VERSION 5.7 ;
  NOWIREEXTENSIONATPIN ON ;
  DIVIDERCHAR "/" ;
  BUSBITCHARS "[]" ;
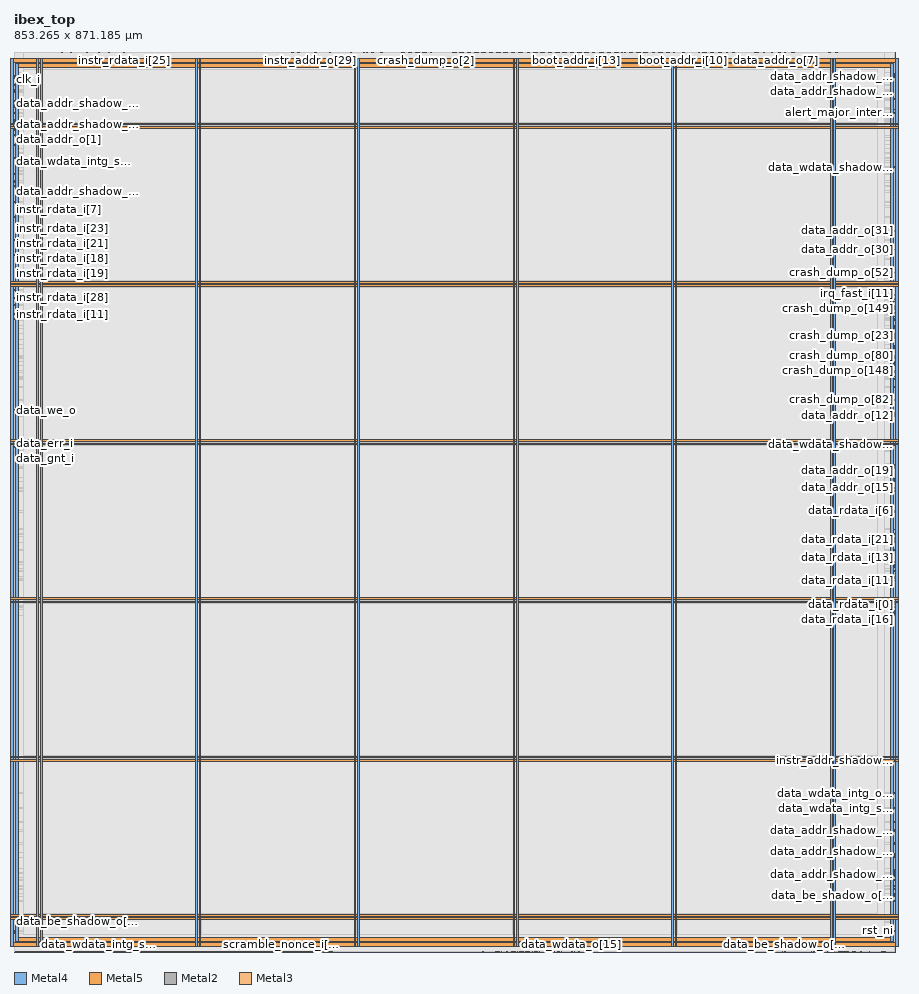
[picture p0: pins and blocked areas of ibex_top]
MACRO ibex_top
  CLASS BLOCK ;
  FOREIGN ibex_top ;
  ORIGIN 0.000 0.000 ;
  SIZE 853.265 BY 871.185 ;
  PIN VDD
    DIRECTION INOUT ;
    USE POWER ;
    PORT
      LAYER Metal4 ;
        RECT 1.620 10.580 4.720 859.660 ;
    END
    PORT
      LAYER Metal4 ;
        RECT 848.160 10.580 851.260 859.660 ;
    END
    PORT
      LAYER Metal5 ;
        RECT 1.620 10.580 851.260 13.680 ;
    END
    PORT
      LAYER Metal5 ;
        RECT 1.620 856.560 851.260 859.660 ;
    END
    PORT
      LAYER Metal4 ;
        RECT 22.240 5.780 23.840 864.460 ;
    END
    PORT
      LAYER Metal4 ;
        RECT 175.840 5.780 177.440 864.460 ;
    END
    PORT
      LAYER Metal4 ;
        RECT 329.440 5.780 331.040 864.460 ;
    END
    PORT
      LAYER Metal4 ;
        RECT 483.040 5.780 484.640 864.460 ;
    END
    PORT
      LAYER Metal4 ;
        RECT 636.640 5.780 638.240 864.460 ;
    END
    PORT
      LAYER Metal4 ;
        RECT 790.240 5.780 791.840 864.460 ;
    END
    PORT
      LAYER Metal5 ;
        RECT -3.180 31.530 856.060 33.130 ;
    END
    PORT
      LAYER Metal5 ;
        RECT -3.180 184.710 856.060 186.310 ;
    END
    PORT
      LAYER Metal5 ;
        RECT -3.180 337.890 856.060 339.490 ;
    END
    PORT
      LAYER Metal5 ;
        RECT -3.180 491.070 856.060 492.670 ;
    END
    PORT
      LAYER Metal5 ;
        RECT -3.180 644.250 856.060 645.850 ;
    END
    PORT
      LAYER Metal5 ;
        RECT -3.180 797.430 856.060 799.030 ;
    END
  END VDD
  PIN VSS
    DIRECTION INOUT ;
    USE GROUND ;
    PORT
      LAYER Metal4 ;
        RECT -3.180 5.780 -0.080 864.460 ;
    END
    PORT
      LAYER Metal4 ;
        RECT 852.960 5.780 856.060 864.460 ;
    END
    PORT
      LAYER Metal5 ;
        RECT -3.180 5.780 856.060 8.880 ;
    END
    PORT
      LAYER Metal5 ;
        RECT -3.180 861.360 856.060 864.460 ;
    END
    PORT
      LAYER Metal4 ;
        RECT 25.540 5.780 27.140 864.460 ;
    END
    PORT
      LAYER Metal4 ;
        RECT 179.140 5.780 180.740 864.460 ;
    END
    PORT
      LAYER Metal4 ;
        RECT 332.740 5.780 334.340 864.460 ;
    END
    PORT
      LAYER Metal4 ;
        RECT 486.340 5.780 487.940 864.460 ;
    END
    PORT
      LAYER Metal4 ;
        RECT 639.940 5.780 641.540 864.460 ;
    END
    PORT
      LAYER Metal4 ;
        RECT 793.540 5.780 795.140 864.460 ;
    END
    PORT
      LAYER Metal5 ;
        RECT -3.180 34.830 856.060 36.430 ;
    END
    PORT
      LAYER Metal5 ;
        RECT -3.180 188.010 856.060 189.610 ;
    END
    PORT
      LAYER Metal5 ;
        RECT -3.180 341.190 856.060 342.790 ;
    END
    PORT
      LAYER Metal5 ;
        RECT -3.180 494.370 856.060 495.970 ;
    END
    PORT
      LAYER Metal5 ;
        RECT -3.180 647.550 856.060 649.150 ;
    END
    PORT
      LAYER Metal5 ;
        RECT -3.180 800.730 856.060 802.330 ;
    END
  END VSS
  PIN alert_major_bus_o
    DIRECTION OUTPUT ;
    USE SIGNAL ;
    ANTENNADIFFAREA 0.360800 ;
    PORT
      LAYER Metal2 ;
        RECT 31.360 0.000 31.920 0.560 ;
    END
  END alert_major_bus_o
  PIN alert_major_internal_o
    DIRECTION OUTPUT ;
    USE SIGNAL ;
    ANTENNADIFFAREA 0.360800 ;
    PORT
      LAYER Metal3 ;
        RECT 852.705 812.000 853.265 812.560 ;
    END
  END alert_major_internal_o
  PIN alert_minor_o
    DIRECTION OUTPUT ;
    USE SIGNAL ;
    ANTENNADIFFAREA 0.360800 ;
    PORT
      LAYER Metal3 ;
        RECT 852.705 53.760 853.265 54.320 ;
    END
  END alert_minor_o
  PIN boot_addr_i[0]
    DIRECTION INPUT ;
    USE SIGNAL ;
    PORT
      LAYER Metal2 ;
        RECT 7.840 0.000 8.400 0.560 ;
    END
  END boot_addr_i[0]
  PIN boot_addr_i[10]
    DIRECTION INPUT ;
    USE SIGNAL ;
    ANTENNAGATEAREA 0.396000 ;
    PORT
      LAYER Metal2 ;
        RECT 647.360 870.625 647.920 871.185 ;
    END
  END boot_addr_i[10]
  PIN boot_addr_i[11]
    DIRECTION INPUT ;
    USE SIGNAL ;
    ANTENNAGATEAREA 0.396000 ;
    PORT
      LAYER Metal2 ;
        RECT 483.840 870.625 484.400 871.185 ;
    END
  END boot_addr_i[11]
  PIN boot_addr_i[12]
    DIRECTION INPUT ;
    USE SIGNAL ;
    ANTENNAGATEAREA 0.396000 ;
    PORT
      LAYER Metal2 ;
        RECT 493.920 870.625 494.480 871.185 ;
    END
  END boot_addr_i[12]
  PIN boot_addr_i[13]
    DIRECTION INPUT ;
    USE SIGNAL ;
    ANTENNAGATEAREA 0.396000 ;
    PORT
      LAYER Metal2 ;
        RECT 544.320 870.625 544.880 871.185 ;
    END
  END boot_addr_i[13]
  PIN boot_addr_i[14]
    DIRECTION INPUT ;
    USE SIGNAL ;
    ANTENNAGATEAREA 0.396000 ;
    PORT
      LAYER Metal2 ;
        RECT 619.360 870.625 619.920 871.185 ;
    END
  END boot_addr_i[14]
  PIN boot_addr_i[15]
    DIRECTION INPUT ;
    USE SIGNAL ;
    ANTENNAGATEAREA 0.396000 ;
    PORT
      LAYER Metal2 ;
        RECT 556.640 870.625 557.200 871.185 ;
    END
  END boot_addr_i[15]
  PIN boot_addr_i[16]
    DIRECTION INPUT ;
    USE SIGNAL ;
    ANTENNAGATEAREA 0.396000 ;
    PORT
      LAYER Metal2 ;
        RECT 568.960 870.625 569.520 871.185 ;
    END
  END boot_addr_i[16]
  PIN boot_addr_i[17]
    DIRECTION INPUT ;
    USE SIGNAL ;
    ANTENNAGATEAREA 0.396000 ;
    PORT
      LAYER Metal2 ;
        RECT 600.320 870.625 600.880 871.185 ;
    END
  END boot_addr_i[17]
  PIN boot_addr_i[18]
    DIRECTION INPUT ;
    USE SIGNAL ;
    ANTENNAGATEAREA 0.396000 ;
    PORT
      LAYER Metal2 ;
        RECT 651.840 870.625 652.400 871.185 ;
    END
  END boot_addr_i[18]
  PIN boot_addr_i[19]
    DIRECTION INPUT ;
    USE SIGNAL ;
    ANTENNAGATEAREA 0.396000 ;
    PORT
      LAYER Metal2 ;
        RECT 649.600 870.625 650.160 871.185 ;
    END
  END boot_addr_i[19]
  PIN boot_addr_i[1]
    DIRECTION INPUT ;
    USE SIGNAL ;
    PORT
      LAYER Metal2 ;
        RECT 5.600 0.000 6.160 0.560 ;
    END
  END boot_addr_i[1]
  PIN boot_addr_i[20]
    DIRECTION INPUT ;
    USE SIGNAL ;
    ANTENNAGATEAREA 0.396000 ;
    PORT
      LAYER Metal2 ;
        RECT 623.840 870.625 624.400 871.185 ;
    END
  END boot_addr_i[20]
  PIN boot_addr_i[21]
    DIRECTION INPUT ;
    USE SIGNAL ;
    ANTENNAGATEAREA 0.396000 ;
    PORT
      LAYER Metal2 ;
        RECT 588.000 870.625 588.560 871.185 ;
    END
  END boot_addr_i[21]
  PIN boot_addr_i[22]
    DIRECTION INPUT ;
    USE SIGNAL ;
    ANTENNAGATEAREA 0.396000 ;
    PORT
      LAYER Metal2 ;
        RECT 648.480 870.625 649.040 871.185 ;
    END
  END boot_addr_i[22]
  PIN boot_addr_i[23]
    DIRECTION INPUT ;
    USE SIGNAL ;
    ANTENNAGATEAREA 0.396000 ;
    PORT
      LAYER Metal2 ;
        RECT 650.720 870.625 651.280 871.185 ;
    END
  END boot_addr_i[23]
  PIN boot_addr_i[24]
    DIRECTION INPUT ;
    USE SIGNAL ;
    ANTENNAGATEAREA 0.396000 ;
    PORT
      LAYER Metal2 ;
        RECT 612.640 870.625 613.200 871.185 ;
    END
  END boot_addr_i[24]
  PIN boot_addr_i[25]
    DIRECTION INPUT ;
    USE SIGNAL ;
    ANTENNAGATEAREA 0.396000 ;
    PORT
      LAYER Metal2 ;
        RECT 543.200 870.625 543.760 871.185 ;
    END
  END boot_addr_i[25]
  PIN boot_addr_i[26]
    DIRECTION INPUT ;
    USE SIGNAL ;
    ANTENNAGATEAREA 0.396000 ;
    PORT
      LAYER Metal2 ;
        RECT 481.600 870.625 482.160 871.185 ;
    END
  END boot_addr_i[26]
  PIN boot_addr_i[27]
    DIRECTION INPUT ;
    USE SIGNAL ;
    ANTENNAGATEAREA 0.396000 ;
    PORT
      LAYER Metal2 ;
        RECT 638.400 870.625 638.960 871.185 ;
    END
  END boot_addr_i[27]
  PIN boot_addr_i[28]
    DIRECTION INPUT ;
    USE SIGNAL ;
    ANTENNAGATEAREA 0.396000 ;
    PORT
      LAYER Metal2 ;
        RECT 618.240 870.625 618.800 871.185 ;
    END
  END boot_addr_i[28]
  PIN boot_addr_i[29]
    DIRECTION INPUT ;
    USE SIGNAL ;
    ANTENNAGATEAREA 0.396000 ;
    PORT
      LAYER Metal2 ;
        RECT 452.480 870.625 453.040 871.185 ;
    END
  END boot_addr_i[29]
  PIN boot_addr_i[2]
    DIRECTION INPUT ;
    USE SIGNAL ;
    PORT
      LAYER Metal2 ;
        RECT 11.200 0.000 11.760 0.560 ;
    END
  END boot_addr_i[2]
  PIN boot_addr_i[30]
    DIRECTION INPUT ;
    USE SIGNAL ;
    ANTENNAGATEAREA 0.396000 ;
    PORT
      LAYER Metal2 ;
        RECT 470.400 870.625 470.960 871.185 ;
    END
  END boot_addr_i[30]
  PIN boot_addr_i[31]
    DIRECTION INPUT ;
    USE SIGNAL ;
    ANTENNAGATEAREA 0.396000 ;
    PORT
      LAYER Metal2 ;
        RECT 469.280 870.625 469.840 871.185 ;
    END
  END boot_addr_i[31]
  PIN boot_addr_i[3]
    DIRECTION INPUT ;
    USE SIGNAL ;
    PORT
      LAYER Metal2 ;
        RECT 44.800 0.000 45.360 0.560 ;
    END
  END boot_addr_i[3]
  PIN boot_addr_i[4]
    DIRECTION INPUT ;
    USE SIGNAL ;
    PORT
      LAYER Metal2 ;
        RECT 6.720 0.000 7.280 0.560 ;
    END
  END boot_addr_i[4]
  PIN boot_addr_i[5]
    DIRECTION INPUT ;
    USE SIGNAL ;
    PORT
      LAYER Metal2 ;
        RECT 10.080 0.000 10.640 0.560 ;
    END
  END boot_addr_i[5]
  PIN boot_addr_i[6]
    DIRECTION INPUT ;
    USE SIGNAL ;
    PORT
      LAYER Metal2 ;
        RECT 8.960 0.000 9.520 0.560 ;
    END
  END boot_addr_i[6]
  PIN boot_addr_i[7]
    DIRECTION INPUT ;
    USE SIGNAL ;
    PORT
      LAYER Metal2 ;
        RECT 12.320 0.000 12.880 0.560 ;
    END
  END boot_addr_i[7]
  PIN boot_addr_i[8]
    DIRECTION INPUT ;
    USE SIGNAL ;
    ANTENNAGATEAREA 0.396000 ;
    PORT
      LAYER Metal2 ;
        RECT 436.800 870.625 437.360 871.185 ;
    END
  END boot_addr_i[8]
  PIN boot_addr_i[9]
    DIRECTION INPUT ;
    USE SIGNAL ;
    ANTENNAGATEAREA 0.396000 ;
    PORT
      LAYER Metal2 ;
        RECT 463.680 870.625 464.240 871.185 ;
    END
  END boot_addr_i[9]
  PIN clk_i
    DIRECTION INPUT ;
    USE SIGNAL ;
    ANTENNAGATEAREA 4.738000 ;
    PORT
      LAYER Metal3 ;
        RECT 0.000 844.480 0.560 845.040 ;
    END
  END clk_i
  PIN core_sleep_o
    DIRECTION OUTPUT ;
    USE SIGNAL ;
    ANTENNADIFFAREA 0.897600 ;
    PORT
      LAYER Metal2 ;
        RECT 291.200 870.625 291.760 871.185 ;
    END
  END core_sleep_o
  PIN crash_dump_o[0]
    DIRECTION OUTPUT ;
    USE SIGNAL ;
    ANTENNADIFFAREA 0.897600 ;
    PORT
      LAYER Metal2 ;
        RECT 383.040 870.625 383.600 871.185 ;
    END
  END crash_dump_o[0]
  PIN crash_dump_o[100]
    DIRECTION OUTPUT ;
    USE SIGNAL ;
    ANTENNADIFFAREA 0.897600 ;
    PORT
      LAYER Metal2 ;
        RECT 355.040 870.625 355.600 871.185 ;
    END
  END crash_dump_o[100]
  PIN crash_dump_o[101]
    DIRECTION OUTPUT ;
    USE SIGNAL ;
    ANTENNADIFFAREA 0.897600 ;
    PORT
      LAYER Metal2 ;
        RECT 397.600 870.625 398.160 871.185 ;
    END
  END crash_dump_o[101]
  PIN crash_dump_o[102]
    DIRECTION OUTPUT ;
    USE SIGNAL ;
    ANTENNADIFFAREA 0.897600 ;
    PORT
      LAYER Metal2 ;
        RECT 381.920 870.625 382.480 871.185 ;
    END
  END crash_dump_o[102]
  PIN crash_dump_o[103]
    DIRECTION OUTPUT ;
    USE SIGNAL ;
    ANTENNADIFFAREA 0.897600 ;
    PORT
      LAYER Metal2 ;
        RECT 434.560 870.625 435.120 871.185 ;
    END
  END crash_dump_o[103]
  PIN crash_dump_o[104]
    DIRECTION OUTPUT ;
    USE SIGNAL ;
    ANTENNADIFFAREA 0.897600 ;
    PORT
      LAYER Metal2 ;
        RECT 460.320 870.625 460.880 871.185 ;
    END
  END crash_dump_o[104]
  PIN crash_dump_o[105]
    DIRECTION OUTPUT ;
    USE SIGNAL ;
    ANTENNADIFFAREA 0.897600 ;
    PORT
      LAYER Metal2 ;
        RECT 477.120 870.625 477.680 871.185 ;
    END
  END crash_dump_o[105]
  PIN crash_dump_o[106]
    DIRECTION OUTPUT ;
    USE SIGNAL ;
    ANTENNADIFFAREA 0.897600 ;
    PORT
      LAYER Metal2 ;
        RECT 539.840 870.625 540.400 871.185 ;
    END
  END crash_dump_o[106]
  PIN crash_dump_o[107]
    DIRECTION OUTPUT ;
    USE SIGNAL ;
    ANTENNADIFFAREA 0.897600 ;
    PORT
      LAYER Metal2 ;
        RECT 515.200 870.625 515.760 871.185 ;
    END
  END crash_dump_o[107]
  PIN crash_dump_o[108]
    DIRECTION OUTPUT ;
    USE SIGNAL ;
    ANTENNADIFFAREA 0.897600 ;
    PORT
      LAYER Metal2 ;
        RECT 512.960 870.625 513.520 871.185 ;
    END
  END crash_dump_o[108]
  PIN crash_dump_o[109]
    DIRECTION OUTPUT ;
    USE SIGNAL ;
    ANTENNADIFFAREA 0.897600 ;
    PORT
      LAYER Metal2 ;
        RECT 540.960 870.625 541.520 871.185 ;
    END
  END crash_dump_o[109]
  PIN crash_dump_o[10]
    DIRECTION OUTPUT ;
    USE SIGNAL ;
    ANTENNADIFFAREA 0.897600 ;
    PORT
      LAYER Metal2 ;
        RECT 668.640 870.625 669.200 871.185 ;
    END
  END crash_dump_o[10]
  PIN crash_dump_o[110]
    DIRECTION OUTPUT ;
    USE SIGNAL ;
    ANTENNADIFFAREA 0.897600 ;
    PORT
      LAYER Metal2 ;
        RECT 571.200 870.625 571.760 871.185 ;
    END
  END crash_dump_o[110]
  PIN crash_dump_o[111]
    DIRECTION OUTPUT ;
    USE SIGNAL ;
    ANTENNADIFFAREA 0.897600 ;
    PORT
      LAYER Metal2 ;
        RECT 553.280 870.625 553.840 871.185 ;
    END
  END crash_dump_o[111]
  PIN crash_dump_o[112]
    DIRECTION OUTPUT ;
    USE SIGNAL ;
    ANTENNADIFFAREA 0.897600 ;
    PORT
      LAYER Metal2 ;
        RECT 581.280 870.625 581.840 871.185 ;
    END
  END crash_dump_o[112]
  PIN crash_dump_o[113]
    DIRECTION OUTPUT ;
    USE SIGNAL ;
    ANTENNADIFFAREA 0.897600 ;
    PORT
      LAYER Metal2 ;
        RECT 604.800 870.625 605.360 871.185 ;
    END
  END crash_dump_o[113]
  PIN crash_dump_o[114]
    DIRECTION OUTPUT ;
    USE SIGNAL ;
    ANTENNADIFFAREA 0.897600 ;
    PORT
      LAYER Metal2 ;
        RECT 620.480 870.625 621.040 871.185 ;
    END
  END crash_dump_o[114]
  PIN crash_dump_o[115]
    DIRECTION OUTPUT ;
    USE SIGNAL ;
    ANTENNADIFFAREA 0.897600 ;
    PORT
      LAYER Metal2 ;
        RECT 608.160 870.625 608.720 871.185 ;
    END
  END crash_dump_o[115]
  PIN crash_dump_o[116]
    DIRECTION OUTPUT ;
    USE SIGNAL ;
    ANTENNADIFFAREA 0.897600 ;
    PORT
      LAYER Metal2 ;
        RECT 605.920 870.625 606.480 871.185 ;
    END
  END crash_dump_o[116]
  PIN crash_dump_o[117]
    DIRECTION OUTPUT ;
    USE SIGNAL ;
    ANTENNADIFFAREA 0.897600 ;
    PORT
      LAYER Metal2 ;
        RECT 593.600 870.625 594.160 871.185 ;
    END
  END crash_dump_o[117]
  PIN crash_dump_o[118]
    DIRECTION OUTPUT ;
    USE SIGNAL ;
    ANTENNADIFFAREA 0.897600 ;
    PORT
      LAYER Metal2 ;
        RECT 613.760 870.625 614.320 871.185 ;
    END
  END crash_dump_o[118]
  PIN crash_dump_o[119]
    DIRECTION OUTPUT ;
    USE SIGNAL ;
    ANTENNADIFFAREA 0.897600 ;
    PORT
      LAYER Metal2 ;
        RECT 607.040 870.625 607.600 871.185 ;
    END
  END crash_dump_o[119]
  PIN crash_dump_o[11]
    DIRECTION OUTPUT ;
    USE SIGNAL ;
    ANTENNADIFFAREA 0.897600 ;
    PORT
      LAYER Metal2 ;
        RECT 518.560 870.625 519.120 871.185 ;
    END
  END crash_dump_o[11]
  PIN crash_dump_o[120]
    DIRECTION OUTPUT ;
    USE SIGNAL ;
    ANTENNADIFFAREA 0.897600 ;
    PORT
      LAYER Metal2 ;
        RECT 592.480 870.625 593.040 871.185 ;
    END
  END crash_dump_o[120]
  PIN crash_dump_o[121]
    DIRECTION OUTPUT ;
    USE SIGNAL ;
    ANTENNADIFFAREA 0.897600 ;
    PORT
      LAYER Metal2 ;
        RECT 538.720 870.625 539.280 871.185 ;
    END
  END crash_dump_o[121]
  PIN crash_dump_o[122]
    DIRECTION OUTPUT ;
    USE SIGNAL ;
    ANTENNADIFFAREA 0.897600 ;
    PORT
      LAYER Metal2 ;
        RECT 526.400 870.625 526.960 871.185 ;
    END
  END crash_dump_o[122]
  PIN crash_dump_o[123]
    DIRECTION OUTPUT ;
    USE SIGNAL ;
    ANTENNADIFFAREA 0.897600 ;
    PORT
      LAYER Metal2 ;
        RECT 595.840 870.625 596.400 871.185 ;
    END
  END crash_dump_o[123]
  PIN crash_dump_o[124]
    DIRECTION OUTPUT ;
    USE SIGNAL ;
    ANTENNADIFFAREA 0.897600 ;
    PORT
      LAYER Metal2 ;
        RECT 594.720 870.625 595.280 871.185 ;
    END
  END crash_dump_o[124]
  PIN crash_dump_o[125]
    DIRECTION OUTPUT ;
    USE SIGNAL ;
    ANTENNADIFFAREA 0.897600 ;
    PORT
      LAYER Metal2 ;
        RECT 471.520 870.625 472.080 871.185 ;
    END
  END crash_dump_o[125]
  PIN crash_dump_o[126]
    DIRECTION OUTPUT ;
    USE SIGNAL ;
    ANTENNADIFFAREA 0.897600 ;
    PORT
      LAYER Metal2 ;
        RECT 491.680 870.625 492.240 871.185 ;
    END
  END crash_dump_o[126]
  PIN crash_dump_o[127]
    DIRECTION OUTPUT ;
    USE SIGNAL ;
    ANTENNADIFFAREA 0.897600 ;
    PORT
      LAYER Metal2 ;
        RECT 459.200 870.625 459.760 871.185 ;
    END
  END crash_dump_o[127]
  PIN crash_dump_o[128]
    DIRECTION OUTPUT ;
    USE SIGNAL ;
    ANTENNADIFFAREA 0.360800 ;
    PORT
      LAYER Metal3 ;
        RECT 0.000 846.720 0.560 847.280 ;
    END
  END crash_dump_o[128]
  PIN crash_dump_o[129]
    DIRECTION OUTPUT ;
    USE SIGNAL ;
    ANTENNADIFFAREA 0.897600 ;
    PORT
      LAYER Metal2 ;
        RECT 403.200 870.625 403.760 871.185 ;
    END
  END crash_dump_o[129]
  PIN crash_dump_o[12]
    DIRECTION OUTPUT ;
    USE SIGNAL ;
    ANTENNADIFFAREA 0.897600 ;
    PORT
      LAYER Metal2 ;
        RECT 533.120 870.625 533.680 871.185 ;
    END
  END crash_dump_o[12]
  PIN crash_dump_o[130]
    DIRECTION OUTPUT ;
    USE SIGNAL ;
    ANTENNADIFFAREA 0.897600 ;
    PORT
      LAYER Metal2 ;
        RECT 402.080 870.625 402.640 871.185 ;
    END
  END crash_dump_o[130]
  PIN crash_dump_o[131]
    DIRECTION OUTPUT ;
    USE SIGNAL ;
    ANTENNADIFFAREA 0.897600 ;
    PORT
      LAYER Metal2 ;
        RECT 400.960 870.625 401.520 871.185 ;
    END
  END crash_dump_o[131]
  PIN crash_dump_o[132]
    DIRECTION OUTPUT ;
    USE SIGNAL ;
    ANTENNADIFFAREA 0.897600 ;
    PORT
      LAYER Metal2 ;
        RECT 399.840 870.625 400.400 871.185 ;
    END
  END crash_dump_o[132]
  PIN crash_dump_o[133]
    DIRECTION OUTPUT ;
    USE SIGNAL ;
    ANTENNADIFFAREA 0.897600 ;
    PORT
      LAYER Metal2 ;
        RECT 423.360 870.625 423.920 871.185 ;
    END
  END crash_dump_o[133]
  PIN crash_dump_o[134]
    DIRECTION OUTPUT ;
    USE SIGNAL ;
    ANTENNADIFFAREA 0.897600 ;
    PORT
      LAYER Metal2 ;
        RECT 523.040 870.625 523.600 871.185 ;
    END
  END crash_dump_o[134]
  PIN crash_dump_o[135]
    DIRECTION OUTPUT ;
    USE SIGNAL ;
    ANTENNADIFFAREA 0.897600 ;
    PORT
      LAYER Metal2 ;
        RECT 449.120 870.625 449.680 871.185 ;
    END
  END crash_dump_o[135]
  PIN crash_dump_o[136]
    DIRECTION OUTPUT ;
    USE SIGNAL ;
    ANTENNADIFFAREA 0.897600 ;
    PORT
      LAYER Metal2 ;
        RECT 465.920 870.625 466.480 871.185 ;
    END
  END crash_dump_o[136]
  PIN crash_dump_o[137]
    DIRECTION OUTPUT ;
    USE SIGNAL ;
    ANTENNADIFFAREA 0.897600 ;
    PORT
      LAYER Metal2 ;
        RECT 502.880 870.625 503.440 871.185 ;
    END
  END crash_dump_o[137]
  PIN crash_dump_o[138]
    DIRECTION OUTPUT ;
    USE SIGNAL ;
    ANTENNADIFFAREA 0.897600 ;
    PORT
      LAYER Metal2 ;
        RECT 537.600 870.625 538.160 871.185 ;
    END
  END crash_dump_o[138]
  PIN crash_dump_o[139]
    DIRECTION OUTPUT ;
    USE SIGNAL ;
    ANTENNADIFFAREA 0.897600 ;
    PORT
      LAYER Metal2 ;
        RECT 517.440 870.625 518.000 871.185 ;
    END
  END crash_dump_o[139]
  PIN crash_dump_o[13]
    DIRECTION OUTPUT ;
    USE SIGNAL ;
    ANTENNADIFFAREA 0.897600 ;
    PORT
      LAYER Metal2 ;
        RECT 552.160 870.625 552.720 871.185 ;
    END
  END crash_dump_o[13]
  PIN crash_dump_o[140]
    DIRECTION OUTPUT ;
    USE SIGNAL ;
    ANTENNADIFFAREA 0.897600 ;
    PORT
      LAYER Metal2 ;
        RECT 536.480 870.625 537.040 871.185 ;
    END
  END crash_dump_o[140]
  PIN crash_dump_o[141]
    DIRECTION OUTPUT ;
    USE SIGNAL ;
    ANTENNADIFFAREA 0.897600 ;
    PORT
      LAYER Metal2 ;
        RECT 542.080 870.625 542.640 871.185 ;
    END
  END crash_dump_o[141]
  PIN crash_dump_o[142]
    DIRECTION OUTPUT ;
    USE SIGNAL ;
    ANTENNADIFFAREA 0.897600 ;
    PORT
      LAYER Metal2 ;
        RECT 564.480 870.625 565.040 871.185 ;
    END
  END crash_dump_o[142]
  PIN crash_dump_o[143]
    DIRECTION OUTPUT ;
    USE SIGNAL ;
    ANTENNADIFFAREA 0.897600 ;
    PORT
      LAYER Metal2 ;
        RECT 549.920 870.625 550.480 871.185 ;
    END
  END crash_dump_o[143]
  PIN crash_dump_o[144]
    DIRECTION OUTPUT ;
    USE SIGNAL ;
    ANTENNADIFFAREA 0.897600 ;
    PORT
      LAYER Metal2 ;
        RECT 572.320 870.625 572.880 871.185 ;
    END
  END crash_dump_o[144]
  PIN crash_dump_o[145]
    DIRECTION OUTPUT ;
    USE SIGNAL ;
    ANTENNADIFFAREA 0.897600 ;
    PORT
      LAYER Metal2 ;
        RECT 582.400 870.625 582.960 871.185 ;
    END
  END crash_dump_o[145]
  PIN crash_dump_o[146]
    DIRECTION OUTPUT ;
    USE SIGNAL ;
    ANTENNADIFFAREA 0.897600 ;
    PORT
      LAYER Metal2 ;
        RECT 603.680 870.625 604.240 871.185 ;
    END
  END crash_dump_o[146]
  PIN crash_dump_o[147]
    DIRECTION OUTPUT ;
    USE SIGNAL ;
    ANTENNADIFFAREA 0.897600 ;
    PORT
      LAYER Metal2 ;
        RECT 602.560 870.625 603.120 871.185 ;
    END
  END crash_dump_o[147]
  PIN crash_dump_o[148]
    DIRECTION OUTPUT ;
    USE SIGNAL ;
    ANTENNADIFFAREA 0.897600 ;
    PORT
      LAYER Metal3 ;
        RECT 852.705 562.240 853.265 562.800 ;
    END
  END crash_dump_o[148]
  PIN crash_dump_o[149]
    DIRECTION OUTPUT ;
    USE SIGNAL ;
    ANTENNADIFFAREA 0.897600 ;
    PORT
      LAYER Metal3 ;
        RECT 852.705 622.720 853.265 623.280 ;
    END
  END crash_dump_o[149]
  PIN crash_dump_o[14]
    DIRECTION OUTPUT ;
    USE SIGNAL ;
    ANTENNADIFFAREA 0.897600 ;
    PORT
      LAYER Metal2 ;
        RECT 630.560 870.625 631.120 871.185 ;
    END
  END crash_dump_o[14]
  PIN crash_dump_o[150]
    DIRECTION OUTPUT ;
    USE SIGNAL ;
    ANTENNADIFFAREA 0.897600 ;
    PORT
      LAYER Metal3 ;
        RECT 852.705 567.840 853.265 568.400 ;
    END
  END crash_dump_o[150]
  PIN crash_dump_o[151]
    DIRECTION OUTPUT ;
    USE SIGNAL ;
    ANTENNADIFFAREA 0.897600 ;
    PORT
      LAYER Metal3 ;
        RECT 852.705 618.240 853.265 618.800 ;
    END
  END crash_dump_o[151]
  PIN crash_dump_o[152]
    DIRECTION OUTPUT ;
    USE SIGNAL ;
    ANTENNADIFFAREA 0.897600 ;
    PORT
      LAYER Metal2 ;
        RECT 591.360 870.625 591.920 871.185 ;
    END
  END crash_dump_o[152]
  PIN crash_dump_o[153]
    DIRECTION OUTPUT ;
    USE SIGNAL ;
    ANTENNADIFFAREA 0.897600 ;
    PORT
      LAYER Metal2 ;
        RECT 561.120 870.625 561.680 871.185 ;
    END
  END crash_dump_o[153]
  PIN crash_dump_o[154]
    DIRECTION OUTPUT ;
    USE SIGNAL ;
    ANTENNADIFFAREA 0.897600 ;
    PORT
      LAYER Metal2 ;
        RECT 535.360 870.625 535.920 871.185 ;
    END
  END crash_dump_o[154]
  PIN crash_dump_o[155]
    DIRECTION OUTPUT ;
    USE SIGNAL ;
    ANTENNADIFFAREA 0.897600 ;
    PORT
      LAYER Metal3 ;
        RECT 852.705 603.680 853.265 604.240 ;
    END
  END crash_dump_o[155]
  PIN crash_dump_o[156]
    DIRECTION OUTPUT ;
    USE SIGNAL ;
    ANTENNADIFFAREA 0.897600 ;
    PORT
      LAYER Metal2 ;
        RECT 609.280 870.625 609.840 871.185 ;
    END
  END crash_dump_o[156]
  PIN crash_dump_o[157]
    DIRECTION OUTPUT ;
    USE SIGNAL ;
    ANTENNADIFFAREA 0.897600 ;
    PORT
      LAYER Metal2 ;
        RECT 488.320 870.625 488.880 871.185 ;
    END
  END crash_dump_o[157]
  PIN crash_dump_o[158]
    DIRECTION OUTPUT ;
    USE SIGNAL ;
    ANTENNADIFFAREA 0.897600 ;
    PORT
      LAYER Metal2 ;
        RECT 497.280 870.625 497.840 871.185 ;
    END
  END crash_dump_o[158]
  PIN crash_dump_o[159]
    DIRECTION OUTPUT ;
    USE SIGNAL ;
    ANTENNADIFFAREA 0.897600 ;
    PORT
      LAYER Metal2 ;
        RECT 479.360 870.625 479.920 871.185 ;
    END
  END crash_dump_o[159]
  PIN crash_dump_o[15]
    DIRECTION OUTPUT ;
    USE SIGNAL ;
    ANTENNADIFFAREA 0.897600 ;
    PORT
      LAYER Metal2 ;
        RECT 557.760 870.625 558.320 871.185 ;
    END
  END crash_dump_o[15]
  PIN crash_dump_o[16]
    DIRECTION OUTPUT ;
    USE SIGNAL ;
    ANTENNADIFFAREA 0.897600 ;
    PORT
      LAYER Metal2 ;
        RECT 583.520 870.625 584.080 871.185 ;
    END
  END crash_dump_o[16]
  PIN crash_dump_o[17]
    DIRECTION OUTPUT ;
    USE SIGNAL ;
    ANTENNADIFFAREA 0.897600 ;
    PORT
      LAYER Metal2 ;
        RECT 577.920 870.625 578.480 871.185 ;
    END
  END crash_dump_o[17]
  PIN crash_dump_o[18]
    DIRECTION OUTPUT ;
    USE SIGNAL ;
    ANTENNADIFFAREA 0.897600 ;
    PORT
      LAYER Metal2 ;
        RECT 669.760 870.625 670.320 871.185 ;
    END
  END crash_dump_o[18]
  PIN crash_dump_o[19]
    DIRECTION OUTPUT ;
    USE SIGNAL ;
    ANTENNADIFFAREA 0.897600 ;
    PORT
      LAYER Metal2 ;
        RECT 670.880 870.625 671.440 871.185 ;
    END
  END crash_dump_o[19]
  PIN crash_dump_o[1]
    DIRECTION OUTPUT ;
    USE SIGNAL ;
    ANTENNADIFFAREA 0.897600 ;
    PORT
      LAYER Metal2 ;
        RECT 378.560 870.625 379.120 871.185 ;
    END
  END crash_dump_o[1]
  PIN crash_dump_o[20]
    DIRECTION OUTPUT ;
    USE SIGNAL ;
    ANTENNADIFFAREA 0.897600 ;
    PORT
      LAYER Metal3 ;
        RECT 852.705 612.640 853.265 613.200 ;
    END
  END crash_dump_o[20]
  PIN crash_dump_o[21]
    DIRECTION OUTPUT ;
    USE SIGNAL ;
    ANTENNADIFFAREA 0.897600 ;
    PORT
      LAYER Metal2 ;
        RECT 574.560 870.625 575.120 871.185 ;
    END
  END crash_dump_o[21]
  PIN crash_dump_o[22]
    DIRECTION OUTPUT ;
    USE SIGNAL ;
    ANTENNADIFFAREA 0.897600 ;
    PORT
      LAYER Metal2 ;
        RECT 677.600 870.625 678.160 871.185 ;
    END
  END crash_dump_o[22]
  PIN crash_dump_o[23]
    DIRECTION OUTPUT ;
    USE SIGNAL ;
    ANTENNADIFFAREA 0.897600 ;
    PORT
      LAYER Metal3 ;
        RECT 852.705 596.960 853.265 597.520 ;
    END
  END crash_dump_o[23]
  PIN crash_dump_o[24]
    DIRECTION OUTPUT ;
    USE SIGNAL ;
    ANTENNADIFFAREA 0.897600 ;
    PORT
      LAYER Metal3 ;
        RECT 852.705 594.720 853.265 595.280 ;
    END
  END crash_dump_o[24]
  PIN crash_dump_o[25]
    DIRECTION OUTPUT ;
    USE SIGNAL ;
    ANTENNADIFFAREA 0.897600 ;
    PORT
      LAYER Metal2 ;
        RECT 551.040 870.625 551.600 871.185 ;
    END
  END crash_dump_o[25]
  PIN crash_dump_o[26]
    DIRECTION OUTPUT ;
    USE SIGNAL ;
    ANTENNADIFFAREA 0.897600 ;
    PORT
      LAYER Metal2 ;
        RECT 511.840 870.625 512.400 871.185 ;
    END
  END crash_dump_o[26]
  PIN crash_dump_o[27]
    DIRECTION OUTPUT ;
    USE SIGNAL ;
    ANTENNADIFFAREA 0.897600 ;
    PORT
      LAYER Metal3 ;
        RECT 852.705 598.080 853.265 598.640 ;
    END
  END crash_dump_o[27]
  PIN crash_dump_o[28]
    DIRECTION OUTPUT ;
    USE SIGNAL ;
    ANTENNADIFFAREA 0.897600 ;
    PORT
      LAYER Metal3 ;
        RECT 852.705 604.800 853.265 605.360 ;
    END
  END crash_dump_o[28]
  PIN crash_dump_o[29]
    DIRECTION OUTPUT ;
    USE SIGNAL ;
    ANTENNADIFFAREA 0.897600 ;
    PORT
      LAYER Metal2 ;
        RECT 472.640 870.625 473.200 871.185 ;
    END
  END crash_dump_o[29]
  PIN crash_dump_o[2]
    DIRECTION OUTPUT ;
    USE SIGNAL ;
    ANTENNADIFFAREA 0.897600 ;
    PORT
      LAYER Metal2 ;
        RECT 398.720 870.625 399.280 871.185 ;
    END
  END crash_dump_o[2]
  PIN crash_dump_o[30]
    DIRECTION OUTPUT ;
    USE SIGNAL ;
    ANTENNADIFFAREA 0.897600 ;
    PORT
      LAYER Metal2 ;
        RECT 504.000 870.625 504.560 871.185 ;
    END
  END crash_dump_o[30]
  PIN crash_dump_o[31]
    DIRECTION OUTPUT ;
    USE SIGNAL ;
    ANTENNADIFFAREA 0.897600 ;
    PORT
      LAYER Metal2 ;
        RECT 486.080 870.625 486.640 871.185 ;
    END
  END crash_dump_o[31]
  PIN crash_dump_o[32]
    DIRECTION OUTPUT ;
    USE SIGNAL ;
    ANTENNADIFFAREA 0.897600 ;
    PORT
      LAYER Metal2 ;
        RECT 396.480 870.625 397.040 871.185 ;
    END
  END crash_dump_o[32]
  PIN crash_dump_o[33]
    DIRECTION OUTPUT ;
    USE SIGNAL ;
    ANTENNADIFFAREA 0.897600 ;
    PORT
      LAYER Metal2 ;
        RECT 388.640 870.625 389.200 871.185 ;
    END
  END crash_dump_o[33]
  PIN crash_dump_o[34]
    DIRECTION OUTPUT ;
    USE SIGNAL ;
    ANTENNADIFFAREA 0.897600 ;
    PORT
      LAYER Metal2 ;
        RECT 384.160 870.625 384.720 871.185 ;
    END
  END crash_dump_o[34]
  PIN crash_dump_o[35]
    DIRECTION OUTPUT ;
    USE SIGNAL ;
    ANTENNADIFFAREA 0.897600 ;
    PORT
      LAYER Metal2 ;
        RECT 387.520 870.625 388.080 871.185 ;
    END
  END crash_dump_o[35]
  PIN crash_dump_o[36]
    DIRECTION OUTPUT ;
    USE SIGNAL ;
    ANTENNADIFFAREA 0.897600 ;
    PORT
      LAYER Metal2 ;
        RECT 390.880 870.625 391.440 871.185 ;
    END
  END crash_dump_o[36]
  PIN crash_dump_o[37]
    DIRECTION OUTPUT ;
    USE SIGNAL ;
    ANTENNADIFFAREA 0.897600 ;
    PORT
      LAYER Metal2 ;
        RECT 394.240 870.625 394.800 871.185 ;
    END
  END crash_dump_o[37]
  PIN crash_dump_o[38]
    DIRECTION OUTPUT ;
    USE SIGNAL ;
    ANTENNADIFFAREA 0.897600 ;
    PORT
      LAYER Metal2 ;
        RECT 627.200 870.625 627.760 871.185 ;
    END
  END crash_dump_o[38]
  PIN crash_dump_o[39]
    DIRECTION OUTPUT ;
    USE SIGNAL ;
    ANTENNADIFFAREA 0.897600 ;
    PORT
      LAYER Metal2 ;
        RECT 431.200 870.625 431.760 871.185 ;
    END
  END crash_dump_o[39]
  PIN crash_dump_o[3]
    DIRECTION OUTPUT ;
    USE SIGNAL ;
    ANTENNADIFFAREA 0.897600 ;
    PORT
      LAYER Metal2 ;
        RECT 440.160 870.625 440.720 871.185 ;
    END
  END crash_dump_o[3]
  PIN crash_dump_o[40]
    DIRECTION OUTPUT ;
    USE SIGNAL ;
    ANTENNADIFFAREA 0.897600 ;
    PORT
      LAYER Metal2 ;
        RECT 626.080 870.625 626.640 871.185 ;
    END
  END crash_dump_o[40]
  PIN crash_dump_o[41]
    DIRECTION OUTPUT ;
    USE SIGNAL ;
    ANTENNADIFFAREA 0.897600 ;
    PORT
      LAYER Metal2 ;
        RECT 499.520 870.625 500.080 871.185 ;
    END
  END crash_dump_o[41]
  PIN crash_dump_o[42]
    DIRECTION OUTPUT ;
    USE SIGNAL ;
    ANTENNADIFFAREA 0.897600 ;
    PORT
      LAYER Metal2 ;
        RECT 689.920 870.625 690.480 871.185 ;
    END
  END crash_dump_o[42]
  PIN crash_dump_o[43]
    DIRECTION OUTPUT ;
    USE SIGNAL ;
    ANTENNADIFFAREA 0.897600 ;
    PORT
      LAYER Metal2 ;
        RECT 507.360 870.625 507.920 871.185 ;
    END
  END crash_dump_o[43]
  PIN crash_dump_o[44]
    DIRECTION OUTPUT ;
    USE SIGNAL ;
    ANTENNADIFFAREA 0.897600 ;
    PORT
      LAYER Metal2 ;
        RECT 427.840 870.625 428.400 871.185 ;
    END
  END crash_dump_o[44]
  PIN crash_dump_o[45]
    DIRECTION OUTPUT ;
    USE SIGNAL ;
    ANTENNADIFFAREA 0.897600 ;
    PORT
      LAYER Metal2 ;
        RECT 546.560 870.625 547.120 871.185 ;
    END
  END crash_dump_o[45]
  PIN crash_dump_o[46]
    DIRECTION OUTPUT ;
    USE SIGNAL ;
    ANTENNADIFFAREA 0.897600 ;
    PORT
      LAYER Metal2 ;
        RECT 666.400 870.625 666.960 871.185 ;
    END
  END crash_dump_o[46]
  PIN crash_dump_o[47]
    DIRECTION OUTPUT ;
    USE SIGNAL ;
    ANTENNADIFFAREA 0.897600 ;
    PORT
      LAYER Metal2 ;
        RECT 534.240 870.625 534.800 871.185 ;
    END
  END crash_dump_o[47]
  PIN crash_dump_o[48]
    DIRECTION OUTPUT ;
    USE SIGNAL ;
    ANTENNADIFFAREA 0.897600 ;
    PORT
      LAYER Metal2 ;
        RECT 598.080 870.625 598.640 871.185 ;
    END
  END crash_dump_o[48]
  PIN crash_dump_o[49]
    DIRECTION OUTPUT ;
    USE SIGNAL ;
    ANTENNADIFFAREA 0.897600 ;
    PORT
      LAYER Metal2 ;
        RECT 596.960 870.625 597.520 871.185 ;
    END
  END crash_dump_o[49]
  PIN crash_dump_o[4]
    DIRECTION OUTPUT ;
    USE SIGNAL ;
    ANTENNADIFFAREA 0.897600 ;
    PORT
      LAYER Metal2 ;
        RECT 393.120 870.625 393.680 871.185 ;
    END
  END crash_dump_o[4]
  PIN crash_dump_o[50]
    DIRECTION OUTPUT ;
    USE SIGNAL ;
    ANTENNADIFFAREA 0.897600 ;
    PORT
      LAYER Metal2 ;
        RECT 665.280 870.625 665.840 871.185 ;
    END
  END crash_dump_o[50]
  PIN crash_dump_o[51]
    DIRECTION OUTPUT ;
    USE SIGNAL ;
    ANTENNADIFFAREA 0.897600 ;
    PORT
      LAYER Metal2 ;
        RECT 663.040 870.625 663.600 871.185 ;
    END
  END crash_dump_o[51]
  PIN crash_dump_o[52]
    DIRECTION OUTPUT ;
    USE SIGNAL ;
    ANTENNADIFFAREA 0.897600 ;
    PORT
      LAYER Metal3 ;
        RECT 852.705 657.440 853.265 658.000 ;
    END
  END crash_dump_o[52]
  PIN crash_dump_o[53]
    DIRECTION OUTPUT ;
    USE SIGNAL ;
    ANTENNADIFFAREA 0.897600 ;
    PORT
      LAYER Metal2 ;
        RECT 599.200 870.625 599.760 871.185 ;
    END
  END crash_dump_o[53]
  PIN crash_dump_o[54]
    DIRECTION OUTPUT ;
    USE SIGNAL ;
    ANTENNADIFFAREA 0.897600 ;
    PORT
      LAYER Metal2 ;
        RECT 664.160 870.625 664.720 871.185 ;
    END
  END crash_dump_o[54]
  PIN crash_dump_o[55]
    DIRECTION OUTPUT ;
    USE SIGNAL ;
    ANTENNADIFFAREA 0.897600 ;
    PORT
      LAYER Metal3 ;
        RECT 852.705 623.840 853.265 624.400 ;
    END
  END crash_dump_o[55]
  PIN crash_dump_o[56]
    DIRECTION OUTPUT ;
    USE SIGNAL ;
    ANTENNADIFFAREA 0.897600 ;
    PORT
      LAYER Metal2 ;
        RECT 631.680 870.625 632.240 871.185 ;
    END
  END crash_dump_o[56]
  PIN crash_dump_o[57]
    DIRECTION OUTPUT ;
    USE SIGNAL ;
    ANTENNADIFFAREA 0.897600 ;
    PORT
      LAYER Metal2 ;
        RECT 521.920 870.625 522.480 871.185 ;
    END
  END crash_dump_o[57]
  PIN crash_dump_o[58]
    DIRECTION OUTPUT ;
    USE SIGNAL ;
    ANTENNADIFFAREA 0.897600 ;
    PORT
      LAYER Metal2 ;
        RECT 480.480 870.625 481.040 871.185 ;
    END
  END crash_dump_o[58]
  PIN crash_dump_o[59]
    DIRECTION OUTPUT ;
    USE SIGNAL ;
    ANTENNADIFFAREA 0.897600 ;
    PORT
      LAYER Metal3 ;
        RECT 852.705 624.960 853.265 625.520 ;
    END
  END crash_dump_o[59]
  PIN crash_dump_o[5]
    DIRECTION OUTPUT ;
    USE SIGNAL ;
    ANTENNADIFFAREA 0.897600 ;
    PORT
      LAYER Metal2 ;
        RECT 428.960 870.625 429.520 871.185 ;
    END
  END crash_dump_o[5]
  PIN crash_dump_o[60]
    DIRECTION OUTPUT ;
    USE SIGNAL ;
    ANTENNADIFFAREA 0.897600 ;
    PORT
      LAYER Metal2 ;
        RECT 642.880 870.625 643.440 871.185 ;
    END
  END crash_dump_o[60]
  PIN crash_dump_o[61]
    DIRECTION OUTPUT ;
    USE SIGNAL ;
    ANTENNADIFFAREA 0.897600 ;
    PORT
      LAYER Metal2 ;
        RECT 445.760 870.625 446.320 871.185 ;
    END
  END crash_dump_o[61]
  PIN crash_dump_o[62]
    DIRECTION OUTPUT ;
    USE SIGNAL ;
    ANTENNADIFFAREA 0.897600 ;
    PORT
      LAYER Metal2 ;
        RECT 505.120 870.625 505.680 871.185 ;
    END
  END crash_dump_o[62]
  PIN crash_dump_o[63]
    DIRECTION OUTPUT ;
    USE SIGNAL ;
    ANTENNADIFFAREA 0.897600 ;
    PORT
      LAYER Metal2 ;
        RECT 462.560 870.625 463.120 871.185 ;
    END
  END crash_dump_o[63]
  PIN crash_dump_o[64]
    DIRECTION OUTPUT ;
    USE SIGNAL ;
    ANTENNADIFFAREA 0.897600 ;
    PORT
      LAYER Metal2 ;
        RECT 514.080 870.625 514.640 871.185 ;
    END
  END crash_dump_o[64]
  PIN crash_dump_o[65]
    DIRECTION OUTPUT ;
    USE SIGNAL ;
    ANTENNADIFFAREA 0.897600 ;
    PORT
      LAYER Metal2 ;
        RECT 392.000 870.625 392.560 871.185 ;
    END
  END crash_dump_o[65]
  PIN crash_dump_o[66]
    DIRECTION OUTPUT ;
    USE SIGNAL ;
    ANTENNADIFFAREA 0.897600 ;
    PORT
      LAYER Metal2 ;
        RECT 430.080 870.625 430.640 871.185 ;
    END
  END crash_dump_o[66]
  PIN crash_dump_o[67]
    DIRECTION OUTPUT ;
    USE SIGNAL ;
    ANTENNADIFFAREA 0.897600 ;
    PORT
      LAYER Metal2 ;
        RECT 516.320 870.625 516.880 871.185 ;
    END
  END crash_dump_o[67]
  PIN crash_dump_o[68]
    DIRECTION OUTPUT ;
    USE SIGNAL ;
    ANTENNADIFFAREA 0.897600 ;
    PORT
      LAYER Metal2 ;
        RECT 435.680 870.625 436.240 871.185 ;
    END
  END crash_dump_o[68]
  PIN crash_dump_o[69]
    DIRECTION OUTPUT ;
    USE SIGNAL ;
    ANTENNADIFFAREA 0.897600 ;
    PORT
      LAYER Metal2 ;
        RECT 528.640 870.625 529.200 871.185 ;
    END
  END crash_dump_o[69]
  PIN crash_dump_o[6]
    DIRECTION OUTPUT ;
    USE SIGNAL ;
    ANTENNADIFFAREA 0.897600 ;
    PORT
      LAYER Metal2 ;
        RECT 439.040 870.625 439.600 871.185 ;
    END
  END crash_dump_o[6]
  PIN crash_dump_o[70]
    DIRECTION OUTPUT ;
    USE SIGNAL ;
    ANTENNADIFFAREA 0.897600 ;
    PORT
      LAYER Metal2 ;
        RECT 548.800 870.625 549.360 871.185 ;
    END
  END crash_dump_o[70]
  PIN crash_dump_o[71]
    DIRECTION OUTPUT ;
    USE SIGNAL ;
    ANTENNADIFFAREA 0.897600 ;
    PORT
      LAYER Metal2 ;
        RECT 448.000 870.625 448.560 871.185 ;
    END
  END crash_dump_o[71]
  PIN crash_dump_o[72]
    DIRECTION OUTPUT ;
    USE SIGNAL ;
    ANTENNADIFFAREA 0.897600 ;
    PORT
      LAYER Metal2 ;
        RECT 467.040 870.625 467.600 871.185 ;
    END
  END crash_dump_o[72]
  PIN crash_dump_o[73]
    DIRECTION OUTPUT ;
    USE SIGNAL ;
    ANTENNADIFFAREA 0.897600 ;
    PORT
      LAYER Metal2 ;
        RECT 498.400 870.625 498.960 871.185 ;
    END
  END crash_dump_o[73]
  PIN crash_dump_o[74]
    DIRECTION OUTPUT ;
    USE SIGNAL ;
    ANTENNADIFFAREA 0.897600 ;
    PORT
      LAYER Metal2 ;
        RECT 527.520 870.625 528.080 871.185 ;
    END
  END crash_dump_o[74]
  PIN crash_dump_o[75]
    DIRECTION OUTPUT ;
    USE SIGNAL ;
    ANTENNADIFFAREA 0.897600 ;
    PORT
      LAYER Metal2 ;
        RECT 519.680 870.625 520.240 871.185 ;
    END
  END crash_dump_o[75]
  PIN crash_dump_o[76]
    DIRECTION OUTPUT ;
    USE SIGNAL ;
    ANTENNADIFFAREA 0.897600 ;
    PORT
      LAYER Metal2 ;
        RECT 520.800 870.625 521.360 871.185 ;
    END
  END crash_dump_o[76]
  PIN crash_dump_o[77]
    DIRECTION OUTPUT ;
    USE SIGNAL ;
    ANTENNADIFFAREA 0.897600 ;
    PORT
      LAYER Metal2 ;
        RECT 547.680 870.625 548.240 871.185 ;
    END
  END crash_dump_o[77]
  PIN crash_dump_o[78]
    DIRECTION OUTPUT ;
    USE SIGNAL ;
    ANTENNADIFFAREA 0.897600 ;
    PORT
      LAYER Metal2 ;
        RECT 570.080 870.625 570.640 871.185 ;
    END
  END crash_dump_o[78]
  PIN crash_dump_o[79]
    DIRECTION OUTPUT ;
    USE SIGNAL ;
    ANTENNADIFFAREA 0.897600 ;
    PORT
      LAYER Metal2 ;
        RECT 560.000 870.625 560.560 871.185 ;
    END
  END crash_dump_o[79]
  PIN crash_dump_o[7]
    DIRECTION OUTPUT ;
    USE SIGNAL ;
    ANTENNADIFFAREA 0.897600 ;
    PORT
      LAYER Metal2 ;
        RECT 433.440 870.625 434.000 871.185 ;
    END
  END crash_dump_o[7]
  PIN crash_dump_o[80]
    DIRECTION OUTPUT ;
    USE SIGNAL ;
    ANTENNADIFFAREA 0.897600 ;
    PORT
      LAYER Metal3 ;
        RECT 852.705 570.080 853.265 570.640 ;
    END
  END crash_dump_o[80]
  PIN crash_dump_o[81]
    DIRECTION OUTPUT ;
    USE SIGNAL ;
    ANTENNADIFFAREA 0.897600 ;
    PORT
      LAYER Metal3 ;
        RECT 852.705 546.560 853.265 547.120 ;
    END
  END crash_dump_o[81]
  PIN crash_dump_o[82]
    DIRECTION OUTPUT ;
    USE SIGNAL ;
    ANTENNADIFFAREA 0.897600 ;
    PORT
      LAYER Metal3 ;
        RECT 852.705 534.240 853.265 534.800 ;
    END
  END crash_dump_o[82]
  PIN crash_dump_o[83]
    DIRECTION OUTPUT ;
    USE SIGNAL ;
    ANTENNADIFFAREA 0.897600 ;
    PORT
      LAYER Metal3 ;
        RECT 852.705 586.880 853.265 587.440 ;
    END
  END crash_dump_o[83]
  PIN crash_dump_o[84]
    DIRECTION OUTPUT ;
    USE SIGNAL ;
    ANTENNADIFFAREA 0.897600 ;
    PORT
      LAYER Metal3 ;
        RECT 852.705 561.120 853.265 561.680 ;
    END
  END crash_dump_o[84]
  PIN crash_dump_o[85]
    DIRECTION OUTPUT ;
    USE SIGNAL ;
    ANTENNADIFFAREA 0.897600 ;
    PORT
      LAYER Metal3 ;
        RECT 852.705 585.760 853.265 586.320 ;
    END
  END crash_dump_o[85]
  PIN crash_dump_o[86]
    DIRECTION OUTPUT ;
    USE SIGNAL ;
    ANTENNADIFFAREA 0.897600 ;
    PORT
      LAYER Metal3 ;
        RECT 852.705 571.200 853.265 571.760 ;
    END
  END crash_dump_o[86]
  PIN crash_dump_o[87]
    DIRECTION OUTPUT ;
    USE SIGNAL ;
    ANTENNADIFFAREA 0.897600 ;
    PORT
      LAYER Metal3 ;
        RECT 852.705 576.800 853.265 577.360 ;
    END
  END crash_dump_o[87]
  PIN crash_dump_o[88]
    DIRECTION OUTPUT ;
    USE SIGNAL ;
    ANTENNADIFFAREA 0.897600 ;
    PORT
      LAYER Metal3 ;
        RECT 852.705 556.640 853.265 557.200 ;
    END
  END crash_dump_o[88]
  PIN crash_dump_o[89]
    DIRECTION OUTPUT ;
    USE SIGNAL ;
    ANTENNADIFFAREA 0.897600 ;
    PORT
      LAYER Metal3 ;
        RECT 852.705 554.400 853.265 554.960 ;
    END
  END crash_dump_o[89]
  PIN crash_dump_o[8]
    DIRECTION OUTPUT ;
    USE SIGNAL ;
    ANTENNADIFFAREA 0.897600 ;
    PORT
      LAYER Metal2 ;
        RECT 461.440 870.625 462.000 871.185 ;
    END
  END crash_dump_o[8]
  PIN crash_dump_o[90]
    DIRECTION OUTPUT ;
    USE SIGNAL ;
    ANTENNADIFFAREA 0.897600 ;
    PORT
      LAYER Metal2 ;
        RECT 525.280 870.625 525.840 871.185 ;
    END
  END crash_dump_o[90]
  PIN crash_dump_o[91]
    DIRECTION OUTPUT ;
    USE SIGNAL ;
    ANTENNADIFFAREA 0.897600 ;
    PORT
      LAYER Metal3 ;
        RECT 852.705 584.640 853.265 585.200 ;
    END
  END crash_dump_o[91]
  PIN crash_dump_o[92]
    DIRECTION OUTPUT ;
    USE SIGNAL ;
    ANTENNADIFFAREA 0.897600 ;
    PORT
      LAYER Metal3 ;
        RECT 852.705 574.560 853.265 575.120 ;
    END
  END crash_dump_o[92]
  PIN crash_dump_o[93]
    DIRECTION OUTPUT ;
    USE SIGNAL ;
    ANTENNADIFFAREA 0.897600 ;
    PORT
      LAYER Metal2 ;
        RECT 482.720 870.625 483.280 871.185 ;
    END
  END crash_dump_o[93]
  PIN crash_dump_o[94]
    DIRECTION OUTPUT ;
    USE SIGNAL ;
    ANTENNADIFFAREA 0.897600 ;
    PORT
      LAYER Metal2 ;
        RECT 500.640 870.625 501.200 871.185 ;
    END
  END crash_dump_o[94]
  PIN crash_dump_o[95]
    DIRECTION OUTPUT ;
    USE SIGNAL ;
    ANTENNADIFFAREA 0.897600 ;
    PORT
      LAYER Metal2 ;
        RECT 484.960 870.625 485.520 871.185 ;
    END
  END crash_dump_o[95]
  PIN crash_dump_o[96]
    DIRECTION OUTPUT ;
    USE SIGNAL ;
    ANTENNADIFFAREA 0.360800 ;
    PORT
      LAYER Metal3 ;
        RECT 852.705 63.840 853.265 64.400 ;
    END
  END crash_dump_o[96]
  PIN crash_dump_o[97]
    DIRECTION OUTPUT ;
    USE SIGNAL ;
    ANTENNADIFFAREA 0.897600 ;
    PORT
      LAYER Metal2 ;
        RECT 325.920 870.625 326.480 871.185 ;
    END
  END crash_dump_o[97]
  PIN crash_dump_o[98]
    DIRECTION OUTPUT ;
    USE SIGNAL ;
    ANTENNADIFFAREA 0.897600 ;
    PORT
      LAYER Metal2 ;
        RECT 338.240 870.625 338.800 871.185 ;
    END
  END crash_dump_o[98]
  PIN crash_dump_o[99]
    DIRECTION OUTPUT ;
    USE SIGNAL ;
    ANTENNADIFFAREA 0.897600 ;
    PORT
      LAYER Metal2 ;
        RECT 341.600 870.625 342.160 871.185 ;
    END
  END crash_dump_o[99]
  PIN crash_dump_o[9]
    DIRECTION OUTPUT ;
    USE SIGNAL ;
    ANTENNADIFFAREA 0.897600 ;
    PORT
      LAYER Metal2 ;
        RECT 473.760 870.625 474.320 871.185 ;
    END
  END crash_dump_o[9]
  PIN data_addr_o[0]
    DIRECTION OUTPUT ;
    USE SIGNAL ;
    ANTENNADIFFAREA 0.360800 ;
    PORT
      LAYER Metal3 ;
        RECT 0.000 772.800 0.560 773.360 ;
    END
  END data_addr_o[0]
  PIN data_addr_o[10]
    DIRECTION OUTPUT ;
    USE SIGNAL ;
    ANTENNADIFFAREA 0.897600 ;
    PORT
      LAYER Metal2 ;
        RECT 696.640 870.625 697.200 871.185 ;
    END
  END data_addr_o[10]
  PIN data_addr_o[11]
    DIRECTION OUTPUT ;
    USE SIGNAL ;
    ANTENNADIFFAREA 0.897600 ;
    PORT
      LAYER Metal2 ;
        RECT 733.600 870.625 734.160 871.185 ;
    END
  END data_addr_o[11]
  PIN data_addr_o[12]
    DIRECTION OUTPUT ;
    USE SIGNAL ;
    ANTENNADIFFAREA 0.897600 ;
    PORT
      LAYER Metal3 ;
        RECT 852.705 518.560 853.265 519.120 ;
    END
  END data_addr_o[12]
  PIN data_addr_o[13]
    DIRECTION OUTPUT ;
    USE SIGNAL ;
    ANTENNADIFFAREA 0.897600 ;
    PORT
      LAYER Metal2 ;
        RECT 714.560 870.625 715.120 871.185 ;
    END
  END data_addr_o[13]
  PIN data_addr_o[14]
    DIRECTION OUTPUT ;
    USE SIGNAL ;
    ANTENNADIFFAREA 0.897600 ;
    PORT
      LAYER Metal2 ;
        RECT 745.920 870.625 746.480 871.185 ;
    END
  END data_addr_o[14]
  PIN data_addr_o[15]
    DIRECTION OUTPUT ;
    USE SIGNAL ;
    ANTENNADIFFAREA 0.897600 ;
    PORT
      LAYER Metal3 ;
        RECT 852.705 449.120 853.265 449.680 ;
    END
  END data_addr_o[15]
  PIN data_addr_o[16]
    DIRECTION OUTPUT ;
    USE SIGNAL ;
    ANTENNADIFFAREA 0.897600 ;
    PORT
      LAYER Metal2 ;
        RECT 721.280 870.625 721.840 871.185 ;
    END
  END data_addr_o[16]
  PIN data_addr_o[17]
    DIRECTION OUTPUT ;
    USE SIGNAL ;
    ANTENNADIFFAREA 0.897600 ;
    PORT
      LAYER Metal2 ;
        RECT 695.520 870.625 696.080 871.185 ;
    END
  END data_addr_o[17]
  PIN data_addr_o[18]
    DIRECTION OUTPUT ;
    USE SIGNAL ;
    ANTENNADIFFAREA 0.897600 ;
    PORT
      LAYER Metal2 ;
        RECT 716.800 870.625 717.360 871.185 ;
    END
  END data_addr_o[18]
  PIN data_addr_o[19]
    DIRECTION OUTPUT ;
    USE SIGNAL ;
    ANTENNADIFFAREA 0.897600 ;
    PORT
      LAYER Metal3 ;
        RECT 852.705 458.080 853.265 458.640 ;
    END
  END data_addr_o[19]
  PIN data_addr_o[1]
    DIRECTION OUTPUT ;
    USE SIGNAL ;
    ANTENNADIFFAREA 0.360800 ;
    PORT
      LAYER Metal3 ;
        RECT 0.000 786.240 0.560 786.800 ;
    END
  END data_addr_o[1]
  PIN data_addr_o[20]
    DIRECTION OUTPUT ;
    USE SIGNAL ;
    ANTENNADIFFAREA 0.897600 ;
    PORT
      LAYER Metal3 ;
        RECT 852.705 636.160 853.265 636.720 ;
    END
  END data_addr_o[20]
  PIN data_addr_o[21]
    DIRECTION OUTPUT ;
    USE SIGNAL ;
    ANTENNADIFFAREA 0.897600 ;
    PORT
      LAYER Metal3 ;
        RECT 852.705 621.600 853.265 622.160 ;
    END
  END data_addr_o[21]
  PIN data_addr_o[22]
    DIRECTION OUTPUT ;
    USE SIGNAL ;
    ANTENNADIFFAREA 0.897600 ;
    PORT
      LAYER Metal2 ;
        RECT 719.040 870.625 719.600 871.185 ;
    END
  END data_addr_o[22]
  PIN data_addr_o[23]
    DIRECTION OUTPUT ;
    USE SIGNAL ;
    ANTENNADIFFAREA 0.897600 ;
    PORT
      LAYER Metal3 ;
        RECT 852.705 614.880 853.265 615.440 ;
    END
  END data_addr_o[23]
  PIN data_addr_o[24]
    DIRECTION OUTPUT ;
    USE SIGNAL ;
    ANTENNADIFFAREA 0.897600 ;
    PORT
      LAYER Metal2 ;
        RECT 715.680 870.625 716.240 871.185 ;
    END
  END data_addr_o[24]
  PIN data_addr_o[25]
    DIRECTION OUTPUT ;
    USE SIGNAL ;
    ANTENNADIFFAREA 0.897600 ;
    PORT
      LAYER Metal3 ;
        RECT 852.705 568.960 853.265 569.520 ;
    END
  END data_addr_o[25]
  PIN data_addr_o[26]
    DIRECTION OUTPUT ;
    USE SIGNAL ;
    ANTENNADIFFAREA 0.897600 ;
    PORT
      LAYER Metal3 ;
        RECT 852.705 471.520 853.265 472.080 ;
    END
  END data_addr_o[26]
  PIN data_addr_o[27]
    DIRECTION OUTPUT ;
    USE SIGNAL ;
    ANTENNADIFFAREA 0.897600 ;
    PORT
      LAYER Metal3 ;
        RECT 852.705 635.040 853.265 635.600 ;
    END
  END data_addr_o[27]
  PIN data_addr_o[28]
    DIRECTION OUTPUT ;
    USE SIGNAL ;
    ANTENNADIFFAREA 0.897600 ;
    PORT
      LAYER Metal3 ;
        RECT 852.705 470.400 853.265 470.960 ;
    END
  END data_addr_o[28]
  PIN data_addr_o[29]
    DIRECTION OUTPUT ;
    USE SIGNAL ;
    ANTENNADIFFAREA 0.897600 ;
    PORT
      LAYER Metal3 ;
        RECT 852.705 468.160 853.265 468.720 ;
    END
  END data_addr_o[29]
  PIN data_addr_o[2]
    DIRECTION OUTPUT ;
    USE SIGNAL ;
    ANTENNADIFFAREA 0.897600 ;
    PORT
      LAYER Metal2 ;
        RECT 729.120 870.625 729.680 871.185 ;
    END
  END data_addr_o[2]
  PIN data_addr_o[30]
    DIRECTION OUTPUT ;
    USE SIGNAL ;
    ANTENNADIFFAREA 0.897600 ;
    PORT
      LAYER Metal3 ;
        RECT 852.705 679.840 853.265 680.400 ;
    END
  END data_addr_o[30]
  PIN data_addr_o[31]
    DIRECTION OUTPUT ;
    USE SIGNAL ;
    ANTENNADIFFAREA 0.897600 ;
    PORT
      LAYER Metal3 ;
        RECT 852.705 697.760 853.265 698.320 ;
    END
  END data_addr_o[31]
  PIN data_addr_o[3]
    DIRECTION OUTPUT ;
    USE SIGNAL ;
    ANTENNADIFFAREA 0.897600 ;
    PORT
      LAYER Metal3 ;
        RECT 852.705 519.680 853.265 520.240 ;
    END
  END data_addr_o[3]
  PIN data_addr_o[4]
    DIRECTION OUTPUT ;
    USE SIGNAL ;
    ANTENNADIFFAREA 0.897600 ;
    PORT
      LAYER Metal3 ;
        RECT 852.705 520.800 853.265 521.360 ;
    END
  END data_addr_o[4]
  PIN data_addr_o[5]
    DIRECTION OUTPUT ;
    USE SIGNAL ;
    ANTENNADIFFAREA 0.897600 ;
    PORT
      LAYER Metal3 ;
        RECT 852.705 521.920 853.265 522.480 ;
    END
  END data_addr_o[5]
  PIN data_addr_o[6]
    DIRECTION OUTPUT ;
    USE SIGNAL ;
    ANTENNADIFFAREA 0.897600 ;
    PORT
      LAYER Metal3 ;
        RECT 852.705 456.960 853.265 457.520 ;
    END
  END data_addr_o[6]
  PIN data_addr_o[7]
    DIRECTION OUTPUT ;
    USE SIGNAL ;
    ANTENNADIFFAREA 0.897600 ;
    PORT
      LAYER Metal2 ;
        RECT 736.960 870.625 737.520 871.185 ;
    END
  END data_addr_o[7]
  PIN data_addr_o[8]
    DIRECTION OUTPUT ;
    USE SIGNAL ;
    ANTENNADIFFAREA 0.897600 ;
    PORT
      LAYER Metal3 ;
        RECT 852.705 445.760 853.265 446.320 ;
    END
  END data_addr_o[8]
  PIN data_addr_o[9]
    DIRECTION OUTPUT ;
    USE SIGNAL ;
    ANTENNADIFFAREA 0.897600 ;
    PORT
      LAYER Metal3 ;
        RECT 852.705 455.840 853.265 456.400 ;
    END
  END data_addr_o[9]
  PIN data_addr_shadow_o[0]
    DIRECTION OUTPUT ;
    USE SIGNAL ;
    ANTENNADIFFAREA 0.360800 ;
    PORT
      LAYER Metal2 ;
        RECT 776.160 0.000 776.720 0.560 ;
    END
  END data_addr_shadow_o[0]
  PIN data_addr_shadow_o[10]
    DIRECTION OUTPUT ;
    USE SIGNAL ;
    ANTENNADIFFAREA 0.360800 ;
    PORT
      LAYER Metal3 ;
        RECT 852.705 117.600 853.265 118.160 ;
    END
  END data_addr_shadow_o[10]
  PIN data_addr_shadow_o[11]
    DIRECTION OUTPUT ;
    USE SIGNAL ;
    ANTENNADIFFAREA 0.360800 ;
    PORT
      LAYER Metal2 ;
        RECT 805.280 0.000 805.840 0.560 ;
    END
  END data_addr_shadow_o[11]
  PIN data_addr_shadow_o[12]
    DIRECTION OUTPUT ;
    USE SIGNAL ;
    ANTENNADIFFAREA 0.360800 ;
    PORT
      LAYER Metal3 ;
        RECT 0.000 820.960 0.560 821.520 ;
    END
  END data_addr_shadow_o[12]
  PIN data_addr_shadow_o[13]
    DIRECTION OUTPUT ;
    USE SIGNAL ;
    ANTENNADIFFAREA 0.360800 ;
    PORT
      LAYER Metal2 ;
        RECT 741.440 870.625 742.000 871.185 ;
    END
  END data_addr_shadow_o[13]
  PIN data_addr_shadow_o[14]
    DIRECTION OUTPUT ;
    USE SIGNAL ;
    ANTENNADIFFAREA 0.360800 ;
    PORT
      LAYER Metal3 ;
        RECT 852.705 75.040 853.265 75.600 ;
    END
  END data_addr_shadow_o[14]
  PIN data_addr_shadow_o[15]
    DIRECTION OUTPUT ;
    USE SIGNAL ;
    ANTENNADIFFAREA 0.360800 ;
    PORT
      LAYER Metal2 ;
        RECT 763.840 870.625 764.400 871.185 ;
    END
  END data_addr_shadow_o[15]
  PIN data_addr_shadow_o[16]
    DIRECTION OUTPUT ;
    USE SIGNAL ;
    ANTENNADIFFAREA 0.360800 ;
    PORT
      LAYER Metal2 ;
        RECT 781.760 0.000 782.320 0.560 ;
    END
  END data_addr_shadow_o[16]
  PIN data_addr_shadow_o[17]
    DIRECTION OUTPUT ;
    USE SIGNAL ;
    ANTENNADIFFAREA 0.360800 ;
    PORT
      LAYER Metal2 ;
        RECT 798.560 0.000 799.120 0.560 ;
    END
  END data_addr_shadow_o[17]
  PIN data_addr_shadow_o[18]
    DIRECTION OUTPUT ;
    USE SIGNAL ;
    ANTENNADIFFAREA 0.360800 ;
    PORT
      LAYER Metal3 ;
        RECT 852.705 77.280 853.265 77.840 ;
    END
  END data_addr_shadow_o[18]
  PIN data_addr_shadow_o[19]
    DIRECTION OUTPUT ;
    USE SIGNAL ;
    ANTENNADIFFAREA 0.360800 ;
    PORT
      LAYER Metal2 ;
        RECT 806.400 0.000 806.960 0.560 ;
    END
  END data_addr_shadow_o[19]
  PIN data_addr_shadow_o[1]
    DIRECTION OUTPUT ;
    USE SIGNAL ;
    ANTENNADIFFAREA 0.360800 ;
    PORT
      LAYER Metal3 ;
        RECT 852.705 78.400 853.265 78.960 ;
    END
  END data_addr_shadow_o[1]
  PIN data_addr_shadow_o[20]
    DIRECTION OUTPUT ;
    USE SIGNAL ;
    ANTENNADIFFAREA 0.360800 ;
    PORT
      LAYER Metal3 ;
        RECT 0.000 792.960 0.560 793.520 ;
    END
  END data_addr_shadow_o[20]
  PIN data_addr_shadow_o[21]
    DIRECTION OUTPUT ;
    USE SIGNAL ;
    ANTENNADIFFAREA 0.360800 ;
    PORT
      LAYER Metal3 ;
        RECT 0.000 735.840 0.560 736.400 ;
    END
  END data_addr_shadow_o[21]
  PIN data_addr_shadow_o[22]
    DIRECTION OUTPUT ;
    USE SIGNAL ;
    ANTENNADIFFAREA 0.360800 ;
    PORT
      LAYER Metal3 ;
        RECT 852.705 846.720 853.265 847.280 ;
    END
  END data_addr_shadow_o[22]
  PIN data_addr_shadow_o[23]
    DIRECTION OUTPUT ;
    USE SIGNAL ;
    ANTENNADIFFAREA 0.360800 ;
    PORT
      LAYER Metal3 ;
        RECT 852.705 104.160 853.265 104.720 ;
    END
  END data_addr_shadow_o[23]
  PIN data_addr_shadow_o[24]
    DIRECTION OUTPUT ;
    USE SIGNAL ;
    ANTENNADIFFAREA 0.360800 ;
    PORT
      LAYER Metal2 ;
        RECT 813.120 0.000 813.680 0.560 ;
    END
  END data_addr_shadow_o[24]
  PIN data_addr_shadow_o[25]
    DIRECTION OUTPUT ;
    USE SIGNAL ;
    ANTENNADIFFAREA 0.360800 ;
    PORT
      LAYER Metal3 ;
        RECT 0.000 795.200 0.560 795.760 ;
    END
  END data_addr_shadow_o[25]
  PIN data_addr_shadow_o[26]
    DIRECTION OUTPUT ;
    USE SIGNAL ;
    ANTENNADIFFAREA 0.360800 ;
    PORT
      LAYER Metal2 ;
        RECT 54.880 870.625 55.440 871.185 ;
    END
  END data_addr_shadow_o[26]
  PIN data_addr_shadow_o[27]
    DIRECTION OUTPUT ;
    USE SIGNAL ;
    ANTENNADIFFAREA 0.360800 ;
    PORT
      LAYER Metal3 ;
        RECT 852.705 825.440 853.265 826.000 ;
    END
  END data_addr_shadow_o[27]
  PIN data_addr_shadow_o[28]
    DIRECTION OUTPUT ;
    USE SIGNAL ;
    ANTENNADIFFAREA 0.360800 ;
    PORT
      LAYER Metal3 ;
        RECT 0.000 822.080 0.560 822.640 ;
    END
  END data_addr_shadow_o[28]
  PIN data_addr_shadow_o[29]
    DIRECTION OUTPUT ;
    USE SIGNAL ;
    ANTENNADIFFAREA 0.360800 ;
    PORT
      LAYER Metal2 ;
        RECT 45.920 870.625 46.480 871.185 ;
    END
  END data_addr_shadow_o[29]
  PIN data_addr_shadow_o[2]
    DIRECTION OUTPUT ;
    USE SIGNAL ;
    ANTENNADIFFAREA 0.360800 ;
    PORT
      LAYER Metal2 ;
        RECT 775.040 0.000 775.600 0.560 ;
    END
  END data_addr_shadow_o[2]
  PIN data_addr_shadow_o[30]
    DIRECTION OUTPUT ;
    USE SIGNAL ;
    ANTENNADIFFAREA 0.360800 ;
    PORT
      LAYER Metal2 ;
        RECT 26.880 0.000 27.440 0.560 ;
    END
  END data_addr_shadow_o[30]
  PIN data_addr_shadow_o[31]
    DIRECTION OUTPUT ;
    USE SIGNAL ;
    ANTENNADIFFAREA 0.360800 ;
    PORT
      LAYER Metal3 ;
        RECT 0.000 838.880 0.560 839.440 ;
    END
  END data_addr_shadow_o[31]
  PIN data_addr_shadow_o[3]
    DIRECTION OUTPUT ;
    USE SIGNAL ;
    ANTENNADIFFAREA 0.360800 ;
    PORT
      LAYER Metal2 ;
        RECT 807.520 0.000 808.080 0.560 ;
    END
  END data_addr_shadow_o[3]
  PIN data_addr_shadow_o[4]
    DIRECTION OUTPUT ;
    USE SIGNAL ;
    ANTENNADIFFAREA 0.360800 ;
    PORT
      LAYER Metal2 ;
        RECT 796.320 870.625 796.880 871.185 ;
    END
  END data_addr_shadow_o[4]
  PIN data_addr_shadow_o[5]
    DIRECTION OUTPUT ;
    USE SIGNAL ;
    ANTENNADIFFAREA 0.360800 ;
    PORT
      LAYER Metal2 ;
        RECT 29.120 870.625 29.680 871.185 ;
    END
  END data_addr_shadow_o[5]
  PIN data_addr_shadow_o[6]
    DIRECTION OUTPUT ;
    USE SIGNAL ;
    ANTENNADIFFAREA 0.360800 ;
    PORT
      LAYER Metal3 ;
        RECT 852.705 92.960 853.265 93.520 ;
    END
  END data_addr_shadow_o[6]
  PIN data_addr_shadow_o[7]
    DIRECTION OUTPUT ;
    USE SIGNAL ;
    ANTENNADIFFAREA 0.360800 ;
    PORT
      LAYER Metal3 ;
        RECT 0.000 798.560 0.560 799.120 ;
    END
  END data_addr_shadow_o[7]
  PIN data_addr_shadow_o[8]
    DIRECTION OUTPUT ;
    USE SIGNAL ;
    ANTENNADIFFAREA 0.360800 ;
    PORT
      LAYER Metal3 ;
        RECT 0.000 817.600 0.560 818.160 ;
    END
  END data_addr_shadow_o[8]
  PIN data_addr_shadow_o[9]
    DIRECTION OUTPUT ;
    USE SIGNAL ;
    ANTENNADIFFAREA 0.360800 ;
    PORT
      LAYER Metal2 ;
        RECT 771.680 870.625 772.240 871.185 ;
    END
  END data_addr_shadow_o[9]
  PIN data_be_o[0]
    DIRECTION OUTPUT ;
    USE SIGNAL ;
    ANTENNADIFFAREA 0.897600 ;
    PORT
      LAYER Metal2 ;
        RECT 468.160 0.000 468.720 0.560 ;
    END
  END data_be_o[0]
  PIN data_be_o[1]
    DIRECTION OUTPUT ;
    USE SIGNAL ;
    ANTENNADIFFAREA 0.897600 ;
    PORT
      LAYER Metal2 ;
        RECT 467.040 0.000 467.600 0.560 ;
    END
  END data_be_o[1]
  PIN data_be_o[2]
    DIRECTION OUTPUT ;
    USE SIGNAL ;
    ANTENNADIFFAREA 0.897600 ;
    PORT
      LAYER Metal2 ;
        RECT 465.920 0.000 466.480 0.560 ;
    END
  END data_be_o[2]
  PIN data_be_o[3]
    DIRECTION OUTPUT ;
    USE SIGNAL ;
    ANTENNADIFFAREA 0.897600 ;
    PORT
      LAYER Metal2 ;
        RECT 453.600 0.000 454.160 0.560 ;
    END
  END data_be_o[3]
  PIN data_be_shadow_o[0]
    DIRECTION OUTPUT ;
    USE SIGNAL ;
    ANTENNADIFFAREA 0.360800 ;
    PORT
      LAYER Metal2 ;
        RECT 745.920 0.000 746.480 0.560 ;
    END
  END data_be_shadow_o[0]
  PIN data_be_shadow_o[1]
    DIRECTION OUTPUT ;
    USE SIGNAL ;
    ANTENNADIFFAREA 0.360800 ;
    PORT
      LAYER Metal3 ;
        RECT 0.000 29.120 0.560 29.680 ;
    END
  END data_be_shadow_o[1]
  PIN data_be_shadow_o[2]
    DIRECTION OUTPUT ;
    USE SIGNAL ;
    ANTENNADIFFAREA 0.360800 ;
    PORT
      LAYER Metal2 ;
        RECT 827.680 0.000 828.240 0.560 ;
    END
  END data_be_shadow_o[2]
  PIN data_be_shadow_o[3]
    DIRECTION OUTPUT ;
    USE SIGNAL ;
    ANTENNADIFFAREA 0.360800 ;
    PORT
      LAYER Metal3 ;
        RECT 852.705 54.880 853.265 55.440 ;
    END
  END data_be_shadow_o[3]
  PIN data_err_i
    DIRECTION INPUT ;
    USE SIGNAL ;
    ANTENNAGATEAREA 0.396000 ;
    PORT
      LAYER Metal3 ;
        RECT 0.000 491.680 0.560 492.240 ;
    END
  END data_err_i
  PIN data_gnt_i
    DIRECTION INPUT ;
    USE SIGNAL ;
    ANTENNAGATEAREA 0.396000 ;
    PORT
      LAYER Metal3 ;
        RECT 0.000 484.960 0.560 485.520 ;
    END
  END data_gnt_i
  PIN data_rdata_i[0]
    DIRECTION INPUT ;
    USE SIGNAL ;
    ANTENNAGATEAREA 0.396000 ;
    PORT
      LAYER Metal3 ;
        RECT 852.705 336.000 853.265 336.560 ;
    END
  END data_rdata_i[0]
  PIN data_rdata_i[10]
    DIRECTION INPUT ;
    USE SIGNAL ;
    ANTENNAGATEAREA 0.396000 ;
    PORT
      LAYER Metal3 ;
        RECT 852.705 396.480 853.265 397.040 ;
    END
  END data_rdata_i[10]
  PIN data_rdata_i[11]
    DIRECTION INPUT ;
    USE SIGNAL ;
    ANTENNAGATEAREA 0.396000 ;
    PORT
      LAYER Metal3 ;
        RECT 852.705 359.520 853.265 360.080 ;
    END
  END data_rdata_i[11]
  PIN data_rdata_i[12]
    DIRECTION INPUT ;
    USE SIGNAL ;
    ANTENNAGATEAREA 0.396000 ;
    PORT
      LAYER Metal3 ;
        RECT 852.705 362.880 853.265 363.440 ;
    END
  END data_rdata_i[12]
  PIN data_rdata_i[13]
    DIRECTION INPUT ;
    USE SIGNAL ;
    ANTENNAGATEAREA 0.396000 ;
    PORT
      LAYER Metal3 ;
        RECT 852.705 388.640 853.265 389.200 ;
    END
  END data_rdata_i[13]
  PIN data_rdata_i[14]
    DIRECTION INPUT ;
    USE SIGNAL ;
    ANTENNAGATEAREA 0.396000 ;
    PORT
      LAYER Metal2 ;
        RECT 489.440 870.625 490.000 871.185 ;
    END
  END data_rdata_i[14]
  PIN data_rdata_i[15]
    DIRECTION INPUT ;
    USE SIGNAL ;
    ANTENNAGATEAREA 0.396000 ;
    PORT
      LAYER Metal2 ;
        RECT 443.520 870.625 444.080 871.185 ;
    END
  END data_rdata_i[15]
  PIN data_rdata_i[16]
    DIRECTION INPUT ;
    USE SIGNAL ;
    ANTENNAGATEAREA 0.396000 ;
    PORT
      LAYER Metal3 ;
        RECT 852.705 329.280 853.265 329.840 ;
    END
  END data_rdata_i[16]
  PIN data_rdata_i[17]
    DIRECTION INPUT ;
    USE SIGNAL ;
    ANTENNAGATEAREA 0.396000 ;
    PORT
      LAYER Metal3 ;
        RECT 852.705 325.920 853.265 326.480 ;
    END
  END data_rdata_i[17]
  PIN data_rdata_i[18]
    DIRECTION INPUT ;
    USE SIGNAL ;
    ANTENNAGATEAREA 0.396000 ;
    PORT
      LAYER Metal3 ;
        RECT 852.705 397.600 853.265 398.160 ;
    END
  END data_rdata_i[18]
  PIN data_rdata_i[19]
    DIRECTION INPUT ;
    USE SIGNAL ;
    ANTENNAGATEAREA 0.396000 ;
    PORT
      LAYER Metal3 ;
        RECT 852.705 371.840 853.265 372.400 ;
    END
  END data_rdata_i[19]
  PIN data_rdata_i[1]
    DIRECTION INPUT ;
    USE SIGNAL ;
    ANTENNAGATEAREA 0.396000 ;
    PORT
      LAYER Metal3 ;
        RECT 852.705 333.760 853.265 334.320 ;
    END
  END data_rdata_i[1]
  PIN data_rdata_i[20]
    DIRECTION INPUT ;
    USE SIGNAL ;
    ANTENNAGATEAREA 0.396000 ;
    PORT
      LAYER Metal3 ;
        RECT 852.705 374.080 853.265 374.640 ;
    END
  END data_rdata_i[20]
  PIN data_rdata_i[21]
    DIRECTION INPUT ;
    USE SIGNAL ;
    ANTENNAGATEAREA 0.396000 ;
    PORT
      LAYER Metal3 ;
        RECT 852.705 398.720 853.265 399.280 ;
    END
  END data_rdata_i[21]
  PIN data_rdata_i[22]
    DIRECTION INPUT ;
    USE SIGNAL ;
    ANTENNAGATEAREA 0.396000 ;
    PORT
      LAYER Metal2 ;
        RECT 478.240 870.625 478.800 871.185 ;
    END
  END data_rdata_i[22]
  PIN data_rdata_i[23]
    DIRECTION INPUT ;
    USE SIGNAL ;
    ANTENNAGATEAREA 0.396000 ;
    PORT
      LAYER Metal2 ;
        RECT 453.600 870.625 454.160 871.185 ;
    END
  END data_rdata_i[23]
  PIN data_rdata_i[24]
    DIRECTION INPUT ;
    USE SIGNAL ;
    ANTENNAGATEAREA 0.396000 ;
    PORT
      LAYER Metal3 ;
        RECT 852.705 327.040 853.265 327.600 ;
    END
  END data_rdata_i[24]
  PIN data_rdata_i[25]
    DIRECTION INPUT ;
    USE SIGNAL ;
    ANTENNAGATEAREA 0.396000 ;
    PORT
      LAYER Metal3 ;
        RECT 852.705 328.160 853.265 328.720 ;
    END
  END data_rdata_i[25]
  PIN data_rdata_i[26]
    DIRECTION INPUT ;
    USE SIGNAL ;
    ANTENNAGATEAREA 0.396000 ;
    PORT
      LAYER Metal3 ;
        RECT 852.705 408.800 853.265 409.360 ;
    END
  END data_rdata_i[26]
  PIN data_rdata_i[27]
    DIRECTION INPUT ;
    USE SIGNAL ;
    ANTENNAGATEAREA 0.396000 ;
    PORT
      LAYER Metal3 ;
        RECT 852.705 372.960 853.265 373.520 ;
    END
  END data_rdata_i[27]
  PIN data_rdata_i[28]
    DIRECTION INPUT ;
    USE SIGNAL ;
    ANTENNAGATEAREA 0.396000 ;
    PORT
      LAYER Metal3 ;
        RECT 852.705 377.440 853.265 378.000 ;
    END
  END data_rdata_i[28]
  PIN data_rdata_i[29]
    DIRECTION INPUT ;
    USE SIGNAL ;
    ANTENNAGATEAREA 0.396000 ;
    PORT
      LAYER Metal3 ;
        RECT 852.705 400.960 853.265 401.520 ;
    END
  END data_rdata_i[29]
  PIN data_rdata_i[2]
    DIRECTION INPUT ;
    USE SIGNAL ;
    ANTENNAGATEAREA 0.396000 ;
    PORT
      LAYER Metal3 ;
        RECT 852.705 399.840 853.265 400.400 ;
    END
  END data_rdata_i[2]
  PIN data_rdata_i[30]
    DIRECTION INPUT ;
    USE SIGNAL ;
    ANTENNAGATEAREA 0.396000 ;
    PORT
      LAYER Metal3 ;
        RECT 852.705 425.600 853.265 426.160 ;
    END
  END data_rdata_i[30]
  PIN data_rdata_i[31]
    DIRECTION INPUT ;
    USE SIGNAL ;
    ANTENNAGATEAREA 0.396000 ;
    PORT
      LAYER Metal2 ;
        RECT 454.720 870.625 455.280 871.185 ;
    END
  END data_rdata_i[31]
  PIN data_rdata_i[3]
    DIRECTION INPUT ;
    USE SIGNAL ;
    ANTENNAGATEAREA 0.396000 ;
    PORT
      LAYER Metal3 ;
        RECT 852.705 361.760 853.265 362.320 ;
    END
  END data_rdata_i[3]
  PIN data_rdata_i[4]
    DIRECTION INPUT ;
    USE SIGNAL ;
    ANTENNAGATEAREA 0.396000 ;
    PORT
      LAYER Metal3 ;
        RECT 852.705 368.480 853.265 369.040 ;
    END
  END data_rdata_i[4]
  PIN data_rdata_i[5]
    DIRECTION INPUT ;
    USE SIGNAL ;
    ANTENNAGATEAREA 0.396000 ;
    PORT
      LAYER Metal3 ;
        RECT 852.705 404.320 853.265 404.880 ;
    END
  END data_rdata_i[5]
  PIN data_rdata_i[6]
    DIRECTION INPUT ;
    USE SIGNAL ;
    ANTENNAGATEAREA 0.396000 ;
    PORT
      LAYER Metal3 ;
        RECT 852.705 426.720 853.265 427.280 ;
    END
  END data_rdata_i[6]
  PIN data_rdata_i[7]
    DIRECTION INPUT ;
    USE SIGNAL ;
    ANTENNAGATEAREA 0.396000 ;
    PORT
      LAYER Metal2 ;
        RECT 437.920 870.625 438.480 871.185 ;
    END
  END data_rdata_i[7]
  PIN data_rdata_i[8]
    DIRECTION INPUT ;
    USE SIGNAL ;
    ANTENNAGATEAREA 0.396000 ;
    PORT
      LAYER Metal3 ;
        RECT 852.705 337.120 853.265 337.680 ;
    END
  END data_rdata_i[8]
  PIN data_rdata_i[9]
    DIRECTION INPUT ;
    USE SIGNAL ;
    ANTENNAGATEAREA 0.396000 ;
    PORT
      LAYER Metal3 ;
        RECT 852.705 330.400 853.265 330.960 ;
    END
  END data_rdata_i[9]
  PIN data_rdata_intg_i[0]
    DIRECTION INPUT ;
    USE SIGNAL ;
    PORT
      LAYER Metal2 ;
        RECT 16.800 0.000 17.360 0.560 ;
    END
  END data_rdata_intg_i[0]
  PIN data_rdata_intg_i[1]
    DIRECTION INPUT ;
    USE SIGNAL ;
    PORT
      LAYER Metal2 ;
        RECT 14.560 0.000 15.120 0.560 ;
    END
  END data_rdata_intg_i[1]
  PIN data_rdata_intg_i[2]
    DIRECTION INPUT ;
    USE SIGNAL ;
    PORT
      LAYER Metal2 ;
        RECT 13.440 0.000 14.000 0.560 ;
    END
  END data_rdata_intg_i[2]
  PIN data_rdata_intg_i[3]
    DIRECTION INPUT ;
    USE SIGNAL ;
    PORT
      LAYER Metal2 ;
        RECT 20.160 0.000 20.720 0.560 ;
    END
  END data_rdata_intg_i[3]
  PIN data_rdata_intg_i[4]
    DIRECTION INPUT ;
    USE SIGNAL ;
    PORT
      LAYER Metal2 ;
        RECT 15.680 0.000 16.240 0.560 ;
    END
  END data_rdata_intg_i[4]
  PIN data_rdata_intg_i[5]
    DIRECTION INPUT ;
    USE SIGNAL ;
    PORT
      LAYER Metal2 ;
        RECT 19.040 0.000 19.600 0.560 ;
    END
  END data_rdata_intg_i[5]
  PIN data_rdata_intg_i[6]
    DIRECTION INPUT ;
    USE SIGNAL ;
    PORT
      LAYER Metal2 ;
        RECT 17.920 0.000 18.480 0.560 ;
    END
  END data_rdata_intg_i[6]
  PIN data_req_o
    DIRECTION OUTPUT ;
    USE SIGNAL ;
    ANTENNADIFFAREA 0.897600 ;
    PORT
      LAYER Metal3 ;
        RECT 0.000 488.320 0.560 488.880 ;
    END
  END data_req_o
  PIN data_req_shadow_o
    DIRECTION OUTPUT ;
    USE SIGNAL ;
    ANTENNADIFFAREA 0.360800 ;
    PORT
      LAYER Metal3 ;
        RECT 0.000 834.400 0.560 834.960 ;
    END
  END data_req_shadow_o
  PIN data_rvalid_i
    DIRECTION INPUT ;
    USE SIGNAL ;
    ANTENNAGATEAREA 0.396000 ;
    PORT
      LAYER Metal3 ;
        RECT 0.000 492.800 0.560 493.360 ;
    END
  END data_rvalid_i
  PIN data_wdata_intg_o[0]
    DIRECTION OUTPUT ;
    USE SIGNAL ;
    ANTENNADIFFAREA 0.360800 ;
    PORT
      LAYER Metal3 ;
        RECT 852.705 153.440 853.265 154.000 ;
    END
  END data_wdata_intg_o[0]
  PIN data_wdata_intg_o[1]
    DIRECTION OUTPUT ;
    USE SIGNAL ;
    ANTENNADIFFAREA 0.360800 ;
    PORT
      LAYER Metal2 ;
        RECT 843.360 0.000 843.920 0.560 ;
    END
  END data_wdata_intg_o[1]
  PIN data_wdata_intg_o[2]
    DIRECTION OUTPUT ;
    USE SIGNAL ;
    ANTENNADIFFAREA 0.360800 ;
    PORT
      LAYER Metal2 ;
        RECT 778.400 870.625 778.960 871.185 ;
    END
  END data_wdata_intg_o[2]
  PIN data_wdata_intg_o[3]
    DIRECTION OUTPUT ;
    USE SIGNAL ;
    ANTENNADIFFAREA 0.360800 ;
    PORT
      LAYER Metal2 ;
        RECT 740.320 870.625 740.880 871.185 ;
    END
  END data_wdata_intg_o[3]
  PIN data_wdata_intg_o[4]
    DIRECTION OUTPUT ;
    USE SIGNAL ;
    ANTENNADIFFAREA 0.360800 ;
    PORT
      LAYER Metal3 ;
        RECT 852.705 72.800 853.265 73.360 ;
    END
  END data_wdata_intg_o[4]
  PIN data_wdata_intg_o[5]
    DIRECTION OUTPUT ;
    USE SIGNAL ;
    ANTENNADIFFAREA 0.360800 ;
    PORT
      LAYER Metal2 ;
        RECT 743.680 0.000 744.240 0.560 ;
    END
  END data_wdata_intg_o[5]
  PIN data_wdata_intg_o[6]
    DIRECTION OUTPUT ;
    USE SIGNAL ;
    ANTENNADIFFAREA 0.360800 ;
    PORT
      LAYER Metal3 ;
        RECT 0.000 850.080 0.560 850.640 ;
    END
  END data_wdata_intg_o[6]
  PIN data_wdata_intg_shadow_o[0]
    DIRECTION OUTPUT ;
    USE SIGNAL ;
    ANTENNADIFFAREA 0.360800 ;
    PORT
      LAYER Metal3 ;
        RECT 0.000 764.960 0.560 765.520 ;
    END
  END data_wdata_intg_shadow_o[0]
  PIN data_wdata_intg_shadow_o[1]
    DIRECTION OUTPUT ;
    USE SIGNAL ;
    ANTENNADIFFAREA 0.360800 ;
    PORT
      LAYER Metal2 ;
        RECT 780.640 0.000 781.200 0.560 ;
    END
  END data_wdata_intg_shadow_o[1]
  PIN data_wdata_intg_shadow_o[2]
    DIRECTION OUTPUT ;
    USE SIGNAL ;
    ANTENNADIFFAREA 0.360800 ;
    PORT
      LAYER Metal3 ;
        RECT 852.705 138.880 853.265 139.440 ;
    END
  END data_wdata_intg_shadow_o[2]
  PIN data_wdata_intg_shadow_o[3]
    DIRECTION OUTPUT ;
    USE SIGNAL ;
    ANTENNADIFFAREA 0.360800 ;
    PORT
      LAYER Metal3 ;
        RECT 0.000 807.520 0.560 808.080 ;
    END
  END data_wdata_intg_shadow_o[3]
  PIN data_wdata_intg_shadow_o[4]
    DIRECTION OUTPUT ;
    USE SIGNAL ;
    ANTENNADIFFAREA 0.360800 ;
    PORT
      LAYER Metal2 ;
        RECT 81.760 0.000 82.320 0.560 ;
    END
  END data_wdata_intg_shadow_o[4]
  PIN data_wdata_intg_shadow_o[5]
    DIRECTION OUTPUT ;
    USE SIGNAL ;
    ANTENNADIFFAREA 0.360800 ;
    PORT
      LAYER Metal3 ;
        RECT 852.705 125.440 853.265 126.000 ;
    END
  END data_wdata_intg_shadow_o[5]
  PIN data_wdata_intg_shadow_o[6]
    DIRECTION OUTPUT ;
    USE SIGNAL ;
    ANTENNADIFFAREA 0.360800 ;
    PORT
      LAYER Metal3 ;
        RECT 852.705 105.280 853.265 105.840 ;
    END
  END data_wdata_intg_shadow_o[6]
  PIN data_wdata_o[0]
    DIRECTION OUTPUT ;
    USE SIGNAL ;
    ANTENNADIFFAREA 0.897600 ;
    PORT
      LAYER Metal2 ;
        RECT 529.760 0.000 530.320 0.560 ;
    END
  END data_wdata_o[0]
  PIN data_wdata_o[10]
    DIRECTION OUTPUT ;
    USE SIGNAL ;
    ANTENNADIFFAREA 0.897600 ;
    PORT
      LAYER Metal2 ;
        RECT 501.760 0.000 502.320 0.560 ;
    END
  END data_wdata_o[10]
  PIN data_wdata_o[11]
    DIRECTION OUTPUT ;
    USE SIGNAL ;
    ANTENNADIFFAREA 0.897600 ;
    PORT
      LAYER Metal2 ;
        RECT 492.800 0.000 493.360 0.560 ;
    END
  END data_wdata_o[11]
  PIN data_wdata_o[12]
    DIRECTION OUTPUT ;
    USE SIGNAL ;
    ANTENNADIFFAREA 0.897600 ;
    PORT
      LAYER Metal2 ;
        RECT 527.520 0.000 528.080 0.560 ;
    END
  END data_wdata_o[12]
  PIN data_wdata_o[13]
    DIRECTION OUTPUT ;
    USE SIGNAL ;
    ANTENNADIFFAREA 0.897600 ;
    PORT
      LAYER Metal2 ;
        RECT 471.520 0.000 472.080 0.560 ;
    END
  END data_wdata_o[13]
  PIN data_wdata_o[14]
    DIRECTION OUTPUT ;
    USE SIGNAL ;
    ANTENNADIFFAREA 0.897600 ;
    PORT
      LAYER Metal2 ;
        RECT 496.160 0.000 496.720 0.560 ;
    END
  END data_wdata_o[14]
  PIN data_wdata_o[15]
    DIRECTION OUTPUT ;
    USE SIGNAL ;
    ANTENNADIFFAREA 0.897600 ;
    PORT
      LAYER Metal2 ;
        RECT 539.840 0.000 540.400 0.560 ;
    END
  END data_wdata_o[15]
  PIN data_wdata_o[16]
    DIRECTION OUTPUT ;
    USE SIGNAL ;
    ANTENNADIFFAREA 0.897600 ;
    PORT
      LAYER Metal2 ;
        RECT 490.560 0.000 491.120 0.560 ;
    END
  END data_wdata_o[16]
  PIN data_wdata_o[17]
    DIRECTION OUTPUT ;
    USE SIGNAL ;
    ANTENNADIFFAREA 0.897600 ;
    PORT
      LAYER Metal2 ;
        RECT 477.120 0.000 477.680 0.560 ;
    END
  END data_wdata_o[17]
  PIN data_wdata_o[18]
    DIRECTION OUTPUT ;
    USE SIGNAL ;
    ANTENNADIFFAREA 0.897600 ;
    PORT
      LAYER Metal2 ;
        RECT 487.200 0.000 487.760 0.560 ;
    END
  END data_wdata_o[18]
  PIN data_wdata_o[19]
    DIRECTION OUTPUT ;
    USE SIGNAL ;
    ANTENNADIFFAREA 0.897600 ;
    PORT
      LAYER Metal2 ;
        RECT 482.720 0.000 483.280 0.560 ;
    END
  END data_wdata_o[19]
  PIN data_wdata_o[1]
    DIRECTION OUTPUT ;
    USE SIGNAL ;
    ANTENNADIFFAREA 0.897600 ;
    PORT
      LAYER Metal2 ;
        RECT 517.440 0.000 518.000 0.560 ;
    END
  END data_wdata_o[1]
  PIN data_wdata_o[20]
    DIRECTION OUTPUT ;
    USE SIGNAL ;
    ANTENNADIFFAREA 0.897600 ;
    PORT
      LAYER Metal2 ;
        RECT 504.000 0.000 504.560 0.560 ;
    END
  END data_wdata_o[20]
  PIN data_wdata_o[21]
    DIRECTION OUTPUT ;
    USE SIGNAL ;
    ANTENNADIFFAREA 0.897600 ;
    PORT
      LAYER Metal2 ;
        RECT 508.480 0.000 509.040 0.560 ;
    END
  END data_wdata_o[21]
  PIN data_wdata_o[22]
    DIRECTION OUTPUT ;
    USE SIGNAL ;
    ANTENNADIFFAREA 0.897600 ;
    PORT
      LAYER Metal2 ;
        RECT 495.040 0.000 495.600 0.560 ;
    END
  END data_wdata_o[22]
  PIN data_wdata_o[23]
    DIRECTION OUTPUT ;
    USE SIGNAL ;
    ANTENNADIFFAREA 0.897600 ;
    PORT
      LAYER Metal2 ;
        RECT 481.600 0.000 482.160 0.560 ;
    END
  END data_wdata_o[23]
  PIN data_wdata_o[24]
    DIRECTION OUTPUT ;
    USE SIGNAL ;
    ANTENNADIFFAREA 0.897600 ;
    PORT
      LAYER Metal2 ;
        RECT 506.240 0.000 506.800 0.560 ;
    END
  END data_wdata_o[24]
  PIN data_wdata_o[25]
    DIRECTION OUTPUT ;
    USE SIGNAL ;
    ANTENNADIFFAREA 0.897600 ;
    PORT
      LAYER Metal2 ;
        RECT 515.200 0.000 515.760 0.560 ;
    END
  END data_wdata_o[25]
  PIN data_wdata_o[26]
    DIRECTION OUTPUT ;
    USE SIGNAL ;
    ANTENNADIFFAREA 0.897600 ;
    PORT
      LAYER Metal2 ;
        RECT 491.680 0.000 492.240 0.560 ;
    END
  END data_wdata_o[26]
  PIN data_wdata_o[27]
    DIRECTION OUTPUT ;
    USE SIGNAL ;
    ANTENNADIFFAREA 0.897600 ;
    PORT
      LAYER Metal2 ;
        RECT 469.280 0.000 469.840 0.560 ;
    END
  END data_wdata_o[27]
  PIN data_wdata_o[28]
    DIRECTION OUTPUT ;
    USE SIGNAL ;
    ANTENNADIFFAREA 0.897600 ;
    PORT
      LAYER Metal2 ;
        RECT 526.400 0.000 526.960 0.560 ;
    END
  END data_wdata_o[28]
  PIN data_wdata_o[29]
    DIRECTION OUTPUT ;
    USE SIGNAL ;
    ANTENNADIFFAREA 0.897600 ;
    PORT
      LAYER Metal2 ;
        RECT 483.840 0.000 484.400 0.560 ;
    END
  END data_wdata_o[29]
  PIN data_wdata_o[2]
    DIRECTION OUTPUT ;
    USE SIGNAL ;
    ANTENNADIFFAREA 0.897600 ;
    PORT
      LAYER Metal2 ;
        RECT 489.440 0.000 490.000 0.560 ;
    END
  END data_wdata_o[2]
  PIN data_wdata_o[30]
    DIRECTION OUTPUT ;
    USE SIGNAL ;
    ANTENNADIFFAREA 0.897600 ;
    PORT
      LAYER Metal2 ;
        RECT 498.400 0.000 498.960 0.560 ;
    END
  END data_wdata_o[30]
  PIN data_wdata_o[31]
    DIRECTION OUTPUT ;
    USE SIGNAL ;
    ANTENNADIFFAREA 0.897600 ;
    PORT
      LAYER Metal2 ;
        RECT 546.560 0.000 547.120 0.560 ;
    END
  END data_wdata_o[31]
  PIN data_wdata_o[3]
    DIRECTION OUTPUT ;
    USE SIGNAL ;
    ANTENNADIFFAREA 0.897600 ;
    PORT
      LAYER Metal2 ;
        RECT 518.560 0.000 519.120 0.560 ;
    END
  END data_wdata_o[3]
  PIN data_wdata_o[4]
    DIRECTION OUTPUT ;
    USE SIGNAL ;
    ANTENNADIFFAREA 0.897600 ;
    PORT
      LAYER Metal2 ;
        RECT 519.680 0.000 520.240 0.560 ;
    END
  END data_wdata_o[4]
  PIN data_wdata_o[5]
    DIRECTION OUTPUT ;
    USE SIGNAL ;
    ANTENNADIFFAREA 0.897600 ;
    PORT
      LAYER Metal2 ;
        RECT 484.960 0.000 485.520 0.560 ;
    END
  END data_wdata_o[5]
  PIN data_wdata_o[6]
    DIRECTION OUTPUT ;
    USE SIGNAL ;
    ANTENNADIFFAREA 0.897600 ;
    PORT
      LAYER Metal2 ;
        RECT 516.320 0.000 516.880 0.560 ;
    END
  END data_wdata_o[6]
  PIN data_wdata_o[7]
    DIRECTION OUTPUT ;
    USE SIGNAL ;
    ANTENNADIFFAREA 0.897600 ;
    PORT
      LAYER Metal2 ;
        RECT 542.080 0.000 542.640 0.560 ;
    END
  END data_wdata_o[7]
  PIN data_wdata_o[8]
    DIRECTION OUTPUT ;
    USE SIGNAL ;
    ANTENNADIFFAREA 0.897600 ;
    PORT
      LAYER Metal2 ;
        RECT 523.040 0.000 523.600 0.560 ;
    END
  END data_wdata_o[8]
  PIN data_wdata_o[9]
    DIRECTION OUTPUT ;
    USE SIGNAL ;
    ANTENNADIFFAREA 0.897600 ;
    PORT
      LAYER Metal2 ;
        RECT 505.120 0.000 505.680 0.560 ;
    END
  END data_wdata_o[9]
  PIN data_wdata_shadow_o[0]
    DIRECTION OUTPUT ;
    USE SIGNAL ;
    ANTENNADIFFAREA 0.360800 ;
    PORT
      LAYER Metal2 ;
        RECT 799.680 0.000 800.240 0.560 ;
    END
  END data_wdata_shadow_o[0]
  PIN data_wdata_shadow_o[10]
    DIRECTION OUTPUT ;
    USE SIGNAL ;
    ANTENNADIFFAREA 0.360800 ;
    PORT
      LAYER Metal2 ;
        RECT 30.240 0.000 30.800 0.560 ;
    END
  END data_wdata_shadow_o[10]
  PIN data_wdata_shadow_o[11]
    DIRECTION OUTPUT ;
    USE SIGNAL ;
    ANTENNADIFFAREA 0.360800 ;
    PORT
      LAYER Metal2 ;
        RECT 801.920 0.000 802.480 0.560 ;
    END
  END data_wdata_shadow_o[11]
  PIN data_wdata_shadow_o[12]
    DIRECTION OUTPUT ;
    USE SIGNAL ;
    ANTENNADIFFAREA 0.360800 ;
    PORT
      LAYER Metal2 ;
        RECT 667.520 870.625 668.080 871.185 ;
    END
  END data_wdata_shadow_o[12]
  PIN data_wdata_shadow_o[13]
    DIRECTION OUTPUT ;
    USE SIGNAL ;
    ANTENNADIFFAREA 0.360800 ;
    PORT
      LAYER Metal2 ;
        RECT 717.920 870.625 718.480 871.185 ;
    END
  END data_wdata_shadow_o[13]
  PIN data_wdata_shadow_o[14]
    DIRECTION OUTPUT ;
    USE SIGNAL ;
    ANTENNADIFFAREA 0.360800 ;
    PORT
      LAYER Metal2 ;
        RECT 754.880 870.625 755.440 871.185 ;
    END
  END data_wdata_shadow_o[14]
  PIN data_wdata_shadow_o[15]
    DIRECTION OUTPUT ;
    USE SIGNAL ;
    ANTENNADIFFAREA 0.360800 ;
    PORT
      LAYER Metal3 ;
        RECT 852.705 490.560 853.265 491.120 ;
    END
  END data_wdata_shadow_o[15]
  PIN data_wdata_shadow_o[16]
    DIRECTION OUTPUT ;
    USE SIGNAL ;
    ANTENNADIFFAREA 0.360800 ;
    PORT
      LAYER Metal3 ;
        RECT 852.705 848.960 853.265 849.520 ;
    END
  END data_wdata_shadow_o[16]
  PIN data_wdata_shadow_o[17]
    DIRECTION OUTPUT ;
    USE SIGNAL ;
    ANTENNADIFFAREA 0.360800 ;
    PORT
      LAYER Metal3 ;
        RECT 0.000 790.720 0.560 791.280 ;
    END
  END data_wdata_shadow_o[17]
  PIN data_wdata_shadow_o[18]
    DIRECTION OUTPUT ;
    USE SIGNAL ;
    ANTENNADIFFAREA 0.360800 ;
    PORT
      LAYER Metal3 ;
        RECT 0.000 779.520 0.560 780.080 ;
    END
  END data_wdata_shadow_o[18]
  PIN data_wdata_shadow_o[19]
    DIRECTION OUTPUT ;
    USE SIGNAL ;
    ANTENNADIFFAREA 0.360800 ;
    PORT
      LAYER Metal3 ;
        RECT 0.000 818.720 0.560 819.280 ;
    END
  END data_wdata_shadow_o[19]
  PIN data_wdata_shadow_o[1]
    DIRECTION OUTPUT ;
    USE SIGNAL ;
    ANTENNADIFFAREA 0.360800 ;
    PORT
      LAYER Metal3 ;
        RECT 852.705 815.360 853.265 815.920 ;
    END
  END data_wdata_shadow_o[1]
  PIN data_wdata_shadow_o[20]
    DIRECTION OUTPUT ;
    USE SIGNAL ;
    ANTENNADIFFAREA 0.360800 ;
    PORT
      LAYER Metal2 ;
        RECT 787.360 0.000 787.920 0.560 ;
    END
  END data_wdata_shadow_o[20]
  PIN data_wdata_shadow_o[21]
    DIRECTION OUTPUT ;
    USE SIGNAL ;
    ANTENNADIFFAREA 0.360800 ;
    PORT
      LAYER Metal3 ;
        RECT 852.705 116.480 853.265 117.040 ;
    END
  END data_wdata_shadow_o[21]
  PIN data_wdata_shadow_o[22]
    DIRECTION OUTPUT ;
    USE SIGNAL ;
    ANTENNADIFFAREA 0.360800 ;
    PORT
      LAYER Metal3 ;
        RECT 0.000 787.360 0.560 787.920 ;
    END
  END data_wdata_shadow_o[22]
  PIN data_wdata_shadow_o[23]
    DIRECTION OUTPUT ;
    USE SIGNAL ;
    ANTENNADIFFAREA 0.360800 ;
    PORT
      LAYER Metal3 ;
        RECT 0.000 805.280 0.560 805.840 ;
    END
  END data_wdata_shadow_o[23]
  PIN data_wdata_shadow_o[24]
    DIRECTION OUTPUT ;
    USE SIGNAL ;
    ANTENNADIFFAREA 0.360800 ;
    PORT
      LAYER Metal2 ;
        RECT 80.640 870.625 81.200 871.185 ;
    END
  END data_wdata_shadow_o[24]
  PIN data_wdata_shadow_o[25]
    DIRECTION OUTPUT ;
    USE SIGNAL ;
    ANTENNADIFFAREA 0.360800 ;
    PORT
      LAYER Metal2 ;
        RECT 684.320 870.625 684.880 871.185 ;
    END
  END data_wdata_shadow_o[25]
  PIN data_wdata_shadow_o[26]
    DIRECTION OUTPUT ;
    USE SIGNAL ;
    ANTENNADIFFAREA 0.360800 ;
    PORT
      LAYER Metal3 ;
        RECT 0.000 17.920 0.560 18.480 ;
    END
  END data_wdata_shadow_o[26]
  PIN data_wdata_shadow_o[27]
    DIRECTION OUTPUT ;
    USE SIGNAL ;
    ANTENNADIFFAREA 0.360800 ;
    PORT
      LAYER Metal3 ;
        RECT 0.000 812.000 0.560 812.560 ;
    END
  END data_wdata_shadow_o[27]
  PIN data_wdata_shadow_o[28]
    DIRECTION OUTPUT ;
    USE SIGNAL ;
    ANTENNADIFFAREA 0.360800 ;
    PORT
      LAYER Metal2 ;
        RECT 725.760 870.625 726.320 871.185 ;
    END
  END data_wdata_shadow_o[28]
  PIN data_wdata_shadow_o[29]
    DIRECTION OUTPUT ;
    USE SIGNAL ;
    ANTENNADIFFAREA 0.360800 ;
    PORT
      LAYER Metal2 ;
        RECT 770.560 870.625 771.120 871.185 ;
    END
  END data_wdata_shadow_o[29]
  PIN data_wdata_shadow_o[2]
    DIRECTION OUTPUT ;
    USE SIGNAL ;
    ANTENNADIFFAREA 0.360800 ;
    PORT
      LAYER Metal3 ;
        RECT 852.705 94.080 853.265 94.640 ;
    END
  END data_wdata_shadow_o[2]
  PIN data_wdata_shadow_o[30]
    DIRECTION OUTPUT ;
    USE SIGNAL ;
    ANTENNADIFFAREA 0.360800 ;
    PORT
      LAYER Metal2 ;
        RECT 43.680 870.625 44.240 871.185 ;
    END
  END data_wdata_shadow_o[30]
  PIN data_wdata_shadow_o[31]
    DIRECTION OUTPUT ;
    USE SIGNAL ;
    ANTENNADIFFAREA 0.360800 ;
    PORT
      LAYER Metal3 ;
        RECT 0.000 778.400 0.560 778.960 ;
    END
  END data_wdata_shadow_o[31]
  PIN data_wdata_shadow_o[3]
    DIRECTION OUTPUT ;
    USE SIGNAL ;
    ANTENNADIFFAREA 0.360800 ;
    PORT
      LAYER Metal2 ;
        RECT 841.120 0.000 841.680 0.560 ;
    END
  END data_wdata_shadow_o[3]
  PIN data_wdata_shadow_o[4]
    DIRECTION OUTPUT ;
    USE SIGNAL ;
    ANTENNADIFFAREA 0.360800 ;
    PORT
      LAYER Metal3 ;
        RECT 852.705 56.000 853.265 56.560 ;
    END
  END data_wdata_shadow_o[4]
  PIN data_wdata_shadow_o[5]
    DIRECTION OUTPUT ;
    USE SIGNAL ;
    ANTENNADIFFAREA 0.360800 ;
    PORT
      LAYER Metal3 ;
        RECT 0.000 819.840 0.560 820.400 ;
    END
  END data_wdata_shadow_o[5]
  PIN data_wdata_shadow_o[6]
    DIRECTION OUTPUT ;
    USE SIGNAL ;
    ANTENNADIFFAREA 0.360800 ;
    PORT
      LAYER Metal3 ;
        RECT 852.705 60.480 853.265 61.040 ;
    END
  END data_wdata_shadow_o[6]
  PIN data_wdata_shadow_o[7]
    DIRECTION OUTPUT ;
    USE SIGNAL ;
    ANTENNADIFFAREA 0.360800 ;
    PORT
      LAYER Metal2 ;
        RECT 803.040 0.000 803.600 0.560 ;
    END
  END data_wdata_shadow_o[7]
  PIN data_wdata_shadow_o[8]
    DIRECTION OUTPUT ;
    USE SIGNAL ;
    ANTENNADIFFAREA 0.360800 ;
    PORT
      LAYER Metal3 ;
        RECT 852.705 759.360 853.265 759.920 ;
    END
  END data_wdata_shadow_o[8]
  PIN data_wdata_shadow_o[9]
    DIRECTION OUTPUT ;
    USE SIGNAL ;
    ANTENNADIFFAREA 0.360800 ;
    PORT
      LAYER Metal2 ;
        RECT 108.640 0.000 109.200 0.560 ;
    END
  END data_wdata_shadow_o[9]
  PIN data_we_o
    DIRECTION OUTPUT ;
    USE SIGNAL ;
    ANTENNADIFFAREA 0.897600 ;
    PORT
      LAYER Metal3 ;
        RECT 0.000 524.160 0.560 524.720 ;
    END
  END data_we_o
  PIN data_we_shadow_o
    DIRECTION OUTPUT ;
    USE SIGNAL ;
    ANTENNADIFFAREA 0.360800 ;
    PORT
      LAYER Metal3 ;
        RECT 0.000 796.320 0.560 796.880 ;
    END
  END data_we_shadow_o
  PIN debug_req_i
    DIRECTION INPUT ;
    USE SIGNAL ;
    ANTENNAGATEAREA 0.396000 ;
    PORT
      LAYER Metal2 ;
        RECT 294.560 870.625 295.120 871.185 ;
    END
  END debug_req_i
  PIN double_fault_seen_o
    DIRECTION OUTPUT ;
    USE SIGNAL ;
    ANTENNADIFFAREA 0.897600 ;
    PORT
      LAYER Metal2 ;
        RECT 372.960 870.625 373.520 871.185 ;
    END
  END double_fault_seen_o
  PIN fetch_enable_i[0]
    DIRECTION INPUT ;
    USE SIGNAL ;
    ANTENNAGATEAREA 0.396000 ;
    PORT
      LAYER Metal2 ;
        RECT 274.400 870.625 274.960 871.185 ;
    END
  END fetch_enable_i[0]
  PIN fetch_enable_i[1]
    DIRECTION INPUT ;
    USE SIGNAL ;
    PORT
      LAYER Metal2 ;
        RECT 21.280 0.000 21.840 0.560 ;
    END
  END fetch_enable_i[1]
  PIN fetch_enable_i[2]
    DIRECTION INPUT ;
    USE SIGNAL ;
    PORT
      LAYER Metal2 ;
        RECT 25.760 0.000 26.320 0.560 ;
    END
  END fetch_enable_i[2]
  PIN fetch_enable_i[3]
    DIRECTION INPUT ;
    USE SIGNAL ;
    PORT
      LAYER Metal2 ;
        RECT 23.520 0.000 24.080 0.560 ;
    END
  END fetch_enable_i[3]
  PIN hart_id_i[0]
    DIRECTION INPUT ;
    USE SIGNAL ;
    ANTENNAGATEAREA 0.396000 ;
    PORT
      LAYER Metal2 ;
        RECT 356.160 870.625 356.720 871.185 ;
    END
  END hart_id_i[0]
  PIN hart_id_i[10]
    DIRECTION INPUT ;
    USE SIGNAL ;
    ANTENNAGATEAREA 0.396000 ;
    PORT
      LAYER Metal2 ;
        RECT 673.120 870.625 673.680 871.185 ;
    END
  END hart_id_i[10]
  PIN hart_id_i[11]
    DIRECTION INPUT ;
    USE SIGNAL ;
    ANTENNAGATEAREA 0.396000 ;
    PORT
      LAYER Metal2 ;
        RECT 492.800 870.625 493.360 871.185 ;
    END
  END hart_id_i[11]
  PIN hart_id_i[12]
    DIRECTION INPUT ;
    USE SIGNAL ;
    ANTENNAGATEAREA 0.396000 ;
    PORT
      LAYER Metal2 ;
        RECT 530.880 870.625 531.440 871.185 ;
    END
  END hart_id_i[12]
  PIN hart_id_i[13]
    DIRECTION INPUT ;
    USE SIGNAL ;
    ANTENNAGATEAREA 0.396000 ;
    PORT
      LAYER Metal2 ;
        RECT 555.520 870.625 556.080 871.185 ;
    END
  END hart_id_i[13]
  PIN hart_id_i[14]
    DIRECTION INPUT ;
    USE SIGNAL ;
    ANTENNAGATEAREA 0.396000 ;
    PORT
      LAYER Metal2 ;
        RECT 635.040 870.625 635.600 871.185 ;
    END
  END hart_id_i[14]
  PIN hart_id_i[15]
    DIRECTION INPUT ;
    USE SIGNAL ;
    ANTENNAGATEAREA 0.396000 ;
    PORT
      LAYER Metal2 ;
        RECT 532.000 870.625 532.560 871.185 ;
    END
  END hart_id_i[15]
  PIN hart_id_i[16]
    DIRECTION INPUT ;
    USE SIGNAL ;
    ANTENNAGATEAREA 0.396000 ;
    PORT
      LAYER Metal2 ;
        RECT 584.640 870.625 585.200 871.185 ;
    END
  END hart_id_i[16]
  PIN hart_id_i[17]
    DIRECTION INPUT ;
    USE SIGNAL ;
    ANTENNAGATEAREA 0.396000 ;
    PORT
      LAYER Metal2 ;
        RECT 585.760 870.625 586.320 871.185 ;
    END
  END hart_id_i[17]
  PIN hart_id_i[18]
    DIRECTION INPUT ;
    USE SIGNAL ;
    ANTENNAGATEAREA 0.396000 ;
    PORT
      LAYER Metal2 ;
        RECT 672.000 870.625 672.560 871.185 ;
    END
  END hart_id_i[18]
  PIN hart_id_i[19]
    DIRECTION INPUT ;
    USE SIGNAL ;
    ANTENNAGATEAREA 0.396000 ;
    PORT
      LAYER Metal2 ;
        RECT 674.240 870.625 674.800 871.185 ;
    END
  END hart_id_i[19]
  PIN hart_id_i[1]
    DIRECTION INPUT ;
    USE SIGNAL ;
    ANTENNAGATEAREA 0.396000 ;
    PORT
      LAYER Metal2 ;
        RECT 377.440 870.625 378.000 871.185 ;
    END
  END hart_id_i[1]
  PIN hart_id_i[20]
    DIRECTION INPUT ;
    USE SIGNAL ;
    ANTENNAGATEAREA 0.396000 ;
    PORT
      LAYER Metal2 ;
        RECT 675.360 870.625 675.920 871.185 ;
    END
  END hart_id_i[20]
  PIN hart_id_i[21]
    DIRECTION INPUT ;
    USE SIGNAL ;
    ANTENNAGATEAREA 0.396000 ;
    PORT
      LAYER Metal2 ;
        RECT 579.040 870.625 579.600 871.185 ;
    END
  END hart_id_i[21]
  PIN hart_id_i[22]
    DIRECTION INPUT ;
    USE SIGNAL ;
    ANTENNAGATEAREA 0.396000 ;
    PORT
      LAYER Metal2 ;
        RECT 676.480 870.625 677.040 871.185 ;
    END
  END hart_id_i[22]
  PIN hart_id_i[23]
    DIRECTION INPUT ;
    USE SIGNAL ;
    ANTENNAGATEAREA 0.396000 ;
    PORT
      LAYER Metal3 ;
        RECT 852.705 595.840 853.265 596.400 ;
    END
  END hart_id_i[23]
  PIN hart_id_i[24]
    DIRECTION INPUT ;
    USE SIGNAL ;
    ANTENNAGATEAREA 0.396000 ;
    PORT
      LAYER Metal2 ;
        RECT 633.920 870.625 634.480 871.185 ;
    END
  END hart_id_i[24]
  PIN hart_id_i[25]
    DIRECTION INPUT ;
    USE SIGNAL ;
    ANTENNAGATEAREA 0.396000 ;
    PORT
      LAYER Metal2 ;
        RECT 529.760 870.625 530.320 871.185 ;
    END
  END hart_id_i[25]
  PIN hart_id_i[26]
    DIRECTION INPUT ;
    USE SIGNAL ;
    ANTENNAGATEAREA 0.396000 ;
    PORT
      LAYER Metal2 ;
        RECT 455.840 870.625 456.400 871.185 ;
    END
  END hart_id_i[26]
  PIN hart_id_i[27]
    DIRECTION INPUT ;
    USE SIGNAL ;
    ANTENNAGATEAREA 0.396000 ;
    PORT
      LAYER Metal3 ;
        RECT 852.705 611.520 853.265 612.080 ;
    END
  END hart_id_i[27]
  PIN hart_id_i[28]
    DIRECTION INPUT ;
    USE SIGNAL ;
    ANTENNAGATEAREA 0.396000 ;
    PORT
      LAYER Metal2 ;
        RECT 636.160 870.625 636.720 871.185 ;
    END
  END hart_id_i[28]
  PIN hart_id_i[29]
    DIRECTION INPUT ;
    USE SIGNAL ;
    ANTENNAGATEAREA 0.396000 ;
    PORT
      LAYER Metal2 ;
        RECT 501.760 870.625 502.320 871.185 ;
    END
  END hart_id_i[29]
  PIN hart_id_i[2]
    DIRECTION INPUT ;
    USE SIGNAL ;
    ANTENNAGATEAREA 0.396000 ;
    PORT
      LAYER Metal2 ;
        RECT 386.400 870.625 386.960 871.185 ;
    END
  END hart_id_i[2]
  PIN hart_id_i[30]
    DIRECTION INPUT ;
    USE SIGNAL ;
    ANTENNAGATEAREA 0.396000 ;
    PORT
      LAYER Metal2 ;
        RECT 509.600 870.625 510.160 871.185 ;
    END
  END hart_id_i[30]
  PIN hart_id_i[31]
    DIRECTION INPUT ;
    USE SIGNAL ;
    ANTENNAGATEAREA 0.396000 ;
    PORT
      LAYER Metal2 ;
        RECT 425.600 870.625 426.160 871.185 ;
    END
  END hart_id_i[31]
  PIN hart_id_i[3]
    DIRECTION INPUT ;
    USE SIGNAL ;
    ANTENNAGATEAREA 0.396000 ;
    PORT
      LAYER Metal2 ;
        RECT 441.280 870.625 441.840 871.185 ;
    END
  END hart_id_i[3]
  PIN hart_id_i[4]
    DIRECTION INPUT ;
    USE SIGNAL ;
    ANTENNAGATEAREA 0.396000 ;
    PORT
      LAYER Metal2 ;
        RECT 389.760 870.625 390.320 871.185 ;
    END
  END hart_id_i[4]
  PIN hart_id_i[5]
    DIRECTION INPUT ;
    USE SIGNAL ;
    ANTENNAGATEAREA 0.396000 ;
    PORT
      LAYER Metal2 ;
        RECT 421.120 870.625 421.680 871.185 ;
    END
  END hart_id_i[5]
  PIN hart_id_i[6]
    DIRECTION INPUT ;
    USE SIGNAL ;
    ANTENNAGATEAREA 0.396000 ;
    PORT
      LAYER Metal2 ;
        RECT 442.400 870.625 442.960 871.185 ;
    END
  END hart_id_i[6]
  PIN hart_id_i[7]
    DIRECTION INPUT ;
    USE SIGNAL ;
    ANTENNAGATEAREA 0.396000 ;
    PORT
      LAYER Metal2 ;
        RECT 446.880 870.625 447.440 871.185 ;
    END
  END hart_id_i[7]
  PIN hart_id_i[8]
    DIRECTION INPUT ;
    USE SIGNAL ;
    ANTENNAGATEAREA 0.396000 ;
    PORT
      LAYER Metal2 ;
        RECT 450.240 870.625 450.800 871.185 ;
    END
  END hart_id_i[8]
  PIN hart_id_i[9]
    DIRECTION INPUT ;
    USE SIGNAL ;
    ANTENNAGATEAREA 0.396000 ;
    PORT
      LAYER Metal2 ;
        RECT 474.880 870.625 475.440 871.185 ;
    END
  END hart_id_i[9]
  PIN instr_addr_o[0]
    DIRECTION OUTPUT ;
    USE SIGNAL ;
    ANTENNADIFFAREA 0.360800 ;
    PORT
      LAYER Metal3 ;
        RECT 0.000 832.160 0.560 832.720 ;
    END
  END instr_addr_o[0]
  PIN instr_addr_o[10]
    DIRECTION OUTPUT ;
    USE SIGNAL ;
    ANTENNADIFFAREA 0.897600 ;
    PORT
      LAYER Metal2 ;
        RECT 464.800 870.625 465.360 871.185 ;
    END
  END instr_addr_o[10]
  PIN instr_addr_o[11]
    DIRECTION OUTPUT ;
    USE SIGNAL ;
    ANTENNADIFFAREA 0.897600 ;
    PORT
      LAYER Metal2 ;
        RECT 508.480 870.625 509.040 871.185 ;
    END
  END instr_addr_o[11]
  PIN instr_addr_o[12]
    DIRECTION OUTPUT ;
    USE SIGNAL ;
    ANTENNADIFFAREA 0.897600 ;
    PORT
      LAYER Metal2 ;
        RECT 487.200 870.625 487.760 871.185 ;
    END
  END instr_addr_o[12]
  PIN instr_addr_o[13]
    DIRECTION OUTPUT ;
    USE SIGNAL ;
    ANTENNADIFFAREA 0.897600 ;
    PORT
      LAYER Metal2 ;
        RECT 524.160 870.625 524.720 871.185 ;
    END
  END instr_addr_o[13]
  PIN instr_addr_o[14]
    DIRECTION OUTPUT ;
    USE SIGNAL ;
    ANTENNADIFFAREA 0.897600 ;
    PORT
      LAYER Metal2 ;
        RECT 558.880 870.625 559.440 871.185 ;
    END
  END instr_addr_o[14]
  PIN instr_addr_o[15]
    DIRECTION OUTPUT ;
    USE SIGNAL ;
    ANTENNADIFFAREA 0.897600 ;
    PORT
      LAYER Metal2 ;
        RECT 545.440 870.625 546.000 871.185 ;
    END
  END instr_addr_o[15]
  PIN instr_addr_o[16]
    DIRECTION OUTPUT ;
    USE SIGNAL ;
    ANTENNADIFFAREA 0.897600 ;
    PORT
      LAYER Metal2 ;
        RECT 573.440 870.625 574.000 871.185 ;
    END
  END instr_addr_o[16]
  PIN instr_addr_o[17]
    DIRECTION OUTPUT ;
    USE SIGNAL ;
    ANTENNADIFFAREA 0.897600 ;
    PORT
      LAYER Metal2 ;
        RECT 586.880 870.625 587.440 871.185 ;
    END
  END instr_addr_o[17]
  PIN instr_addr_o[18]
    DIRECTION OUTPUT ;
    USE SIGNAL ;
    ANTENNADIFFAREA 0.897600 ;
    PORT
      LAYER Metal2 ;
        RECT 601.440 870.625 602.000 871.185 ;
    END
  END instr_addr_o[18]
  PIN instr_addr_o[19]
    DIRECTION OUTPUT ;
    USE SIGNAL ;
    ANTENNADIFFAREA 0.897600 ;
    PORT
      LAYER Metal2 ;
        RECT 637.280 870.625 637.840 871.185 ;
    END
  END instr_addr_o[19]
  PIN instr_addr_o[1]
    DIRECTION OUTPUT ;
    USE SIGNAL ;
    ANTENNADIFFAREA 0.360800 ;
    PORT
      LAYER Metal3 ;
        RECT 852.705 79.520 853.265 80.080 ;
    END
  END instr_addr_o[1]
  PIN instr_addr_o[20]
    DIRECTION OUTPUT ;
    USE SIGNAL ;
    ANTENNADIFFAREA 0.897600 ;
    PORT
      LAYER Metal2 ;
        RECT 632.800 870.625 633.360 871.185 ;
    END
  END instr_addr_o[20]
  PIN instr_addr_o[21]
    DIRECTION OUTPUT ;
    USE SIGNAL ;
    ANTENNADIFFAREA 0.897600 ;
    PORT
      LAYER Metal2 ;
        RECT 614.880 870.625 615.440 871.185 ;
    END
  END instr_addr_o[21]
  PIN instr_addr_o[22]
    DIRECTION OUTPUT ;
    USE SIGNAL ;
    ANTENNADIFFAREA 0.897600 ;
    PORT
      LAYER Metal2 ;
        RECT 624.960 870.625 625.520 871.185 ;
    END
  END instr_addr_o[22]
  PIN instr_addr_o[23]
    DIRECTION OUTPUT ;
    USE SIGNAL ;
    ANTENNADIFFAREA 0.897600 ;
    PORT
      LAYER Metal2 ;
        RECT 610.400 870.625 610.960 871.185 ;
    END
  END instr_addr_o[23]
  PIN instr_addr_o[24]
    DIRECTION OUTPUT ;
    USE SIGNAL ;
    ANTENNADIFFAREA 0.897600 ;
    PORT
      LAYER Metal2 ;
        RECT 264.320 870.625 264.880 871.185 ;
    END
  END instr_addr_o[24]
  PIN instr_addr_o[25]
    DIRECTION OUTPUT ;
    USE SIGNAL ;
    ANTENNADIFFAREA 0.897600 ;
    PORT
      LAYER Metal2 ;
        RECT 269.920 870.625 270.480 871.185 ;
    END
  END instr_addr_o[25]
  PIN instr_addr_o[26]
    DIRECTION OUTPUT ;
    USE SIGNAL ;
    ANTENNADIFFAREA 0.897600 ;
    PORT
      LAYER Metal2 ;
        RECT 265.440 870.625 266.000 871.185 ;
    END
  END instr_addr_o[26]
  PIN instr_addr_o[27]
    DIRECTION OUTPUT ;
    USE SIGNAL ;
    ANTENNADIFFAREA 0.897600 ;
    PORT
      LAYER Metal2 ;
        RECT 275.520 870.625 276.080 871.185 ;
    END
  END instr_addr_o[27]
  PIN instr_addr_o[28]
    DIRECTION OUTPUT ;
    USE SIGNAL ;
    ANTENNADIFFAREA 0.897600 ;
    PORT
      LAYER Metal2 ;
        RECT 278.880 870.625 279.440 871.185 ;
    END
  END instr_addr_o[28]
  PIN instr_addr_o[29]
    DIRECTION OUTPUT ;
    USE SIGNAL ;
    ANTENNADIFFAREA 0.897600 ;
    PORT
      LAYER Metal2 ;
        RECT 286.720 870.625 287.280 871.185 ;
    END
  END instr_addr_o[29]
  PIN instr_addr_o[2]
    DIRECTION OUTPUT ;
    USE SIGNAL ;
    ANTENNADIFFAREA 0.897600 ;
    PORT
      LAYER Metal2 ;
        RECT 302.400 870.625 302.960 871.185 ;
    END
  END instr_addr_o[2]
  PIN instr_addr_o[30]
    DIRECTION OUTPUT ;
    USE SIGNAL ;
    ANTENNADIFFAREA 0.897600 ;
    PORT
      LAYER Metal2 ;
        RECT 293.440 870.625 294.000 871.185 ;
    END
  END instr_addr_o[30]
  PIN instr_addr_o[31]
    DIRECTION OUTPUT ;
    USE SIGNAL ;
    ANTENNADIFFAREA 0.897600 ;
    PORT
      LAYER Metal2 ;
        RECT 305.760 870.625 306.320 871.185 ;
    END
  END instr_addr_o[31]
  PIN instr_addr_o[3]
    DIRECTION OUTPUT ;
    USE SIGNAL ;
    ANTENNADIFFAREA 0.897600 ;
    PORT
      LAYER Metal2 ;
        RECT 292.320 870.625 292.880 871.185 ;
    END
  END instr_addr_o[3]
  PIN instr_addr_o[4]
    DIRECTION OUTPUT ;
    USE SIGNAL ;
    ANTENNADIFFAREA 0.897600 ;
    PORT
      LAYER Metal2 ;
        RECT 322.560 870.625 323.120 871.185 ;
    END
  END instr_addr_o[4]
  PIN instr_addr_o[5]
    DIRECTION OUTPUT ;
    USE SIGNAL ;
    ANTENNADIFFAREA 0.897600 ;
    PORT
      LAYER Metal2 ;
        RECT 357.280 870.625 357.840 871.185 ;
    END
  END instr_addr_o[5]
  PIN instr_addr_o[6]
    DIRECTION OUTPUT ;
    USE SIGNAL ;
    ANTENNADIFFAREA 0.897600 ;
    PORT
      LAYER Metal2 ;
        RECT 375.200 870.625 375.760 871.185 ;
    END
  END instr_addr_o[6]
  PIN instr_addr_o[7]
    DIRECTION OUTPUT ;
    USE SIGNAL ;
    ANTENNADIFFAREA 0.897600 ;
    PORT
      LAYER Metal2 ;
        RECT 395.360 870.625 395.920 871.185 ;
    END
  END instr_addr_o[7]
  PIN instr_addr_o[8]
    DIRECTION OUTPUT ;
    USE SIGNAL ;
    ANTENNADIFFAREA 0.897600 ;
    PORT
      LAYER Metal2 ;
        RECT 424.480 870.625 425.040 871.185 ;
    END
  END instr_addr_o[8]
  PIN instr_addr_o[9]
    DIRECTION OUTPUT ;
    USE SIGNAL ;
    ANTENNADIFFAREA 0.897600 ;
    PORT
      LAYER Metal2 ;
        RECT 444.640 870.625 445.200 871.185 ;
    END
  END instr_addr_o[9]
  PIN instr_addr_shadow_o[0]
    DIRECTION OUTPUT ;
    USE SIGNAL ;
    ANTENNADIFFAREA 0.360800 ;
    PORT
      LAYER Metal3 ;
        RECT 852.705 73.920 853.265 74.480 ;
    END
  END instr_addr_shadow_o[0]
  PIN instr_addr_shadow_o[10]
    DIRECTION OUTPUT ;
    USE SIGNAL ;
    ANTENNADIFFAREA 0.360800 ;
    PORT
      LAYER Metal3 ;
        RECT 0.000 797.440 0.560 798.000 ;
    END
  END instr_addr_shadow_o[10]
  PIN instr_addr_shadow_o[11]
    DIRECTION OUTPUT ;
    USE SIGNAL ;
    ANTENNADIFFAREA 0.360800 ;
    PORT
      LAYER Metal3 ;
        RECT 852.705 847.840 853.265 848.400 ;
    END
  END instr_addr_shadow_o[11]
  PIN instr_addr_shadow_o[12]
    DIRECTION OUTPUT ;
    USE SIGNAL ;
    ANTENNADIFFAREA 0.360800 ;
    PORT
      LAYER Metal3 ;
        RECT 0.000 848.960 0.560 849.520 ;
    END
  END instr_addr_shadow_o[12]
  PIN instr_addr_shadow_o[13]
    DIRECTION OUTPUT ;
    USE SIGNAL ;
    ANTENNADIFFAREA 0.360800 ;
    PORT
      LAYER Metal2 ;
        RECT 800.800 0.000 801.360 0.560 ;
    END
  END instr_addr_shadow_o[13]
  PIN instr_addr_shadow_o[14]
    DIRECTION OUTPUT ;
    USE SIGNAL ;
    ANTENNADIFFAREA 0.360800 ;
    PORT
      LAYER Metal2 ;
        RECT 58.240 870.625 58.800 871.185 ;
    END
  END instr_addr_shadow_o[14]
  PIN instr_addr_shadow_o[15]
    DIRECTION OUTPUT ;
    USE SIGNAL ;
    ANTENNADIFFAREA 0.360800 ;
    PORT
      LAYER Metal2 ;
        RECT 679.840 870.625 680.400 871.185 ;
    END
  END instr_addr_shadow_o[15]
  PIN instr_addr_shadow_o[16]
    DIRECTION OUTPUT ;
    USE SIGNAL ;
    ANTENNADIFFAREA 0.360800 ;
    PORT
      LAYER Metal2 ;
        RECT 752.640 870.625 753.200 871.185 ;
    END
  END instr_addr_shadow_o[16]
  PIN instr_addr_shadow_o[17]
    DIRECTION OUTPUT ;
    USE SIGNAL ;
    ANTENNADIFFAREA 0.360800 ;
    PORT
      LAYER Metal3 ;
        RECT 0.000 745.920 0.560 746.480 ;
    END
  END instr_addr_shadow_o[17]
  PIN instr_addr_shadow_o[18]
    DIRECTION OUTPUT ;
    USE SIGNAL ;
    ANTENNADIFFAREA 0.360800 ;
    PORT
      LAYER Metal2 ;
        RECT 22.400 870.625 22.960 871.185 ;
    END
  END instr_addr_shadow_o[18]
  PIN instr_addr_shadow_o[19]
    DIRECTION OUTPUT ;
    USE SIGNAL ;
    ANTENNADIFFAREA 0.360800 ;
    PORT
      LAYER Metal2 ;
        RECT 788.480 870.625 789.040 871.185 ;
    END
  END instr_addr_shadow_o[19]
  PIN instr_addr_shadow_o[1]
    DIRECTION OUTPUT ;
    USE SIGNAL ;
    ANTENNADIFFAREA 0.360800 ;
    PORT
      LAYER Metal2 ;
        RECT 720.160 870.625 720.720 871.185 ;
    END
  END instr_addr_shadow_o[1]
  PIN instr_addr_shadow_o[20]
    DIRECTION OUTPUT ;
    USE SIGNAL ;
    ANTENNADIFFAREA 0.360800 ;
    PORT
      LAYER Metal3 ;
        RECT 0.000 845.600 0.560 846.160 ;
    END
  END instr_addr_shadow_o[20]
  PIN instr_addr_shadow_o[21]
    DIRECTION OUTPUT ;
    USE SIGNAL ;
    ANTENNADIFFAREA 0.360800 ;
    PORT
      LAYER Metal3 ;
        RECT 852.705 69.440 853.265 70.000 ;
    END
  END instr_addr_shadow_o[21]
  PIN instr_addr_shadow_o[22]
    DIRECTION OUTPUT ;
    USE SIGNAL ;
    ANTENNADIFFAREA 0.360800 ;
    PORT
      LAYER Metal3 ;
        RECT 0.000 19.040 0.560 19.600 ;
    END
  END instr_addr_shadow_o[22]
  PIN instr_addr_shadow_o[23]
    DIRECTION OUTPUT ;
    USE SIGNAL ;
    ANTENNADIFFAREA 0.360800 ;
    PORT
      LAYER Metal3 ;
        RECT 0.000 823.200 0.560 823.760 ;
    END
  END instr_addr_shadow_o[23]
  PIN instr_addr_shadow_o[24]
    DIRECTION OUTPUT ;
    USE SIGNAL ;
    ANTENNADIFFAREA 0.360800 ;
    PORT
      LAYER Metal2 ;
        RECT 795.200 870.625 795.760 871.185 ;
    END
  END instr_addr_shadow_o[24]
  PIN instr_addr_shadow_o[25]
    DIRECTION OUTPUT ;
    USE SIGNAL ;
    ANTENNADIFFAREA 0.360800 ;
    PORT
      LAYER Metal2 ;
        RECT 814.240 0.000 814.800 0.560 ;
    END
  END instr_addr_shadow_o[25]
  PIN instr_addr_shadow_o[26]
    DIRECTION OUTPUT ;
    USE SIGNAL ;
    ANTENNADIFFAREA 0.360800 ;
    PORT
      LAYER Metal2 ;
        RECT 773.920 0.000 774.480 0.560 ;
    END
  END instr_addr_shadow_o[26]
  PIN instr_addr_shadow_o[27]
    DIRECTION OUTPUT ;
    USE SIGNAL ;
    ANTENNADIFFAREA 0.360800 ;
    PORT
      LAYER Metal2 ;
        RECT 658.560 870.625 659.120 871.185 ;
    END
  END instr_addr_shadow_o[27]
  PIN instr_addr_shadow_o[28]
    DIRECTION OUTPUT ;
    USE SIGNAL ;
    ANTENNADIFFAREA 0.360800 ;
    PORT
      LAYER Metal3 ;
        RECT 852.705 49.280 853.265 49.840 ;
    END
  END instr_addr_shadow_o[28]
  PIN instr_addr_shadow_o[29]
    DIRECTION OUTPUT ;
    USE SIGNAL ;
    ANTENNADIFFAREA 0.360800 ;
    PORT
      LAYER Metal2 ;
        RECT 819.840 0.000 820.400 0.560 ;
    END
  END instr_addr_shadow_o[29]
  PIN instr_addr_shadow_o[2]
    DIRECTION OUTPUT ;
    USE SIGNAL ;
    ANTENNADIFFAREA 0.360800 ;
    PORT
      LAYER Metal3 ;
        RECT 0.000 847.840 0.560 848.400 ;
    END
  END instr_addr_shadow_o[2]
  PIN instr_addr_shadow_o[30]
    DIRECTION OUTPUT ;
    USE SIGNAL ;
    ANTENNADIFFAREA 0.360800 ;
    PORT
      LAYER Metal2 ;
        RECT 71.680 0.000 72.240 0.560 ;
    END
  END instr_addr_shadow_o[30]
  PIN instr_addr_shadow_o[31]
    DIRECTION OUTPUT ;
    USE SIGNAL ;
    ANTENNADIFFAREA 0.360800 ;
    PORT
      LAYER Metal3 ;
        RECT 0.000 756.000 0.560 756.560 ;
    END
  END instr_addr_shadow_o[31]
  PIN instr_addr_shadow_o[3]
    DIRECTION OUTPUT ;
    USE SIGNAL ;
    ANTENNADIFFAREA 0.360800 ;
    PORT
      LAYER Metal2 ;
        RECT 753.760 870.625 754.320 871.185 ;
    END
  END instr_addr_shadow_o[3]
  PIN instr_addr_shadow_o[4]
    DIRECTION OUTPUT ;
    USE SIGNAL ;
    ANTENNADIFFAREA 0.360800 ;
    PORT
      LAYER Metal2 ;
        RECT 32.480 0.000 33.040 0.560 ;
    END
  END instr_addr_shadow_o[4]
  PIN instr_addr_shadow_o[5]
    DIRECTION OUTPUT ;
    USE SIGNAL ;
    ANTENNADIFFAREA 0.360800 ;
    PORT
      LAYER Metal2 ;
        RECT 771.680 0.000 772.240 0.560 ;
    END
  END instr_addr_shadow_o[5]
  PIN instr_addr_shadow_o[6]
    DIRECTION OUTPUT ;
    USE SIGNAL ;
    ANTENNADIFFAREA 0.360800 ;
    PORT
      LAYER Metal2 ;
        RECT 789.600 870.625 790.160 871.185 ;
    END
  END instr_addr_shadow_o[6]
  PIN instr_addr_shadow_o[7]
    DIRECTION OUTPUT ;
    USE SIGNAL ;
    ANTENNADIFFAREA 0.360800 ;
    PORT
      LAYER Metal3 ;
        RECT 0.000 794.080 0.560 794.640 ;
    END
  END instr_addr_shadow_o[7]
  PIN instr_addr_shadow_o[8]
    DIRECTION OUTPUT ;
    USE SIGNAL ;
    ANTENNADIFFAREA 0.360800 ;
    PORT
      LAYER Metal2 ;
        RECT 840.000 0.000 840.560 0.560 ;
    END
  END instr_addr_shadow_o[8]
  PIN instr_addr_shadow_o[9]
    DIRECTION OUTPUT ;
    USE SIGNAL ;
    ANTENNADIFFAREA 0.360800 ;
    PORT
      LAYER Metal3 ;
        RECT 852.705 184.800 853.265 185.360 ;
    END
  END instr_addr_shadow_o[9]
  PIN instr_err_i
    DIRECTION INPUT ;
    USE SIGNAL ;
    ANTENNAGATEAREA 0.396000 ;
    PORT
      LAYER Metal2 ;
        RECT 245.280 870.625 245.840 871.185 ;
    END
  END instr_err_i
  PIN instr_gnt_i
    DIRECTION INPUT ;
    USE SIGNAL ;
    ANTENNAGATEAREA 0.396000 ;
    PORT
      LAYER Metal2 ;
        RECT 287.840 870.625 288.400 871.185 ;
    END
  END instr_gnt_i
  PIN instr_rdata_i[0]
    DIRECTION INPUT ;
    USE SIGNAL ;
    ANTENNAGATEAREA 0.396000 ;
    PORT
      LAYER Metal2 ;
        RECT 224.000 870.625 224.560 871.185 ;
    END
  END instr_rdata_i[0]
  PIN instr_rdata_i[10]
    DIRECTION INPUT ;
    USE SIGNAL ;
    ANTENNAGATEAREA 0.396000 ;
    PORT
      LAYER Metal3 ;
        RECT 0.000 752.640 0.560 753.200 ;
    END
  END instr_rdata_i[10]
  PIN instr_rdata_i[11]
    DIRECTION INPUT ;
    USE SIGNAL ;
    ANTENNAGATEAREA 0.396000 ;
    PORT
      LAYER Metal3 ;
        RECT 0.000 617.120 0.560 617.680 ;
    END
  END instr_rdata_i[11]
  PIN instr_rdata_i[12]
    DIRECTION INPUT ;
    USE SIGNAL ;
    ANTENNAGATEAREA 0.396000 ;
    PORT
      LAYER Metal3 ;
        RECT 0.000 632.800 0.560 633.360 ;
    END
  END instr_rdata_i[12]
  PIN instr_rdata_i[13]
    DIRECTION INPUT ;
    USE SIGNAL ;
    ANTENNAGATEAREA 0.396000 ;
    PORT
      LAYER Metal3 ;
        RECT 0.000 725.760 0.560 726.320 ;
    END
  END instr_rdata_i[13]
  PIN instr_rdata_i[14]
    DIRECTION INPUT ;
    USE SIGNAL ;
    ANTENNAGATEAREA 0.396000 ;
    PORT
      LAYER Metal3 ;
        RECT 0.000 613.760 0.560 614.320 ;
    END
  END instr_rdata_i[14]
  PIN instr_rdata_i[15]
    DIRECTION INPUT ;
    USE SIGNAL ;
    ANTENNAGATEAREA 0.396000 ;
    PORT
      LAYER Metal2 ;
        RECT 151.200 870.625 151.760 871.185 ;
    END
  END instr_rdata_i[15]
  PIN instr_rdata_i[16]
    DIRECTION INPUT ;
    USE SIGNAL ;
    ANTENNAGATEAREA 0.396000 ;
    PORT
      LAYER Metal2 ;
        RECT 179.200 870.625 179.760 871.185 ;
    END
  END instr_rdata_i[16]
  PIN instr_rdata_i[17]
    DIRECTION INPUT ;
    USE SIGNAL ;
    ANTENNAGATEAREA 0.396000 ;
    PORT
      LAYER Metal2 ;
        RECT 207.200 870.625 207.760 871.185 ;
    END
  END instr_rdata_i[17]
  PIN instr_rdata_i[18]
    DIRECTION INPUT ;
    USE SIGNAL ;
    ANTENNAGATEAREA 0.396000 ;
    PORT
      LAYER Metal3 ;
        RECT 0.000 670.880 0.560 671.440 ;
    END
  END instr_rdata_i[18]
  PIN instr_rdata_i[19]
    DIRECTION INPUT ;
    USE SIGNAL ;
    ANTENNAGATEAREA 0.396000 ;
    PORT
      LAYER Metal3 ;
        RECT 0.000 656.320 0.560 656.880 ;
    END
  END instr_rdata_i[19]
  PIN instr_rdata_i[1]
    DIRECTION INPUT ;
    USE SIGNAL ;
    ANTENNAGATEAREA 0.396000 ;
    PORT
      LAYER Metal2 ;
        RECT 229.600 870.625 230.160 871.185 ;
    END
  END instr_rdata_i[1]
  PIN instr_rdata_i[20]
    DIRECTION INPUT ;
    USE SIGNAL ;
    ANTENNAGATEAREA 0.396000 ;
    PORT
      LAYER Metal2 ;
        RECT 70.560 870.625 71.120 871.185 ;
    END
  END instr_rdata_i[20]
  PIN instr_rdata_i[21]
    DIRECTION INPUT ;
    USE SIGNAL ;
    ANTENNAGATEAREA 0.396000 ;
    PORT
      LAYER Metal3 ;
        RECT 0.000 685.440 0.560 686.000 ;
    END
  END instr_rdata_i[21]
  PIN instr_rdata_i[22]
    DIRECTION INPUT ;
    USE SIGNAL ;
    ANTENNAGATEAREA 0.396000 ;
    PORT
      LAYER Metal3 ;
        RECT 0.000 721.280 0.560 721.840 ;
    END
  END instr_rdata_i[22]
  PIN instr_rdata_i[23]
    DIRECTION INPUT ;
    USE SIGNAL ;
    ANTENNAGATEAREA 0.396000 ;
    PORT
      LAYER Metal3 ;
        RECT 0.000 700.000 0.560 700.560 ;
    END
  END instr_rdata_i[23]
  PIN instr_rdata_i[24]
    DIRECTION INPUT ;
    USE SIGNAL ;
    ANTENNAGATEAREA 0.396000 ;
    PORT
      LAYER Metal3 ;
        RECT 0.000 768.320 0.560 768.880 ;
    END
  END instr_rdata_i[24]
  PIN instr_rdata_i[25]
    DIRECTION INPUT ;
    USE SIGNAL ;
    ANTENNAGATEAREA 0.396000 ;
    PORT
      LAYER Metal2 ;
        RECT 106.400 870.625 106.960 871.185 ;
    END
  END instr_rdata_i[25]
  PIN instr_rdata_i[26]
    DIRECTION INPUT ;
    USE SIGNAL ;
    ANTENNAGATEAREA 0.396000 ;
    PORT
      LAYER Metal3 ;
        RECT 0.000 791.840 0.560 792.400 ;
    END
  END instr_rdata_i[26]
  PIN instr_rdata_i[27]
    DIRECTION INPUT ;
    USE SIGNAL ;
    ANTENNAGATEAREA 0.396000 ;
    PORT
      LAYER Metal3 ;
        RECT 0.000 640.640 0.560 641.200 ;
    END
  END instr_rdata_i[27]
  PIN instr_rdata_i[28]
    DIRECTION INPUT ;
    USE SIGNAL ;
    ANTENNAGATEAREA 0.396000 ;
    PORT
      LAYER Metal3 ;
        RECT 0.000 626.080 0.560 626.640 ;
    END
  END instr_rdata_i[28]
  PIN instr_rdata_i[29]
    DIRECTION INPUT ;
    USE SIGNAL ;
    ANTENNAGATEAREA 0.396000 ;
    PORT
      LAYER Metal3 ;
        RECT 0.000 744.800 0.560 745.360 ;
    END
  END instr_rdata_i[29]
  PIN instr_rdata_i[2]
    DIRECTION INPUT ;
    USE SIGNAL ;
    ANTENNAGATEAREA 0.396000 ;
    PORT
      LAYER Metal3 ;
        RECT 0.000 674.240 0.560 674.800 ;
    END
  END instr_rdata_i[2]
  PIN instr_rdata_i[30]
    DIRECTION INPUT ;
    USE SIGNAL ;
    ANTENNAGATEAREA 0.396000 ;
    PORT
      LAYER Metal3 ;
        RECT 0.000 612.640 0.560 613.200 ;
    END
  END instr_rdata_i[30]
  PIN instr_rdata_i[31]
    DIRECTION INPUT ;
    USE SIGNAL ;
    ANTENNAGATEAREA 0.396000 ;
    PORT
      LAYER Metal2 ;
        RECT 122.080 870.625 122.640 871.185 ;
    END
  END instr_rdata_i[31]
  PIN instr_rdata_i[3]
    DIRECTION INPUT ;
    USE SIGNAL ;
    ANTENNAGATEAREA 0.396000 ;
    PORT
      LAYER Metal3 ;
        RECT 0.000 650.720 0.560 651.280 ;
    END
  END instr_rdata_i[3]
  PIN instr_rdata_i[4]
    DIRECTION INPUT ;
    USE SIGNAL ;
    ANTENNAGATEAREA 0.396000 ;
    PORT
      LAYER Metal2 ;
        RECT 81.760 870.625 82.320 871.185 ;
    END
  END instr_rdata_i[4]
  PIN instr_rdata_i[5]
    DIRECTION INPUT ;
    USE SIGNAL ;
    ANTENNAGATEAREA 0.396000 ;
    PORT
      LAYER Metal3 ;
        RECT 0.000 688.800 0.560 689.360 ;
    END
  END instr_rdata_i[5]
  PIN instr_rdata_i[6]
    DIRECTION INPUT ;
    USE SIGNAL ;
    ANTENNAGATEAREA 0.396000 ;
    PORT
      LAYER Metal3 ;
        RECT 0.000 741.440 0.560 742.000 ;
    END
  END instr_rdata_i[6]
  PIN instr_rdata_i[7]
    DIRECTION INPUT ;
    USE SIGNAL ;
    ANTENNAGATEAREA 0.396000 ;
    PORT
      LAYER Metal3 ;
        RECT 0.000 711.200 0.560 711.760 ;
    END
  END instr_rdata_i[7]
  PIN instr_rdata_i[8]
    DIRECTION INPUT ;
    USE SIGNAL ;
    ANTENNAGATEAREA 0.396000 ;
    PORT
      LAYER Metal3 ;
        RECT 0.000 780.640 0.560 781.200 ;
    END
  END instr_rdata_i[8]
  PIN instr_rdata_i[9]
    DIRECTION INPUT ;
    USE SIGNAL ;
    ANTENNAGATEAREA 0.396000 ;
    PORT
      LAYER Metal2 ;
        RECT 91.840 870.625 92.400 871.185 ;
    END
  END instr_rdata_i[9]
  PIN instr_rdata_intg_i[0]
    DIRECTION INPUT ;
    USE SIGNAL ;
    PORT
      LAYER Metal2 ;
        RECT 22.400 0.000 22.960 0.560 ;
    END
  END instr_rdata_intg_i[0]
  PIN instr_rdata_intg_i[1]
    DIRECTION INPUT ;
    USE SIGNAL ;
    PORT
      LAYER Metal2 ;
        RECT 63.840 0.000 64.400 0.560 ;
    END
  END instr_rdata_intg_i[1]
  PIN instr_rdata_intg_i[2]
    DIRECTION INPUT ;
    USE SIGNAL ;
    PORT
      LAYER Metal2 ;
        RECT 24.640 0.000 25.200 0.560 ;
    END
  END instr_rdata_intg_i[2]
  PIN instr_rdata_intg_i[3]
    DIRECTION INPUT ;
    USE SIGNAL ;
    PORT
      LAYER Metal2 ;
        RECT 28.000 0.000 28.560 0.560 ;
    END
  END instr_rdata_intg_i[3]
  PIN instr_rdata_intg_i[4]
    DIRECTION INPUT ;
    USE SIGNAL ;
    PORT
      LAYER Metal2 ;
        RECT 35.840 0.000 36.400 0.560 ;
    END
  END instr_rdata_intg_i[4]
  PIN instr_rdata_intg_i[5]
    DIRECTION INPUT ;
    USE SIGNAL ;
    PORT
      LAYER Metal2 ;
        RECT 4.480 0.000 5.040 0.560 ;
    END
  END instr_rdata_intg_i[5]
  PIN instr_rdata_intg_i[6]
    DIRECTION INPUT ;
    USE SIGNAL ;
    PORT
      LAYER Metal2 ;
        RECT 29.120 0.000 29.680 0.560 ;
    END
  END instr_rdata_intg_i[6]
  PIN instr_req_o
    DIRECTION OUTPUT ;
    USE SIGNAL ;
    ANTENNADIFFAREA 0.897600 ;
    PORT
      LAYER Metal2 ;
        RECT 281.120 870.625 281.680 871.185 ;
    END
  END instr_req_o
  PIN instr_req_shadow_o
    DIRECTION OUTPUT ;
    USE SIGNAL ;
    ANTENNADIFFAREA 0.360800 ;
    PORT
      LAYER Metal2 ;
        RECT 842.240 0.000 842.800 0.560 ;
    END
  END instr_req_shadow_o
  PIN instr_rvalid_i
    DIRECTION INPUT ;
    USE SIGNAL ;
    ANTENNAGATEAREA 0.396000 ;
    PORT
      LAYER Metal2 ;
        RECT 268.800 870.625 269.360 871.185 ;
    END
  END instr_rvalid_i
  PIN irq_external_i
    DIRECTION INPUT ;
    USE SIGNAL ;
    ANTENNAGATEAREA 0.396000 ;
    PORT
      LAYER Metal2 ;
        RECT 476.000 870.625 476.560 871.185 ;
    END
  END irq_external_i
  PIN irq_fast_i[0]
    DIRECTION INPUT ;
    USE SIGNAL ;
    ANTENNAGATEAREA 0.396000 ;
    PORT
      LAYER Metal2 ;
        RECT 565.600 870.625 566.160 871.185 ;
    END
  END irq_fast_i[0]
  PIN irq_fast_i[10]
    DIRECTION INPUT ;
    USE SIGNAL ;
    ANTENNAGATEAREA 0.396000 ;
    PORT
      LAYER Metal2 ;
        RECT 468.160 870.625 468.720 871.185 ;
    END
  END irq_fast_i[10]
  PIN irq_fast_i[11]
    DIRECTION INPUT ;
    USE SIGNAL ;
    ANTENNAGATEAREA 0.396000 ;
    PORT
      LAYER Metal3 ;
        RECT 852.705 629.440 853.265 630.000 ;
    END
  END irq_fast_i[11]
  PIN irq_fast_i[12]
    DIRECTION INPUT ;
    USE SIGNAL ;
    ANTENNAGATEAREA 0.396000 ;
    PORT
      LAYER Metal3 ;
        RECT 852.705 605.920 853.265 606.480 ;
    END
  END irq_fast_i[12]
  PIN irq_fast_i[13]
    DIRECTION INPUT ;
    USE SIGNAL ;
    ANTENNAGATEAREA 0.396000 ;
    PORT
      LAYER Metal2 ;
        RECT 506.240 870.625 506.800 871.185 ;
    END
  END irq_fast_i[13]
  PIN irq_fast_i[14]
    DIRECTION INPUT ;
    USE SIGNAL ;
    ANTENNAGATEAREA 0.396000 ;
    PORT
      LAYER Metal2 ;
        RECT 510.720 870.625 511.280 871.185 ;
    END
  END irq_fast_i[14]
  PIN irq_fast_i[1]
    DIRECTION INPUT ;
    USE SIGNAL ;
    ANTENNAGATEAREA 0.396000 ;
    PORT
      LAYER Metal2 ;
        RECT 566.720 870.625 567.280 871.185 ;
    END
  END irq_fast_i[1]
  PIN irq_fast_i[2]
    DIRECTION INPUT ;
    USE SIGNAL ;
    ANTENNAGATEAREA 0.396000 ;
    PORT
      LAYER Metal2 ;
        RECT 686.560 870.625 687.120 871.185 ;
    END
  END irq_fast_i[2]
  PIN irq_fast_i[3]
    DIRECTION INPUT ;
    USE SIGNAL ;
    ANTENNAGATEAREA 0.396000 ;
    PORT
      LAYER Metal2 ;
        RECT 678.720 870.625 679.280 871.185 ;
    END
  END irq_fast_i[3]
  PIN irq_fast_i[4]
    DIRECTION INPUT ;
    USE SIGNAL ;
    ANTENNAGATEAREA 0.396000 ;
    PORT
      LAYER Metal2 ;
        RECT 682.080 870.625 682.640 871.185 ;
    END
  END irq_fast_i[4]
  PIN irq_fast_i[5]
    DIRECTION INPUT ;
    USE SIGNAL ;
    ANTENNAGATEAREA 0.396000 ;
    PORT
      LAYER Metal2 ;
        RECT 576.800 870.625 577.360 871.185 ;
    END
  END irq_fast_i[5]
  PIN irq_fast_i[6]
    DIRECTION INPUT ;
    USE SIGNAL ;
    ANTENNAGATEAREA 0.396000 ;
    PORT
      LAYER Metal2 ;
        RECT 683.200 870.625 683.760 871.185 ;
    END
  END irq_fast_i[6]
  PIN irq_fast_i[7]
    DIRECTION INPUT ;
    USE SIGNAL ;
    ANTENNAGATEAREA 0.396000 ;
    PORT
      LAYER Metal3 ;
        RECT 852.705 631.680 853.265 632.240 ;
    END
  END irq_fast_i[7]
  PIN irq_fast_i[8]
    DIRECTION INPUT ;
    USE SIGNAL ;
    ANTENNAGATEAREA 0.396000 ;
    PORT
      LAYER Metal3 ;
        RECT 852.705 593.600 853.265 594.160 ;
    END
  END irq_fast_i[8]
  PIN irq_fast_i[9]
    DIRECTION INPUT ;
    USE SIGNAL ;
    ANTENNAGATEAREA 0.396000 ;
    PORT
      LAYER Metal2 ;
        RECT 554.400 870.625 554.960 871.185 ;
    END
  END irq_fast_i[9]
  PIN irq_nm_i
    DIRECTION INPUT ;
    USE SIGNAL ;
    ANTENNAGATEAREA 0.396000 ;
    PORT
      LAYER Metal2 ;
        RECT 371.840 870.625 372.400 871.185 ;
    END
  END irq_nm_i
  PIN irq_software_i
    DIRECTION INPUT ;
    USE SIGNAL ;
    ANTENNAGATEAREA 0.396000 ;
    PORT
      LAYER Metal2 ;
        RECT 408.800 870.625 409.360 871.185 ;
    END
  END irq_software_i
  PIN irq_timer_i
    DIRECTION INPUT ;
    USE SIGNAL ;
    ANTENNAGATEAREA 0.396000 ;
    PORT
      LAYER Metal2 ;
        RECT 380.800 870.625 381.360 871.185 ;
    END
  END irq_timer_i
  PIN lockstep_cmp_en_o[0]
    DIRECTION OUTPUT ;
    USE SIGNAL ;
    ANTENNADIFFAREA 0.360800 ;
    PORT
      LAYER Metal2 ;
        RECT 685.440 870.625 686.000 871.185 ;
    END
  END lockstep_cmp_en_o[0]
  PIN lockstep_cmp_en_o[1]
    DIRECTION OUTPUT ;
    USE SIGNAL ;
    ANTENNADIFFAREA 0.536800 ;
    PORT
      LAYER Metal3 ;
        RECT 0.000 803.040 0.560 803.600 ;
    END
  END lockstep_cmp_en_o[1]
  PIN lockstep_cmp_en_o[2]
    DIRECTION OUTPUT ;
    USE SIGNAL ;
    ANTENNADIFFAREA 0.360800 ;
    PORT
      LAYER Metal3 ;
        RECT 852.705 850.080 853.265 850.640 ;
    END
  END lockstep_cmp_en_o[2]
  PIN lockstep_cmp_en_o[3]
    DIRECTION OUTPUT ;
    USE SIGNAL ;
    ANTENNADIFFAREA 0.536800 ;
    PORT
      LAYER Metal3 ;
        RECT 852.705 95.200 853.265 95.760 ;
    END
  END lockstep_cmp_en_o[3]
  PIN mcounteren_writable_i[0]
    DIRECTION INPUT ;
    USE SIGNAL ;
    ANTENNAGATEAREA 0.396000 ;
    PORT
      LAYER Metal2 ;
        RECT 343.840 870.625 344.400 871.185 ;
    END
  END mcounteren_writable_i[0]
  PIN mcounteren_writable_i[1]
    DIRECTION INPUT ;
    USE SIGNAL ;
    ANTENNAGATEAREA 0.396000 ;
    PORT
      LAYER Metal2 ;
        RECT 347.200 870.625 347.760 871.185 ;
    END
  END mcounteren_writable_i[1]
  PIN mcounteren_writable_i[2]
    DIRECTION INPUT ;
    USE SIGNAL ;
    ANTENNAGATEAREA 0.396000 ;
    PORT
      LAYER Metal2 ;
        RECT 342.720 870.625 343.280 871.185 ;
    END
  END mcounteren_writable_i[2]
  PIN mcounteren_writable_i[3]
    DIRECTION INPUT ;
    USE SIGNAL ;
    ANTENNAGATEAREA 0.396000 ;
    PORT
      LAYER Metal2 ;
        RECT 346.080 870.625 346.640 871.185 ;
    END
  END mcounteren_writable_i[3]
  PIN ram_cfg_icache_data_i[0]
    DIRECTION INPUT ;
    USE SIGNAL ;
    PORT
      LAYER Metal2 ;
        RECT 34.720 0.000 35.280 0.560 ;
    END
  END ram_cfg_icache_data_i[0]
  PIN ram_cfg_icache_data_i[10]
    DIRECTION INPUT ;
    USE SIGNAL ;
    PORT
      LAYER Metal2 ;
        RECT 40.320 0.000 40.880 0.560 ;
    END
  END ram_cfg_icache_data_i[10]
  PIN ram_cfg_icache_data_i[11]
    DIRECTION INPUT ;
    USE SIGNAL ;
    PORT
      LAYER Metal2 ;
        RECT 33.600 0.000 34.160 0.560 ;
    END
  END ram_cfg_icache_data_i[11]
  PIN ram_cfg_icache_data_i[12]
    DIRECTION INPUT ;
    USE SIGNAL ;
    PORT
      LAYER Metal2 ;
        RECT 39.200 0.000 39.760 0.560 ;
    END
  END ram_cfg_icache_data_i[12]
  PIN ram_cfg_icache_data_i[13]
    DIRECTION INPUT ;
    USE SIGNAL ;
    PORT
      LAYER Metal2 ;
        RECT 43.680 0.000 44.240 0.560 ;
    END
  END ram_cfg_icache_data_i[13]
  PIN ram_cfg_icache_data_i[14]
    DIRECTION INPUT ;
    USE SIGNAL ;
    PORT
      LAYER Metal2 ;
        RECT 41.440 0.000 42.000 0.560 ;
    END
  END ram_cfg_icache_data_i[14]
  PIN ram_cfg_icache_data_i[15]
    DIRECTION INPUT ;
    USE SIGNAL ;
    PORT
      LAYER Metal2 ;
        RECT 38.080 0.000 38.640 0.560 ;
    END
  END ram_cfg_icache_data_i[15]
  PIN ram_cfg_icache_data_i[16]
    DIRECTION INPUT ;
    USE SIGNAL ;
    PORT
      LAYER Metal2 ;
        RECT 36.960 0.000 37.520 0.560 ;
    END
  END ram_cfg_icache_data_i[16]
  PIN ram_cfg_icache_data_i[17]
    DIRECTION INPUT ;
    USE SIGNAL ;
    PORT
      LAYER Metal2 ;
        RECT 48.160 0.000 48.720 0.560 ;
    END
  END ram_cfg_icache_data_i[17]
  PIN ram_cfg_icache_data_i[18]
    DIRECTION INPUT ;
    USE SIGNAL ;
    PORT
      LAYER Metal2 ;
        RECT 79.520 0.000 80.080 0.560 ;
    END
  END ram_cfg_icache_data_i[18]
  PIN ram_cfg_icache_data_i[19]
    DIRECTION INPUT ;
    USE SIGNAL ;
    PORT
      LAYER Metal2 ;
        RECT 42.560 0.000 43.120 0.560 ;
    END
  END ram_cfg_icache_data_i[19]
  PIN ram_cfg_icache_data_i[1]
    DIRECTION INPUT ;
    USE SIGNAL ;
    PORT
      LAYER Metal2 ;
        RECT 51.520 0.000 52.080 0.560 ;
    END
  END ram_cfg_icache_data_i[1]
  PIN ram_cfg_icache_data_i[20]
    DIRECTION INPUT ;
    USE SIGNAL ;
    PORT
      LAYER Metal2 ;
        RECT 49.280 0.000 49.840 0.560 ;
    END
  END ram_cfg_icache_data_i[20]
  PIN ram_cfg_icache_data_i[21]
    DIRECTION INPUT ;
    USE SIGNAL ;
    PORT
      LAYER Metal2 ;
        RECT 50.400 0.000 50.960 0.560 ;
    END
  END ram_cfg_icache_data_i[21]
  PIN ram_cfg_icache_data_i[22]
    DIRECTION INPUT ;
    USE SIGNAL ;
    PORT
      LAYER Metal2 ;
        RECT 47.040 0.000 47.600 0.560 ;
    END
  END ram_cfg_icache_data_i[22]
  PIN ram_cfg_icache_data_i[23]
    DIRECTION INPUT ;
    USE SIGNAL ;
    PORT
      LAYER Metal2 ;
        RECT 45.920 0.000 46.480 0.560 ;
    END
  END ram_cfg_icache_data_i[23]
  PIN ram_cfg_icache_data_i[2]
    DIRECTION INPUT ;
    USE SIGNAL ;
    PORT
      LAYER Metal2 ;
        RECT 52.640 0.000 53.200 0.560 ;
    END
  END ram_cfg_icache_data_i[2]
  PIN ram_cfg_icache_data_i[3]
    DIRECTION INPUT ;
    USE SIGNAL ;
    PORT
      LAYER Metal2 ;
        RECT 53.760 0.000 54.320 0.560 ;
    END
  END ram_cfg_icache_data_i[3]
  PIN ram_cfg_icache_data_i[4]
    DIRECTION INPUT ;
    USE SIGNAL ;
    PORT
      LAYER Metal2 ;
        RECT 59.360 0.000 59.920 0.560 ;
    END
  END ram_cfg_icache_data_i[4]
  PIN ram_cfg_icache_data_i[5]
    DIRECTION INPUT ;
    USE SIGNAL ;
    PORT
      LAYER Metal2 ;
        RECT 57.120 0.000 57.680 0.560 ;
    END
  END ram_cfg_icache_data_i[5]
  PIN ram_cfg_icache_data_i[6]
    DIRECTION INPUT ;
    USE SIGNAL ;
    PORT
      LAYER Metal2 ;
        RECT 58.240 0.000 58.800 0.560 ;
    END
  END ram_cfg_icache_data_i[6]
  PIN ram_cfg_icache_data_i[7]
    DIRECTION INPUT ;
    USE SIGNAL ;
    PORT
      LAYER Metal2 ;
        RECT 62.720 0.000 63.280 0.560 ;
    END
  END ram_cfg_icache_data_i[7]
  PIN ram_cfg_icache_data_i[8]
    DIRECTION INPUT ;
    USE SIGNAL ;
    PORT
      LAYER Metal2 ;
        RECT 56.000 0.000 56.560 0.560 ;
    END
  END ram_cfg_icache_data_i[8]
  PIN ram_cfg_icache_data_i[9]
    DIRECTION INPUT ;
    USE SIGNAL ;
    PORT
      LAYER Metal2 ;
        RECT 54.880 0.000 55.440 0.560 ;
    END
  END ram_cfg_icache_data_i[9]
  PIN ram_cfg_icache_data_o[0]
    DIRECTION OUTPUT ;
    USE SIGNAL ;
    ANTENNADIFFAREA 0.360800 ;
    PORT
      LAYER Metal2 ;
        RECT 779.520 0.000 780.080 0.560 ;
    END
  END ram_cfg_icache_data_o[0]
  PIN ram_cfg_icache_data_o[1]
    DIRECTION OUTPUT ;
    USE SIGNAL ;
    ANTENNADIFFAREA 0.360800 ;
    PORT
      LAYER Metal3 ;
        RECT 0.000 20.160 0.560 20.720 ;
    END
  END ram_cfg_icache_data_o[1]
  PIN ram_cfg_icache_tag_i[0]
    DIRECTION INPUT ;
    USE SIGNAL ;
    PORT
      LAYER Metal2 ;
        RECT 61.600 0.000 62.160 0.560 ;
    END
  END ram_cfg_icache_tag_i[0]
  PIN ram_cfg_icache_tag_i[10]
    DIRECTION INPUT ;
    USE SIGNAL ;
    PORT
      LAYER Metal2 ;
        RECT 67.200 0.000 67.760 0.560 ;
    END
  END ram_cfg_icache_tag_i[10]
  PIN ram_cfg_icache_tag_i[11]
    DIRECTION INPUT ;
    USE SIGNAL ;
    PORT
      LAYER Metal2 ;
        RECT 60.480 0.000 61.040 0.560 ;
    END
  END ram_cfg_icache_tag_i[11]
  PIN ram_cfg_icache_tag_i[12]
    DIRECTION INPUT ;
    USE SIGNAL ;
    PORT
      LAYER Metal2 ;
        RECT 66.080 0.000 66.640 0.560 ;
    END
  END ram_cfg_icache_tag_i[12]
  PIN ram_cfg_icache_tag_i[13]
    DIRECTION INPUT ;
    USE SIGNAL ;
    PORT
      LAYER Metal2 ;
        RECT 70.560 0.000 71.120 0.560 ;
    END
  END ram_cfg_icache_tag_i[13]
  PIN ram_cfg_icache_tag_i[14]
    DIRECTION INPUT ;
    USE SIGNAL ;
    PORT
      LAYER Metal2 ;
        RECT 68.320 0.000 68.880 0.560 ;
    END
  END ram_cfg_icache_tag_i[14]
  PIN ram_cfg_icache_tag_i[15]
    DIRECTION INPUT ;
    USE SIGNAL ;
    PORT
      LAYER Metal2 ;
        RECT 64.960 0.000 65.520 0.560 ;
    END
  END ram_cfg_icache_tag_i[15]
  PIN ram_cfg_icache_tag_i[16]
    DIRECTION INPUT ;
    USE SIGNAL ;
    PORT
      LAYER Metal2 ;
        RECT 106.400 0.000 106.960 0.560 ;
    END
  END ram_cfg_icache_tag_i[16]
  PIN ram_cfg_icache_tag_i[17]
    DIRECTION INPUT ;
    USE SIGNAL ;
    PORT
      LAYER Metal2 ;
        RECT 75.040 0.000 75.600 0.560 ;
    END
  END ram_cfg_icache_tag_i[17]
  PIN ram_cfg_icache_tag_i[18]
    DIRECTION INPUT ;
    USE SIGNAL ;
    PORT
      LAYER Metal2 ;
        RECT 1.120 0.000 1.680 0.560 ;
    END
  END ram_cfg_icache_tag_i[18]
  PIN ram_cfg_icache_tag_i[19]
    DIRECTION INPUT ;
    USE SIGNAL ;
    PORT
      LAYER Metal2 ;
        RECT 69.440 0.000 70.000 0.560 ;
    END
  END ram_cfg_icache_tag_i[19]
  PIN ram_cfg_icache_tag_i[1]
    DIRECTION INPUT ;
    USE SIGNAL ;
    PORT
      LAYER Metal2 ;
        RECT 78.400 0.000 78.960 0.560 ;
    END
  END ram_cfg_icache_tag_i[1]
  PIN ram_cfg_icache_tag_i[20]
    DIRECTION INPUT ;
    USE SIGNAL ;
    PORT
      LAYER Metal2 ;
        RECT 76.160 0.000 76.720 0.560 ;
    END
  END ram_cfg_icache_tag_i[20]
  PIN ram_cfg_icache_tag_i[21]
    DIRECTION INPUT ;
    USE SIGNAL ;
    PORT
      LAYER Metal2 ;
        RECT 77.280 0.000 77.840 0.560 ;
    END
  END ram_cfg_icache_tag_i[21]
  PIN ram_cfg_icache_tag_i[22]
    DIRECTION INPUT ;
    USE SIGNAL ;
    PORT
      LAYER Metal2 ;
        RECT 73.920 0.000 74.480 0.560 ;
    END
  END ram_cfg_icache_tag_i[22]
  PIN ram_cfg_icache_tag_i[23]
    DIRECTION INPUT ;
    USE SIGNAL ;
    PORT
      LAYER Metal2 ;
        RECT 72.800 0.000 73.360 0.560 ;
    END
  END ram_cfg_icache_tag_i[23]
  PIN ram_cfg_icache_tag_i[2]
    DIRECTION INPUT ;
    USE SIGNAL ;
    PORT
      LAYER Metal2 ;
        RECT 115.360 0.000 115.920 0.560 ;
    END
  END ram_cfg_icache_tag_i[2]
  PIN ram_cfg_icache_tag_i[3]
    DIRECTION INPUT ;
    USE SIGNAL ;
    PORT
      LAYER Metal2 ;
        RECT 80.640 0.000 81.200 0.560 ;
    END
  END ram_cfg_icache_tag_i[3]
  PIN ram_cfg_icache_tag_i[4]
    DIRECTION INPUT ;
    USE SIGNAL ;
    PORT
      LAYER Metal2 ;
        RECT 86.240 0.000 86.800 0.560 ;
    END
  END ram_cfg_icache_tag_i[4]
  PIN ram_cfg_icache_tag_i[5]
    DIRECTION INPUT ;
    USE SIGNAL ;
    PORT
      LAYER Metal2 ;
        RECT 84.000 0.000 84.560 0.560 ;
    END
  END ram_cfg_icache_tag_i[5]
  PIN ram_cfg_icache_tag_i[6]
    DIRECTION INPUT ;
    USE SIGNAL ;
    PORT
      LAYER Metal2 ;
        RECT 85.120 0.000 85.680 0.560 ;
    END
  END ram_cfg_icache_tag_i[6]
  PIN ram_cfg_icache_tag_i[7]
    DIRECTION INPUT ;
    USE SIGNAL ;
    PORT
      LAYER Metal2 ;
        RECT 89.600 0.000 90.160 0.560 ;
    END
  END ram_cfg_icache_tag_i[7]
  PIN ram_cfg_icache_tag_i[8]
    DIRECTION INPUT ;
    USE SIGNAL ;
    PORT
      LAYER Metal2 ;
        RECT 82.880 0.000 83.440 0.560 ;
    END
  END ram_cfg_icache_tag_i[8]
  PIN ram_cfg_icache_tag_i[9]
    DIRECTION INPUT ;
    USE SIGNAL ;
    PORT
      LAYER Metal2 ;
        RECT 2.240 0.000 2.800 0.560 ;
    END
  END ram_cfg_icache_tag_i[9]
  PIN ram_cfg_icache_tag_o[0]
    DIRECTION OUTPUT ;
    USE SIGNAL ;
    ANTENNADIFFAREA 0.360800 ;
    PORT
      LAYER Metal3 ;
        RECT 852.705 91.840 853.265 92.400 ;
    END
  END ram_cfg_icache_tag_o[0]
  PIN ram_cfg_icache_tag_o[1]
    DIRECTION OUTPUT ;
    USE SIGNAL ;
    ANTENNADIFFAREA 0.360800 ;
    PORT
      LAYER Metal2 ;
        RECT 794.080 0.000 794.640 0.560 ;
    END
  END ram_cfg_icache_tag_o[1]
  PIN rst_ni
    DIRECTION INPUT ;
    USE SIGNAL ;
    ANTENNAGATEAREA 0.396000 ;
    PORT
      LAYER Metal3 ;
        RECT 852.705 20.160 853.265 20.720 ;
    END
  END rst_ni
  PIN scan_rst_ni
    DIRECTION INPUT ;
    USE SIGNAL ;
    PORT
      LAYER Metal2 ;
        RECT 88.480 0.000 89.040 0.560 ;
    END
  END scan_rst_ni
  PIN scramble_key_i[0]
    DIRECTION INPUT ;
    USE SIGNAL ;
    PORT
      LAYER Metal2 ;
        RECT 94.080 0.000 94.640 0.560 ;
    END
  END scramble_key_i[0]
  PIN scramble_key_i[100]
    DIRECTION INPUT ;
    USE SIGNAL ;
    PORT
      LAYER Metal2 ;
        RECT 87.360 0.000 87.920 0.560 ;
    END
  END scramble_key_i[100]
  PIN scramble_key_i[101]
    DIRECTION INPUT ;
    USE SIGNAL ;
    PORT
      LAYER Metal2 ;
        RECT 92.960 0.000 93.520 0.560 ;
    END
  END scramble_key_i[101]
  PIN scramble_key_i[102]
    DIRECTION INPUT ;
    USE SIGNAL ;
    PORT
      LAYER Metal2 ;
        RECT 97.440 0.000 98.000 0.560 ;
    END
  END scramble_key_i[102]
  PIN scramble_key_i[103]
    DIRECTION INPUT ;
    USE SIGNAL ;
    PORT
      LAYER Metal2 ;
        RECT 95.200 0.000 95.760 0.560 ;
    END
  END scramble_key_i[103]
  PIN scramble_key_i[104]
    DIRECTION INPUT ;
    USE SIGNAL ;
    PORT
      LAYER Metal2 ;
        RECT 91.840 0.000 92.400 0.560 ;
    END
  END scramble_key_i[104]
  PIN scramble_key_i[105]
    DIRECTION INPUT ;
    USE SIGNAL ;
    PORT
      LAYER Metal2 ;
        RECT 90.720 0.000 91.280 0.560 ;
    END
  END scramble_key_i[105]
  PIN scramble_key_i[106]
    DIRECTION INPUT ;
    USE SIGNAL ;
    PORT
      LAYER Metal2 ;
        RECT 101.920 0.000 102.480 0.560 ;
    END
  END scramble_key_i[106]
  PIN scramble_key_i[107]
    DIRECTION INPUT ;
    USE SIGNAL ;
    PORT
      LAYER Metal2 ;
        RECT 98.560 0.000 99.120 0.560 ;
    END
  END scramble_key_i[107]
  PIN scramble_key_i[108]
    DIRECTION INPUT ;
    USE SIGNAL ;
    PORT
      LAYER Metal2 ;
        RECT 96.320 0.000 96.880 0.560 ;
    END
  END scramble_key_i[108]
  PIN scramble_key_i[109]
    DIRECTION INPUT ;
    USE SIGNAL ;
    PORT
      LAYER Metal2 ;
        RECT 105.280 0.000 105.840 0.560 ;
    END
  END scramble_key_i[109]
  PIN scramble_key_i[10]
    DIRECTION INPUT ;
    USE SIGNAL ;
    PORT
      LAYER Metal2 ;
        RECT 103.040 0.000 103.600 0.560 ;
    END
  END scramble_key_i[10]
  PIN scramble_key_i[110]
    DIRECTION INPUT ;
    USE SIGNAL ;
    PORT
      LAYER Metal2 ;
        RECT 104.160 0.000 104.720 0.560 ;
    END
  END scramble_key_i[110]
  PIN scramble_key_i[111]
    DIRECTION INPUT ;
    USE SIGNAL ;
    PORT
      LAYER Metal2 ;
        RECT 100.800 0.000 101.360 0.560 ;
    END
  END scramble_key_i[111]
  PIN scramble_key_i[112]
    DIRECTION INPUT ;
    USE SIGNAL ;
    PORT
      LAYER Metal2 ;
        RECT 99.680 0.000 100.240 0.560 ;
    END
  END scramble_key_i[112]
  PIN scramble_key_i[113]
    DIRECTION INPUT ;
    USE SIGNAL ;
    PORT
      LAYER Metal2 ;
        RECT 143.360 0.000 143.920 0.560 ;
    END
  END scramble_key_i[113]
  PIN scramble_key_i[114]
    DIRECTION INPUT ;
    USE SIGNAL ;
    PORT
      LAYER Metal2 ;
        RECT 107.520 0.000 108.080 0.560 ;
    END
  END scramble_key_i[114]
  PIN scramble_key_i[115]
    DIRECTION INPUT ;
    USE SIGNAL ;
    PORT
      LAYER Metal2 ;
        RECT 114.240 0.000 114.800 0.560 ;
    END
  END scramble_key_i[115]
  PIN scramble_key_i[116]
    DIRECTION INPUT ;
    USE SIGNAL ;
    PORT
      LAYER Metal2 ;
        RECT 110.880 0.000 111.440 0.560 ;
    END
  END scramble_key_i[116]
  PIN scramble_key_i[117]
    DIRECTION INPUT ;
    USE SIGNAL ;
    PORT
      LAYER Metal2 ;
        RECT 112.000 0.000 112.560 0.560 ;
    END
  END scramble_key_i[117]
  PIN scramble_key_i[118]
    DIRECTION INPUT ;
    USE SIGNAL ;
    PORT
      LAYER Metal2 ;
        RECT 113.120 0.000 113.680 0.560 ;
    END
  END scramble_key_i[118]
  PIN scramble_key_i[119]
    DIRECTION INPUT ;
    USE SIGNAL ;
    PORT
      LAYER Metal2 ;
        RECT 109.760 0.000 110.320 0.560 ;
    END
  END scramble_key_i[119]
  PIN scramble_key_i[11]
    DIRECTION INPUT ;
    USE SIGNAL ;
    PORT
      LAYER Metal2 ;
        RECT 3.360 0.000 3.920 0.560 ;
    END
  END scramble_key_i[11]
  PIN scramble_key_i[120]
    DIRECTION INPUT ;
    USE SIGNAL ;
    PORT
      LAYER Metal2 ;
        RECT 151.200 0.000 151.760 0.560 ;
    END
  END scramble_key_i[120]
  PIN scramble_key_i[121]
    DIRECTION INPUT ;
    USE SIGNAL ;
    PORT
      LAYER Metal2 ;
        RECT 116.480 0.000 117.040 0.560 ;
    END
  END scramble_key_i[121]
  PIN scramble_key_i[122]
    DIRECTION INPUT ;
    USE SIGNAL ;
    PORT
      LAYER Metal2 ;
        RECT 123.200 0.000 123.760 0.560 ;
    END
  END scramble_key_i[122]
  PIN scramble_key_i[123]
    DIRECTION INPUT ;
    USE SIGNAL ;
    PORT
      LAYER Metal2 ;
        RECT 119.840 0.000 120.400 0.560 ;
    END
  END scramble_key_i[123]
  PIN scramble_key_i[124]
    DIRECTION INPUT ;
    USE SIGNAL ;
    PORT
      LAYER Metal2 ;
        RECT 120.960 0.000 121.520 0.560 ;
    END
  END scramble_key_i[124]
  PIN scramble_key_i[125]
    DIRECTION INPUT ;
    USE SIGNAL ;
    PORT
      LAYER Metal2 ;
        RECT 122.080 0.000 122.640 0.560 ;
    END
  END scramble_key_i[125]
  PIN scramble_key_i[126]
    DIRECTION INPUT ;
    USE SIGNAL ;
    PORT
      LAYER Metal2 ;
        RECT 118.720 0.000 119.280 0.560 ;
    END
  END scramble_key_i[126]
  PIN scramble_key_i[127]
    DIRECTION INPUT ;
    USE SIGNAL ;
    PORT
      LAYER Metal2 ;
        RECT 117.600 0.000 118.160 0.560 ;
    END
  END scramble_key_i[127]
  PIN scramble_key_i[12]
    DIRECTION INPUT ;
    USE SIGNAL ;
    PORT
      LAYER Metal2 ;
        RECT 124.320 0.000 124.880 0.560 ;
    END
  END scramble_key_i[12]
  PIN scramble_key_i[13]
    DIRECTION INPUT ;
    USE SIGNAL ;
    PORT
      LAYER Metal2 ;
        RECT 125.440 0.000 126.000 0.560 ;
    END
  END scramble_key_i[13]
  PIN scramble_key_i[14]
    DIRECTION INPUT ;
    USE SIGNAL ;
    PORT
      LAYER Metal2 ;
        RECT 132.160 0.000 132.720 0.560 ;
    END
  END scramble_key_i[14]
  PIN scramble_key_i[15]
    DIRECTION INPUT ;
    USE SIGNAL ;
    PORT
      LAYER Metal2 ;
        RECT 128.800 0.000 129.360 0.560 ;
    END
  END scramble_key_i[15]
  PIN scramble_key_i[16]
    DIRECTION INPUT ;
    USE SIGNAL ;
    PORT
      LAYER Metal2 ;
        RECT 129.920 0.000 130.480 0.560 ;
    END
  END scramble_key_i[16]
  PIN scramble_key_i[17]
    DIRECTION INPUT ;
    USE SIGNAL ;
    PORT
      LAYER Metal2 ;
        RECT 131.040 0.000 131.600 0.560 ;
    END
  END scramble_key_i[17]
  PIN scramble_key_i[18]
    DIRECTION INPUT ;
    USE SIGNAL ;
    PORT
      LAYER Metal2 ;
        RECT 127.680 0.000 128.240 0.560 ;
    END
  END scramble_key_i[18]
  PIN scramble_key_i[19]
    DIRECTION INPUT ;
    USE SIGNAL ;
    PORT
      LAYER Metal2 ;
        RECT 126.560 0.000 127.120 0.560 ;
    END
  END scramble_key_i[19]
  PIN scramble_key_i[1]
    DIRECTION INPUT ;
    USE SIGNAL ;
    PORT
      LAYER Metal2 ;
        RECT 133.280 0.000 133.840 0.560 ;
    END
  END scramble_key_i[1]
  PIN scramble_key_i[20]
    DIRECTION INPUT ;
    USE SIGNAL ;
    PORT
      LAYER Metal2 ;
        RECT 134.400 0.000 134.960 0.560 ;
    END
  END scramble_key_i[20]
  PIN scramble_key_i[21]
    DIRECTION INPUT ;
    USE SIGNAL ;
    PORT
      LAYER Metal2 ;
        RECT 141.120 0.000 141.680 0.560 ;
    END
  END scramble_key_i[21]
  PIN scramble_key_i[22]
    DIRECTION INPUT ;
    USE SIGNAL ;
    PORT
      LAYER Metal2 ;
        RECT 137.760 0.000 138.320 0.560 ;
    END
  END scramble_key_i[22]
  PIN scramble_key_i[23]
    DIRECTION INPUT ;
    USE SIGNAL ;
    PORT
      LAYER Metal2 ;
        RECT 138.880 0.000 139.440 0.560 ;
    END
  END scramble_key_i[23]
  PIN scramble_key_i[24]
    DIRECTION INPUT ;
    USE SIGNAL ;
    PORT
      LAYER Metal2 ;
        RECT 140.000 0.000 140.560 0.560 ;
    END
  END scramble_key_i[24]
  PIN scramble_key_i[25]
    DIRECTION INPUT ;
    USE SIGNAL ;
    PORT
      LAYER Metal2 ;
        RECT 136.640 0.000 137.200 0.560 ;
    END
  END scramble_key_i[25]
  PIN scramble_key_i[26]
    DIRECTION INPUT ;
    USE SIGNAL ;
    PORT
      LAYER Metal2 ;
        RECT 135.520 0.000 136.080 0.560 ;
    END
  END scramble_key_i[26]
  PIN scramble_key_i[27]
    DIRECTION INPUT ;
    USE SIGNAL ;
    PORT
      LAYER Metal2 ;
        RECT 142.240 0.000 142.800 0.560 ;
    END
  END scramble_key_i[27]
  PIN scramble_key_i[28]
    DIRECTION INPUT ;
    USE SIGNAL ;
    PORT
      LAYER Metal2 ;
        RECT 180.320 0.000 180.880 0.560 ;
    END
  END scramble_key_i[28]
  PIN scramble_key_i[29]
    DIRECTION INPUT ;
    USE SIGNAL ;
    PORT
      LAYER Metal2 ;
        RECT 150.080 0.000 150.640 0.560 ;
    END
  END scramble_key_i[29]
  PIN scramble_key_i[2]
    DIRECTION INPUT ;
    USE SIGNAL ;
    PORT
      LAYER Metal2 ;
        RECT 146.720 0.000 147.280 0.560 ;
    END
  END scramble_key_i[2]
  PIN scramble_key_i[30]
    DIRECTION INPUT ;
    USE SIGNAL ;
    PORT
      LAYER Metal2 ;
        RECT 147.840 0.000 148.400 0.560 ;
    END
  END scramble_key_i[30]
  PIN scramble_key_i[31]
    DIRECTION INPUT ;
    USE SIGNAL ;
    PORT
      LAYER Metal2 ;
        RECT 148.960 0.000 149.520 0.560 ;
    END
  END scramble_key_i[31]
  PIN scramble_key_i[32]
    DIRECTION INPUT ;
    USE SIGNAL ;
    PORT
      LAYER Metal2 ;
        RECT 145.600 0.000 146.160 0.560 ;
    END
  END scramble_key_i[32]
  PIN scramble_key_i[33]
    DIRECTION INPUT ;
    USE SIGNAL ;
    PORT
      LAYER Metal2 ;
        RECT 144.480 0.000 145.040 0.560 ;
    END
  END scramble_key_i[33]
  PIN scramble_key_i[34]
    DIRECTION INPUT ;
    USE SIGNAL ;
    PORT
      LAYER Metal2 ;
        RECT 187.040 0.000 187.600 0.560 ;
    END
  END scramble_key_i[34]
  PIN scramble_key_i[35]
    DIRECTION INPUT ;
    USE SIGNAL ;
    PORT
      LAYER Metal2 ;
        RECT 152.320 0.000 152.880 0.560 ;
    END
  END scramble_key_i[35]
  PIN scramble_key_i[36]
    DIRECTION INPUT ;
    USE SIGNAL ;
    PORT
      LAYER Metal2 ;
        RECT 159.040 0.000 159.600 0.560 ;
    END
  END scramble_key_i[36]
  PIN scramble_key_i[37]
    DIRECTION INPUT ;
    USE SIGNAL ;
    PORT
      LAYER Metal2 ;
        RECT 155.680 0.000 156.240 0.560 ;
    END
  END scramble_key_i[37]
  PIN scramble_key_i[38]
    DIRECTION INPUT ;
    USE SIGNAL ;
    PORT
      LAYER Metal2 ;
        RECT 156.800 0.000 157.360 0.560 ;
    END
  END scramble_key_i[38]
  PIN scramble_key_i[39]
    DIRECTION INPUT ;
    USE SIGNAL ;
    PORT
      LAYER Metal2 ;
        RECT 157.920 0.000 158.480 0.560 ;
    END
  END scramble_key_i[39]
  PIN scramble_key_i[3]
    DIRECTION INPUT ;
    USE SIGNAL ;
    PORT
      LAYER Metal2 ;
        RECT 154.560 0.000 155.120 0.560 ;
    END
  END scramble_key_i[3]
  PIN scramble_key_i[40]
    DIRECTION INPUT ;
    USE SIGNAL ;
    PORT
      LAYER Metal2 ;
        RECT 153.440 0.000 154.000 0.560 ;
    END
  END scramble_key_i[40]
  PIN scramble_key_i[41]
    DIRECTION INPUT ;
    USE SIGNAL ;
    PORT
      LAYER Metal2 ;
        RECT 160.160 0.000 160.720 0.560 ;
    END
  END scramble_key_i[41]
  PIN scramble_key_i[42]
    DIRECTION INPUT ;
    USE SIGNAL ;
    PORT
      LAYER Metal2 ;
        RECT 161.280 0.000 161.840 0.560 ;
    END
  END scramble_key_i[42]
  PIN scramble_key_i[43]
    DIRECTION INPUT ;
    USE SIGNAL ;
    PORT
      LAYER Metal2 ;
        RECT 168.000 0.000 168.560 0.560 ;
    END
  END scramble_key_i[43]
  PIN scramble_key_i[44]
    DIRECTION INPUT ;
    USE SIGNAL ;
    PORT
      LAYER Metal2 ;
        RECT 164.640 0.000 165.200 0.560 ;
    END
  END scramble_key_i[44]
  PIN scramble_key_i[45]
    DIRECTION INPUT ;
    USE SIGNAL ;
    PORT
      LAYER Metal2 ;
        RECT 165.760 0.000 166.320 0.560 ;
    END
  END scramble_key_i[45]
  PIN scramble_key_i[46]
    DIRECTION INPUT ;
    USE SIGNAL ;
    PORT
      LAYER Metal2 ;
        RECT 166.880 0.000 167.440 0.560 ;
    END
  END scramble_key_i[46]
  PIN scramble_key_i[47]
    DIRECTION INPUT ;
    USE SIGNAL ;
    PORT
      LAYER Metal2 ;
        RECT 163.520 0.000 164.080 0.560 ;
    END
  END scramble_key_i[47]
  PIN scramble_key_i[48]
    DIRECTION INPUT ;
    USE SIGNAL ;
    PORT
      LAYER Metal2 ;
        RECT 162.400 0.000 162.960 0.560 ;
    END
  END scramble_key_i[48]
  PIN scramble_key_i[49]
    DIRECTION INPUT ;
    USE SIGNAL ;
    PORT
      LAYER Metal2 ;
        RECT 169.120 0.000 169.680 0.560 ;
    END
  END scramble_key_i[49]
  PIN scramble_key_i[4]
    DIRECTION INPUT ;
    USE SIGNAL ;
    PORT
      LAYER Metal2 ;
        RECT 170.240 0.000 170.800 0.560 ;
    END
  END scramble_key_i[4]
  PIN scramble_key_i[50]
    DIRECTION INPUT ;
    USE SIGNAL ;
    PORT
      LAYER Metal2 ;
        RECT 176.960 0.000 177.520 0.560 ;
    END
  END scramble_key_i[50]
  PIN scramble_key_i[51]
    DIRECTION INPUT ;
    USE SIGNAL ;
    PORT
      LAYER Metal2 ;
        RECT 173.600 0.000 174.160 0.560 ;
    END
  END scramble_key_i[51]
  PIN scramble_key_i[52]
    DIRECTION INPUT ;
    USE SIGNAL ;
    PORT
      LAYER Metal2 ;
        RECT 174.720 0.000 175.280 0.560 ;
    END
  END scramble_key_i[52]
  PIN scramble_key_i[53]
    DIRECTION INPUT ;
    USE SIGNAL ;
    PORT
      LAYER Metal2 ;
        RECT 175.840 0.000 176.400 0.560 ;
    END
  END scramble_key_i[53]
  PIN scramble_key_i[54]
    DIRECTION INPUT ;
    USE SIGNAL ;
    PORT
      LAYER Metal2 ;
        RECT 172.480 0.000 173.040 0.560 ;
    END
  END scramble_key_i[54]
  PIN scramble_key_i[55]
    DIRECTION INPUT ;
    USE SIGNAL ;
    PORT
      LAYER Metal2 ;
        RECT 171.360 0.000 171.920 0.560 ;
    END
  END scramble_key_i[55]
  PIN scramble_key_i[56]
    DIRECTION INPUT ;
    USE SIGNAL ;
    PORT
      LAYER Metal2 ;
        RECT 178.080 0.000 178.640 0.560 ;
    END
  END scramble_key_i[56]
  PIN scramble_key_i[57]
    DIRECTION INPUT ;
    USE SIGNAL ;
    PORT
      LAYER Metal2 ;
        RECT 179.200 0.000 179.760 0.560 ;
    END
  END scramble_key_i[57]
  PIN scramble_key_i[58]
    DIRECTION INPUT ;
    USE SIGNAL ;
    PORT
      LAYER Metal2 ;
        RECT 185.920 0.000 186.480 0.560 ;
    END
  END scramble_key_i[58]
  PIN scramble_key_i[59]
    DIRECTION INPUT ;
    USE SIGNAL ;
    PORT
      LAYER Metal2 ;
        RECT 182.560 0.000 183.120 0.560 ;
    END
  END scramble_key_i[59]
  PIN scramble_key_i[5]
    DIRECTION INPUT ;
    USE SIGNAL ;
    PORT
      LAYER Metal2 ;
        RECT 183.680 0.000 184.240 0.560 ;
    END
  END scramble_key_i[5]
  PIN scramble_key_i[60]
    DIRECTION INPUT ;
    USE SIGNAL ;
    PORT
      LAYER Metal2 ;
        RECT 184.800 0.000 185.360 0.560 ;
    END
  END scramble_key_i[60]
  PIN scramble_key_i[61]
    DIRECTION INPUT ;
    USE SIGNAL ;
    PORT
      LAYER Metal2 ;
        RECT 181.440 0.000 182.000 0.560 ;
    END
  END scramble_key_i[61]
  PIN scramble_key_i[62]
    DIRECTION INPUT ;
    USE SIGNAL ;
    PORT
      LAYER Metal2 ;
        RECT 222.880 0.000 223.440 0.560 ;
    END
  END scramble_key_i[62]
  PIN scramble_key_i[63]
    DIRECTION INPUT ;
    USE SIGNAL ;
    PORT
      LAYER Metal2 ;
        RECT 224.000 0.000 224.560 0.560 ;
    END
  END scramble_key_i[63]
  PIN scramble_key_i[64]
    DIRECTION INPUT ;
    USE SIGNAL ;
    PORT
      LAYER Metal2 ;
        RECT 188.160 0.000 188.720 0.560 ;
    END
  END scramble_key_i[64]
  PIN scramble_key_i[65]
    DIRECTION INPUT ;
    USE SIGNAL ;
    PORT
      LAYER Metal2 ;
        RECT 194.880 0.000 195.440 0.560 ;
    END
  END scramble_key_i[65]
  PIN scramble_key_i[66]
    DIRECTION INPUT ;
    USE SIGNAL ;
    PORT
      LAYER Metal2 ;
        RECT 191.520 0.000 192.080 0.560 ;
    END
  END scramble_key_i[66]
  PIN scramble_key_i[67]
    DIRECTION INPUT ;
    USE SIGNAL ;
    PORT
      LAYER Metal2 ;
        RECT 192.640 0.000 193.200 0.560 ;
    END
  END scramble_key_i[67]
  PIN scramble_key_i[68]
    DIRECTION INPUT ;
    USE SIGNAL ;
    PORT
      LAYER Metal2 ;
        RECT 193.760 0.000 194.320 0.560 ;
    END
  END scramble_key_i[68]
  PIN scramble_key_i[69]
    DIRECTION INPUT ;
    USE SIGNAL ;
    PORT
      LAYER Metal2 ;
        RECT 190.400 0.000 190.960 0.560 ;
    END
  END scramble_key_i[69]
  PIN scramble_key_i[6]
    DIRECTION INPUT ;
    USE SIGNAL ;
    PORT
      LAYER Metal2 ;
        RECT 189.280 0.000 189.840 0.560 ;
    END
  END scramble_key_i[6]
  PIN scramble_key_i[70]
    DIRECTION INPUT ;
    USE SIGNAL ;
    PORT
      LAYER Metal2 ;
        RECT 196.000 0.000 196.560 0.560 ;
    END
  END scramble_key_i[70]
  PIN scramble_key_i[71]
    DIRECTION INPUT ;
    USE SIGNAL ;
    PORT
      LAYER Metal2 ;
        RECT 197.120 0.000 197.680 0.560 ;
    END
  END scramble_key_i[71]
  PIN scramble_key_i[72]
    DIRECTION INPUT ;
    USE SIGNAL ;
    PORT
      LAYER Metal2 ;
        RECT 203.840 0.000 204.400 0.560 ;
    END
  END scramble_key_i[72]
  PIN scramble_key_i[73]
    DIRECTION INPUT ;
    USE SIGNAL ;
    PORT
      LAYER Metal2 ;
        RECT 200.480 0.000 201.040 0.560 ;
    END
  END scramble_key_i[73]
  PIN scramble_key_i[74]
    DIRECTION INPUT ;
    USE SIGNAL ;
    PORT
      LAYER Metal2 ;
        RECT 201.600 0.000 202.160 0.560 ;
    END
  END scramble_key_i[74]
  PIN scramble_key_i[75]
    DIRECTION INPUT ;
    USE SIGNAL ;
    PORT
      LAYER Metal2 ;
        RECT 202.720 0.000 203.280 0.560 ;
    END
  END scramble_key_i[75]
  PIN scramble_key_i[76]
    DIRECTION INPUT ;
    USE SIGNAL ;
    PORT
      LAYER Metal2 ;
        RECT 199.360 0.000 199.920 0.560 ;
    END
  END scramble_key_i[76]
  PIN scramble_key_i[77]
    DIRECTION INPUT ;
    USE SIGNAL ;
    PORT
      LAYER Metal2 ;
        RECT 198.240 0.000 198.800 0.560 ;
    END
  END scramble_key_i[77]
  PIN scramble_key_i[78]
    DIRECTION INPUT ;
    USE SIGNAL ;
    PORT
      LAYER Metal2 ;
        RECT 204.960 0.000 205.520 0.560 ;
    END
  END scramble_key_i[78]
  PIN scramble_key_i[79]
    DIRECTION INPUT ;
    USE SIGNAL ;
    PORT
      LAYER Metal2 ;
        RECT 206.080 0.000 206.640 0.560 ;
    END
  END scramble_key_i[79]
  PIN scramble_key_i[7]
    DIRECTION INPUT ;
    USE SIGNAL ;
    PORT
      LAYER Metal2 ;
        RECT 212.800 0.000 213.360 0.560 ;
    END
  END scramble_key_i[7]
  PIN scramble_key_i[80]
    DIRECTION INPUT ;
    USE SIGNAL ;
    PORT
      LAYER Metal2 ;
        RECT 209.440 0.000 210.000 0.560 ;
    END
  END scramble_key_i[80]
  PIN scramble_key_i[81]
    DIRECTION INPUT ;
    USE SIGNAL ;
    PORT
      LAYER Metal2 ;
        RECT 210.560 0.000 211.120 0.560 ;
    END
  END scramble_key_i[81]
  PIN scramble_key_i[82]
    DIRECTION INPUT ;
    USE SIGNAL ;
    PORT
      LAYER Metal2 ;
        RECT 211.680 0.000 212.240 0.560 ;
    END
  END scramble_key_i[82]
  PIN scramble_key_i[83]
    DIRECTION INPUT ;
    USE SIGNAL ;
    PORT
      LAYER Metal2 ;
        RECT 208.320 0.000 208.880 0.560 ;
    END
  END scramble_key_i[83]
  PIN scramble_key_i[84]
    DIRECTION INPUT ;
    USE SIGNAL ;
    PORT
      LAYER Metal2 ;
        RECT 207.200 0.000 207.760 0.560 ;
    END
  END scramble_key_i[84]
  PIN scramble_key_i[85]
    DIRECTION INPUT ;
    USE SIGNAL ;
    PORT
      LAYER Metal2 ;
        RECT 213.920 0.000 214.480 0.560 ;
    END
  END scramble_key_i[85]
  PIN scramble_key_i[86]
    DIRECTION INPUT ;
    USE SIGNAL ;
    PORT
      LAYER Metal2 ;
        RECT 215.040 0.000 215.600 0.560 ;
    END
  END scramble_key_i[86]
  PIN scramble_key_i[87]
    DIRECTION INPUT ;
    USE SIGNAL ;
    PORT
      LAYER Metal2 ;
        RECT 221.760 0.000 222.320 0.560 ;
    END
  END scramble_key_i[87]
  PIN scramble_key_i[88]
    DIRECTION INPUT ;
    USE SIGNAL ;
    PORT
      LAYER Metal2 ;
        RECT 218.400 0.000 218.960 0.560 ;
    END
  END scramble_key_i[88]
  PIN scramble_key_i[89]
    DIRECTION INPUT ;
    USE SIGNAL ;
    PORT
      LAYER Metal2 ;
        RECT 219.520 0.000 220.080 0.560 ;
    END
  END scramble_key_i[89]
  PIN scramble_key_i[8]
    DIRECTION INPUT ;
    USE SIGNAL ;
    PORT
      LAYER Metal2 ;
        RECT 220.640 0.000 221.200 0.560 ;
    END
  END scramble_key_i[8]
  PIN scramble_key_i[90]
    DIRECTION INPUT ;
    USE SIGNAL ;
    PORT
      LAYER Metal2 ;
        RECT 217.280 0.000 217.840 0.560 ;
    END
  END scramble_key_i[90]
  PIN scramble_key_i[91]
    DIRECTION INPUT ;
    USE SIGNAL ;
    PORT
      LAYER Metal2 ;
        RECT 216.160 0.000 216.720 0.560 ;
    END
  END scramble_key_i[91]
  PIN scramble_key_i[92]
    DIRECTION INPUT ;
    USE SIGNAL ;
    PORT
      LAYER Metal2 ;
        RECT 225.120 0.000 225.680 0.560 ;
    END
  END scramble_key_i[92]
  PIN scramble_key_i[93]
    DIRECTION INPUT ;
    USE SIGNAL ;
    PORT
      LAYER Metal2 ;
        RECT 226.240 0.000 226.800 0.560 ;
    END
  END scramble_key_i[93]
  PIN scramble_key_i[94]
    DIRECTION INPUT ;
    USE SIGNAL ;
    PORT
      LAYER Metal2 ;
        RECT 227.360 0.000 227.920 0.560 ;
    END
  END scramble_key_i[94]
  PIN scramble_key_i[95]
    DIRECTION INPUT ;
    USE SIGNAL ;
    PORT
      LAYER Metal2 ;
        RECT 228.480 0.000 229.040 0.560 ;
    END
  END scramble_key_i[95]
  PIN scramble_key_i[96]
    DIRECTION INPUT ;
    USE SIGNAL ;
    PORT
      LAYER Metal2 ;
        RECT 229.600 0.000 230.160 0.560 ;
    END
  END scramble_key_i[96]
  PIN scramble_key_i[97]
    DIRECTION INPUT ;
    USE SIGNAL ;
    PORT
      LAYER Metal2 ;
        RECT 230.720 0.000 231.280 0.560 ;
    END
  END scramble_key_i[97]
  PIN scramble_key_i[98]
    DIRECTION INPUT ;
    USE SIGNAL ;
    PORT
      LAYER Metal2 ;
        RECT 231.840 0.000 232.400 0.560 ;
    END
  END scramble_key_i[98]
  PIN scramble_key_i[99]
    DIRECTION INPUT ;
    USE SIGNAL ;
    PORT
      LAYER Metal2 ;
        RECT 232.960 0.000 233.520 0.560 ;
    END
  END scramble_key_i[99]
  PIN scramble_key_i[9]
    DIRECTION INPUT ;
    USE SIGNAL ;
    PORT
      LAYER Metal2 ;
        RECT 234.080 0.000 234.640 0.560 ;
    END
  END scramble_key_i[9]
  PIN scramble_key_valid_i
    DIRECTION INPUT ;
    USE SIGNAL ;
    PORT
      LAYER Metal2 ;
        RECT 235.200 0.000 235.760 0.560 ;
    END
  END scramble_key_valid_i
  PIN scramble_nonce_i[0]
    DIRECTION INPUT ;
    USE SIGNAL ;
    PORT
      LAYER Metal2 ;
        RECT 236.320 0.000 236.880 0.560 ;
    END
  END scramble_nonce_i[0]
  PIN scramble_nonce_i[10]
    DIRECTION INPUT ;
    USE SIGNAL ;
    PORT
      LAYER Metal2 ;
        RECT 237.440 0.000 238.000 0.560 ;
    END
  END scramble_nonce_i[10]
  PIN scramble_nonce_i[11]
    DIRECTION INPUT ;
    USE SIGNAL ;
    PORT
      LAYER Metal2 ;
        RECT 238.560 0.000 239.120 0.560 ;
    END
  END scramble_nonce_i[11]
  PIN scramble_nonce_i[12]
    DIRECTION INPUT ;
    USE SIGNAL ;
    PORT
      LAYER Metal2 ;
        RECT 239.680 0.000 240.240 0.560 ;
    END
  END scramble_nonce_i[12]
  PIN scramble_nonce_i[13]
    DIRECTION INPUT ;
    USE SIGNAL ;
    PORT
      LAYER Metal2 ;
        RECT 240.800 0.000 241.360 0.560 ;
    END
  END scramble_nonce_i[13]
  PIN scramble_nonce_i[14]
    DIRECTION INPUT ;
    USE SIGNAL ;
    PORT
      LAYER Metal2 ;
        RECT 241.920 0.000 242.480 0.560 ;
    END
  END scramble_nonce_i[14]
  PIN scramble_nonce_i[15]
    DIRECTION INPUT ;
    USE SIGNAL ;
    PORT
      LAYER Metal2 ;
        RECT 243.040 0.000 243.600 0.560 ;
    END
  END scramble_nonce_i[15]
  PIN scramble_nonce_i[16]
    DIRECTION INPUT ;
    USE SIGNAL ;
    PORT
      LAYER Metal2 ;
        RECT 244.160 0.000 244.720 0.560 ;
    END
  END scramble_nonce_i[16]
  PIN scramble_nonce_i[17]
    DIRECTION INPUT ;
    USE SIGNAL ;
    PORT
      LAYER Metal2 ;
        RECT 245.280 0.000 245.840 0.560 ;
    END
  END scramble_nonce_i[17]
  PIN scramble_nonce_i[18]
    DIRECTION INPUT ;
    USE SIGNAL ;
    PORT
      LAYER Metal2 ;
        RECT 246.400 0.000 246.960 0.560 ;
    END
  END scramble_nonce_i[18]
  PIN scramble_nonce_i[19]
    DIRECTION INPUT ;
    USE SIGNAL ;
    PORT
      LAYER Metal2 ;
        RECT 247.520 0.000 248.080 0.560 ;
    END
  END scramble_nonce_i[19]
  PIN scramble_nonce_i[1]
    DIRECTION INPUT ;
    USE SIGNAL ;
    PORT
      LAYER Metal2 ;
        RECT 248.640 0.000 249.200 0.560 ;
    END
  END scramble_nonce_i[1]
  PIN scramble_nonce_i[20]
    DIRECTION INPUT ;
    USE SIGNAL ;
    PORT
      LAYER Metal2 ;
        RECT 249.760 0.000 250.320 0.560 ;
    END
  END scramble_nonce_i[20]
  PIN scramble_nonce_i[21]
    DIRECTION INPUT ;
    USE SIGNAL ;
    PORT
      LAYER Metal2 ;
        RECT 250.880 0.000 251.440 0.560 ;
    END
  END scramble_nonce_i[21]
  PIN scramble_nonce_i[22]
    DIRECTION INPUT ;
    USE SIGNAL ;
    PORT
      LAYER Metal2 ;
        RECT 252.000 0.000 252.560 0.560 ;
    END
  END scramble_nonce_i[22]
  PIN scramble_nonce_i[23]
    DIRECTION INPUT ;
    USE SIGNAL ;
    PORT
      LAYER Metal2 ;
        RECT 253.120 0.000 253.680 0.560 ;
    END
  END scramble_nonce_i[23]
  PIN scramble_nonce_i[24]
    DIRECTION INPUT ;
    USE SIGNAL ;
    PORT
      LAYER Metal2 ;
        RECT 254.240 0.000 254.800 0.560 ;
    END
  END scramble_nonce_i[24]
  PIN scramble_nonce_i[25]
    DIRECTION INPUT ;
    USE SIGNAL ;
    PORT
      LAYER Metal2 ;
        RECT 255.360 0.000 255.920 0.560 ;
    END
  END scramble_nonce_i[25]
  PIN scramble_nonce_i[26]
    DIRECTION INPUT ;
    USE SIGNAL ;
    PORT
      LAYER Metal2 ;
        RECT 256.480 0.000 257.040 0.560 ;
    END
  END scramble_nonce_i[26]
  PIN scramble_nonce_i[27]
    DIRECTION INPUT ;
    USE SIGNAL ;
    PORT
      LAYER Metal2 ;
        RECT 257.600 0.000 258.160 0.560 ;
    END
  END scramble_nonce_i[27]
  PIN scramble_nonce_i[28]
    DIRECTION INPUT ;
    USE SIGNAL ;
    PORT
      LAYER Metal2 ;
        RECT 258.720 0.000 259.280 0.560 ;
    END
  END scramble_nonce_i[28]
  PIN scramble_nonce_i[29]
    DIRECTION INPUT ;
    USE SIGNAL ;
    PORT
      LAYER Metal2 ;
        RECT 259.840 0.000 260.400 0.560 ;
    END
  END scramble_nonce_i[29]
  PIN scramble_nonce_i[2]
    DIRECTION INPUT ;
    USE SIGNAL ;
    PORT
      LAYER Metal2 ;
        RECT 260.960 0.000 261.520 0.560 ;
    END
  END scramble_nonce_i[2]
  PIN scramble_nonce_i[30]
    DIRECTION INPUT ;
    USE SIGNAL ;
    PORT
      LAYER Metal2 ;
        RECT 262.080 0.000 262.640 0.560 ;
    END
  END scramble_nonce_i[30]
  PIN scramble_nonce_i[31]
    DIRECTION INPUT ;
    USE SIGNAL ;
    PORT
      LAYER Metal2 ;
        RECT 263.200 0.000 263.760 0.560 ;
    END
  END scramble_nonce_i[31]
  PIN scramble_nonce_i[32]
    DIRECTION INPUT ;
    USE SIGNAL ;
    PORT
      LAYER Metal2 ;
        RECT 264.320 0.000 264.880 0.560 ;
    END
  END scramble_nonce_i[32]
  PIN scramble_nonce_i[33]
    DIRECTION INPUT ;
    USE SIGNAL ;
    PORT
      LAYER Metal2 ;
        RECT 265.440 0.000 266.000 0.560 ;
    END
  END scramble_nonce_i[33]
  PIN scramble_nonce_i[34]
    DIRECTION INPUT ;
    USE SIGNAL ;
    PORT
      LAYER Metal2 ;
        RECT 266.560 0.000 267.120 0.560 ;
    END
  END scramble_nonce_i[34]
  PIN scramble_nonce_i[35]
    DIRECTION INPUT ;
    USE SIGNAL ;
    PORT
      LAYER Metal2 ;
        RECT 267.680 0.000 268.240 0.560 ;
    END
  END scramble_nonce_i[35]
  PIN scramble_nonce_i[36]
    DIRECTION INPUT ;
    USE SIGNAL ;
    PORT
      LAYER Metal2 ;
        RECT 268.800 0.000 269.360 0.560 ;
    END
  END scramble_nonce_i[36]
  PIN scramble_nonce_i[37]
    DIRECTION INPUT ;
    USE SIGNAL ;
    PORT
      LAYER Metal2 ;
        RECT 269.920 0.000 270.480 0.560 ;
    END
  END scramble_nonce_i[37]
  PIN scramble_nonce_i[38]
    DIRECTION INPUT ;
    USE SIGNAL ;
    PORT
      LAYER Metal2 ;
        RECT 271.040 0.000 271.600 0.560 ;
    END
  END scramble_nonce_i[38]
  PIN scramble_nonce_i[39]
    DIRECTION INPUT ;
    USE SIGNAL ;
    PORT
      LAYER Metal2 ;
        RECT 272.160 0.000 272.720 0.560 ;
    END
  END scramble_nonce_i[39]
  PIN scramble_nonce_i[3]
    DIRECTION INPUT ;
    USE SIGNAL ;
    PORT
      LAYER Metal2 ;
        RECT 273.280 0.000 273.840 0.560 ;
    END
  END scramble_nonce_i[3]
  PIN scramble_nonce_i[40]
    DIRECTION INPUT ;
    USE SIGNAL ;
    PORT
      LAYER Metal2 ;
        RECT 274.400 0.000 274.960 0.560 ;
    END
  END scramble_nonce_i[40]
  PIN scramble_nonce_i[41]
    DIRECTION INPUT ;
    USE SIGNAL ;
    PORT
      LAYER Metal2 ;
        RECT 275.520 0.000 276.080 0.560 ;
    END
  END scramble_nonce_i[41]
  PIN scramble_nonce_i[42]
    DIRECTION INPUT ;
    USE SIGNAL ;
    PORT
      LAYER Metal2 ;
        RECT 276.640 0.000 277.200 0.560 ;
    END
  END scramble_nonce_i[42]
  PIN scramble_nonce_i[43]
    DIRECTION INPUT ;
    USE SIGNAL ;
    PORT
      LAYER Metal2 ;
        RECT 277.760 0.000 278.320 0.560 ;
    END
  END scramble_nonce_i[43]
  PIN scramble_nonce_i[44]
    DIRECTION INPUT ;
    USE SIGNAL ;
    PORT
      LAYER Metal2 ;
        RECT 278.880 0.000 279.440 0.560 ;
    END
  END scramble_nonce_i[44]
  PIN scramble_nonce_i[45]
    DIRECTION INPUT ;
    USE SIGNAL ;
    PORT
      LAYER Metal2 ;
        RECT 280.000 0.000 280.560 0.560 ;
    END
  END scramble_nonce_i[45]
  PIN scramble_nonce_i[46]
    DIRECTION INPUT ;
    USE SIGNAL ;
    PORT
      LAYER Metal2 ;
        RECT 281.120 0.000 281.680 0.560 ;
    END
  END scramble_nonce_i[46]
  PIN scramble_nonce_i[47]
    DIRECTION INPUT ;
    USE SIGNAL ;
    PORT
      LAYER Metal2 ;
        RECT 282.240 0.000 282.800 0.560 ;
    END
  END scramble_nonce_i[47]
  PIN scramble_nonce_i[48]
    DIRECTION INPUT ;
    USE SIGNAL ;
    PORT
      LAYER Metal2 ;
        RECT 283.360 0.000 283.920 0.560 ;
    END
  END scramble_nonce_i[48]
  PIN scramble_nonce_i[49]
    DIRECTION INPUT ;
    USE SIGNAL ;
    PORT
      LAYER Metal2 ;
        RECT 284.480 0.000 285.040 0.560 ;
    END
  END scramble_nonce_i[49]
  PIN scramble_nonce_i[4]
    DIRECTION INPUT ;
    USE SIGNAL ;
    PORT
      LAYER Metal2 ;
        RECT 285.600 0.000 286.160 0.560 ;
    END
  END scramble_nonce_i[4]
  PIN scramble_nonce_i[50]
    DIRECTION INPUT ;
    USE SIGNAL ;
    PORT
      LAYER Metal2 ;
        RECT 286.720 0.000 287.280 0.560 ;
    END
  END scramble_nonce_i[50]
  PIN scramble_nonce_i[51]
    DIRECTION INPUT ;
    USE SIGNAL ;
    PORT
      LAYER Metal2 ;
        RECT 287.840 0.000 288.400 0.560 ;
    END
  END scramble_nonce_i[51]
  PIN scramble_nonce_i[52]
    DIRECTION INPUT ;
    USE SIGNAL ;
    PORT
      LAYER Metal2 ;
        RECT 288.960 0.000 289.520 0.560 ;
    END
  END scramble_nonce_i[52]
  PIN scramble_nonce_i[53]
    DIRECTION INPUT ;
    USE SIGNAL ;
    PORT
      LAYER Metal2 ;
        RECT 290.080 0.000 290.640 0.560 ;
    END
  END scramble_nonce_i[53]
  PIN scramble_nonce_i[54]
    DIRECTION INPUT ;
    USE SIGNAL ;
    PORT
      LAYER Metal2 ;
        RECT 291.200 0.000 291.760 0.560 ;
    END
  END scramble_nonce_i[54]
  PIN scramble_nonce_i[55]
    DIRECTION INPUT ;
    USE SIGNAL ;
    PORT
      LAYER Metal2 ;
        RECT 292.320 0.000 292.880 0.560 ;
    END
  END scramble_nonce_i[55]
  PIN scramble_nonce_i[56]
    DIRECTION INPUT ;
    USE SIGNAL ;
    PORT
      LAYER Metal2 ;
        RECT 293.440 0.000 294.000 0.560 ;
    END
  END scramble_nonce_i[56]
  PIN scramble_nonce_i[57]
    DIRECTION INPUT ;
    USE SIGNAL ;
    PORT
      LAYER Metal2 ;
        RECT 294.560 0.000 295.120 0.560 ;
    END
  END scramble_nonce_i[57]
  PIN scramble_nonce_i[58]
    DIRECTION INPUT ;
    USE SIGNAL ;
    PORT
      LAYER Metal2 ;
        RECT 295.680 0.000 296.240 0.560 ;
    END
  END scramble_nonce_i[58]
  PIN scramble_nonce_i[59]
    DIRECTION INPUT ;
    USE SIGNAL ;
    PORT
      LAYER Metal2 ;
        RECT 296.800 0.000 297.360 0.560 ;
    END
  END scramble_nonce_i[59]
  PIN scramble_nonce_i[5]
    DIRECTION INPUT ;
    USE SIGNAL ;
    PORT
      LAYER Metal2 ;
        RECT 297.920 0.000 298.480 0.560 ;
    END
  END scramble_nonce_i[5]
  PIN scramble_nonce_i[60]
    DIRECTION INPUT ;
    USE SIGNAL ;
    PORT
      LAYER Metal2 ;
        RECT 299.040 0.000 299.600 0.560 ;
    END
  END scramble_nonce_i[60]
  PIN scramble_nonce_i[61]
    DIRECTION INPUT ;
    USE SIGNAL ;
    PORT
      LAYER Metal2 ;
        RECT 300.160 0.000 300.720 0.560 ;
    END
  END scramble_nonce_i[61]
  PIN scramble_nonce_i[62]
    DIRECTION INPUT ;
    USE SIGNAL ;
    PORT
      LAYER Metal2 ;
        RECT 301.280 0.000 301.840 0.560 ;
    END
  END scramble_nonce_i[62]
  PIN scramble_nonce_i[63]
    DIRECTION INPUT ;
    USE SIGNAL ;
    PORT
      LAYER Metal2 ;
        RECT 302.400 0.000 302.960 0.560 ;
    END
  END scramble_nonce_i[63]
  PIN scramble_nonce_i[6]
    DIRECTION INPUT ;
    USE SIGNAL ;
    PORT
      LAYER Metal2 ;
        RECT 303.520 0.000 304.080 0.560 ;
    END
  END scramble_nonce_i[6]
  PIN scramble_nonce_i[7]
    DIRECTION INPUT ;
    USE SIGNAL ;
    PORT
      LAYER Metal2 ;
        RECT 304.640 0.000 305.200 0.560 ;
    END
  END scramble_nonce_i[7]
  PIN scramble_nonce_i[8]
    DIRECTION INPUT ;
    USE SIGNAL ;
    PORT
      LAYER Metal2 ;
        RECT 305.760 0.000 306.320 0.560 ;
    END
  END scramble_nonce_i[8]
  PIN scramble_nonce_i[9]
    DIRECTION INPUT ;
    USE SIGNAL ;
    PORT
      LAYER Metal2 ;
        RECT 306.880 0.000 307.440 0.560 ;
    END
  END scramble_nonce_i[9]
  PIN scramble_req_o
    DIRECTION OUTPUT ;
    USE SIGNAL ;
    ANTENNADIFFAREA 0.360800 ;
    PORT
      LAYER Metal2 ;
        RECT 812.000 0.000 812.560 0.560 ;
    END
  END scramble_req_o
  PIN test_en_i
    DIRECTION INPUT ;
    USE SIGNAL ;
    PORT
      LAYER Metal2 ;
        RECT 308.000 0.000 308.560 0.560 ;
    END
  END test_en_i
  OBS
      LAYER Nwell ;
        RECT 6.290 15.250 846.590 854.990 ;
      LAYER Metal1 ;
        RECT 6.720 15.380 846.160 854.860 ;
      LAYER Metal2 ;
        RECT 0.140 870.325 22.100 871.045 ;
        RECT 23.260 870.325 28.820 871.045 ;
        RECT 29.980 870.325 43.380 871.045 ;
        RECT 44.540 870.325 45.620 871.045 ;
        RECT 46.780 870.325 54.580 871.045 ;
        RECT 55.740 870.325 57.940 871.045 ;
        RECT 59.100 870.325 70.260 871.045 ;
        RECT 71.420 870.325 80.340 871.045 ;
        RECT 82.620 870.325 91.540 871.045 ;
        RECT 92.700 870.325 106.100 871.045 ;
        RECT 107.260 870.325 121.780 871.045 ;
        RECT 122.940 870.325 150.900 871.045 ;
        RECT 152.060 870.325 178.900 871.045 ;
        RECT 180.060 870.325 206.900 871.045 ;
        RECT 208.060 870.325 223.700 871.045 ;
        RECT 224.860 870.325 229.300 871.045 ;
        RECT 230.460 870.325 244.980 871.045 ;
        RECT 246.140 870.325 264.020 871.045 ;
        RECT 266.300 870.325 268.500 871.045 ;
        RECT 270.780 870.325 274.100 871.045 ;
        RECT 276.380 870.325 278.580 871.045 ;
        RECT 279.740 870.325 280.820 871.045 ;
        RECT 281.980 870.325 286.420 871.045 ;
        RECT 288.700 870.325 290.900 871.045 ;
        RECT 295.420 870.325 302.100 871.045 ;
        RECT 303.260 870.325 305.460 871.045 ;
        RECT 306.620 870.325 322.260 871.045 ;
        RECT 323.420 870.325 325.620 871.045 ;
        RECT 326.780 870.325 337.940 871.045 ;
        RECT 339.100 870.325 341.300 871.045 ;
        RECT 344.700 870.325 345.780 871.045 ;
        RECT 348.060 870.325 354.740 871.045 ;
        RECT 358.140 870.325 371.540 871.045 ;
        RECT 373.820 870.325 374.900 871.045 ;
        RECT 376.060 870.325 377.140 871.045 ;
        RECT 379.420 870.325 380.500 871.045 ;
        RECT 385.020 870.325 386.100 871.045 ;
        RECT 404.060 870.325 408.500 871.045 ;
        RECT 409.660 870.325 420.820 871.045 ;
        RECT 421.980 870.325 423.060 871.045 ;
        RECT 426.460 870.325 427.540 871.045 ;
        RECT 432.060 870.325 433.140 871.045 ;
        RECT 451.100 870.325 452.180 871.045 ;
        RECT 456.700 870.325 458.900 871.045 ;
        RECT 490.300 870.325 491.380 871.045 ;
        RECT 494.780 870.325 496.980 871.045 ;
        RECT 561.980 870.325 564.180 871.045 ;
        RECT 567.580 870.325 568.660 871.045 ;
        RECT 575.420 870.325 576.500 871.045 ;
        RECT 579.900 870.325 580.980 871.045 ;
        RECT 588.860 870.325 591.060 871.045 ;
        RECT 611.260 870.325 612.340 871.045 ;
        RECT 615.740 870.325 617.940 871.045 ;
        RECT 621.340 870.325 623.540 871.045 ;
        RECT 628.060 870.325 630.260 871.045 ;
        RECT 639.260 870.325 642.580 871.045 ;
        RECT 643.740 870.325 647.060 871.045 ;
        RECT 652.700 870.325 658.260 871.045 ;
        RECT 659.420 870.325 662.740 871.045 ;
        RECT 680.700 870.325 681.780 871.045 ;
        RECT 687.420 870.325 689.620 871.045 ;
        RECT 690.780 870.325 695.220 871.045 ;
        RECT 697.500 870.325 714.260 871.045 ;
        RECT 722.140 870.325 725.460 871.045 ;
        RECT 726.620 870.325 728.820 871.045 ;
        RECT 729.980 870.325 733.300 871.045 ;
        RECT 734.460 870.325 736.660 871.045 ;
        RECT 737.820 870.325 740.020 871.045 ;
        RECT 742.300 870.325 745.620 871.045 ;
        RECT 746.780 870.325 752.340 871.045 ;
        RECT 755.740 870.325 763.540 871.045 ;
        RECT 764.700 870.325 770.260 871.045 ;
        RECT 772.540 870.325 778.100 871.045 ;
        RECT 779.260 870.325 788.180 871.045 ;
        RECT 790.460 870.325 794.900 871.045 ;
        RECT 797.180 870.325 852.180 871.045 ;
        RECT 0.140 0.860 852.180 870.325 ;
        RECT 0.140 0.560 0.820 0.860 ;
        RECT 308.860 0.560 453.300 0.860 ;
        RECT 454.460 0.560 465.620 0.860 ;
        RECT 470.140 0.560 471.220 0.860 ;
        RECT 472.380 0.560 476.820 0.860 ;
        RECT 477.980 0.560 481.300 0.860 ;
        RECT 485.820 0.560 486.900 0.860 ;
        RECT 488.060 0.560 489.140 0.860 ;
        RECT 493.660 0.560 494.740 0.860 ;
        RECT 497.020 0.560 498.100 0.860 ;
        RECT 499.260 0.560 501.460 0.860 ;
        RECT 502.620 0.560 503.700 0.860 ;
        RECT 507.100 0.560 508.180 0.860 ;
        RECT 509.340 0.560 514.900 0.860 ;
        RECT 520.540 0.560 522.740 0.860 ;
        RECT 523.900 0.560 526.100 0.860 ;
        RECT 528.380 0.560 529.460 0.860 ;
        RECT 530.620 0.560 539.540 0.860 ;
        RECT 540.700 0.560 541.780 0.860 ;
        RECT 542.940 0.560 546.260 0.860 ;
        RECT 547.420 0.560 743.380 0.860 ;
        RECT 744.540 0.560 745.620 0.860 ;
        RECT 746.780 0.560 771.380 0.860 ;
        RECT 772.540 0.560 773.620 0.860 ;
        RECT 777.020 0.560 779.220 0.860 ;
        RECT 782.620 0.560 787.060 0.860 ;
        RECT 788.220 0.560 793.780 0.860 ;
        RECT 794.940 0.560 798.260 0.860 ;
        RECT 803.900 0.560 804.980 0.860 ;
        RECT 808.380 0.560 811.700 0.860 ;
        RECT 815.100 0.560 819.540 0.860 ;
        RECT 820.700 0.560 827.380 0.860 ;
        RECT 828.540 0.560 839.700 0.860 ;
        RECT 844.220 0.560 852.180 0.860 ;
      LAYER Metal3 ;
        RECT 0.090 850.940 852.705 870.660 ;
        RECT 0.860 846.420 852.405 850.940 ;
        RECT 0.860 844.180 852.705 846.420 ;
        RECT 0.090 839.740 852.705 844.180 ;
        RECT 0.860 838.580 852.705 839.740 ;
        RECT 0.090 835.260 852.705 838.580 ;
        RECT 0.860 834.100 852.705 835.260 ;
        RECT 0.090 833.020 852.705 834.100 ;
        RECT 0.860 831.860 852.705 833.020 ;
        RECT 0.090 826.300 852.705 831.860 ;
        RECT 0.090 825.140 852.405 826.300 ;
        RECT 0.090 824.060 852.705 825.140 ;
        RECT 0.860 817.300 852.705 824.060 ;
        RECT 0.090 816.220 852.705 817.300 ;
        RECT 0.090 815.060 852.405 816.220 ;
        RECT 0.090 812.860 852.705 815.060 ;
        RECT 0.860 811.700 852.405 812.860 ;
        RECT 0.090 808.380 852.705 811.700 ;
        RECT 0.860 807.220 852.705 808.380 ;
        RECT 0.090 806.140 852.705 807.220 ;
        RECT 0.860 804.980 852.705 806.140 ;
        RECT 0.090 803.900 852.705 804.980 ;
        RECT 0.860 802.740 852.705 803.900 ;
        RECT 0.090 799.420 852.705 802.740 ;
        RECT 0.860 790.420 852.705 799.420 ;
        RECT 0.090 788.220 852.705 790.420 ;
        RECT 0.860 785.940 852.705 788.220 ;
        RECT 0.090 781.500 852.705 785.940 ;
        RECT 0.860 778.100 852.705 781.500 ;
        RECT 0.090 773.660 852.705 778.100 ;
        RECT 0.860 772.500 852.705 773.660 ;
        RECT 0.090 769.180 852.705 772.500 ;
        RECT 0.860 768.020 852.705 769.180 ;
        RECT 0.090 765.820 852.705 768.020 ;
        RECT 0.860 764.660 852.705 765.820 ;
        RECT 0.090 760.220 852.705 764.660 ;
        RECT 0.090 759.060 852.405 760.220 ;
        RECT 0.090 756.860 852.705 759.060 ;
        RECT 0.860 755.700 852.705 756.860 ;
        RECT 0.090 753.500 852.705 755.700 ;
        RECT 0.860 752.340 852.705 753.500 ;
        RECT 0.090 746.780 852.705 752.340 ;
        RECT 0.860 744.500 852.705 746.780 ;
        RECT 0.090 742.300 852.705 744.500 ;
        RECT 0.860 741.140 852.705 742.300 ;
        RECT 0.090 736.700 852.705 741.140 ;
        RECT 0.860 735.540 852.705 736.700 ;
        RECT 0.090 726.620 852.705 735.540 ;
        RECT 0.860 725.460 852.705 726.620 ;
        RECT 0.090 722.140 852.705 725.460 ;
        RECT 0.860 720.980 852.705 722.140 ;
        RECT 0.090 712.060 852.705 720.980 ;
        RECT 0.860 710.900 852.705 712.060 ;
        RECT 0.090 700.860 852.705 710.900 ;
        RECT 0.860 699.700 852.705 700.860 ;
        RECT 0.090 698.620 852.705 699.700 ;
        RECT 0.090 697.460 852.405 698.620 ;
        RECT 0.090 689.660 852.705 697.460 ;
        RECT 0.860 688.500 852.705 689.660 ;
        RECT 0.090 686.300 852.705 688.500 ;
        RECT 0.860 685.140 852.705 686.300 ;
        RECT 0.090 680.700 852.705 685.140 ;
        RECT 0.090 679.540 852.405 680.700 ;
        RECT 0.090 675.100 852.705 679.540 ;
        RECT 0.860 673.940 852.705 675.100 ;
        RECT 0.090 671.740 852.705 673.940 ;
        RECT 0.860 670.580 852.705 671.740 ;
        RECT 0.090 658.300 852.705 670.580 ;
        RECT 0.090 657.180 852.405 658.300 ;
        RECT 0.860 657.140 852.405 657.180 ;
        RECT 0.860 656.020 852.705 657.140 ;
        RECT 0.090 651.580 852.705 656.020 ;
        RECT 0.860 650.420 852.705 651.580 ;
        RECT 0.090 641.500 852.705 650.420 ;
        RECT 0.860 640.340 852.705 641.500 ;
        RECT 0.090 637.020 852.705 640.340 ;
        RECT 0.090 634.740 852.405 637.020 ;
        RECT 0.090 633.660 852.705 634.740 ;
        RECT 0.860 632.540 852.705 633.660 ;
        RECT 0.860 632.500 852.405 632.540 ;
        RECT 0.090 631.380 852.405 632.500 ;
        RECT 0.090 630.300 852.705 631.380 ;
        RECT 0.090 629.140 852.405 630.300 ;
        RECT 0.090 626.940 852.705 629.140 ;
        RECT 0.860 625.820 852.705 626.940 ;
        RECT 0.860 625.780 852.405 625.820 ;
        RECT 0.090 621.300 852.405 625.780 ;
        RECT 0.090 619.100 852.705 621.300 ;
        RECT 0.090 617.980 852.405 619.100 ;
        RECT 0.860 617.940 852.405 617.980 ;
        RECT 0.860 616.820 852.705 617.940 ;
        RECT 0.090 615.740 852.705 616.820 ;
        RECT 0.090 614.620 852.405 615.740 ;
        RECT 0.860 614.580 852.405 614.620 ;
        RECT 0.860 613.500 852.705 614.580 ;
        RECT 0.860 612.340 852.405 613.500 ;
        RECT 0.090 611.220 852.405 612.340 ;
        RECT 0.090 606.780 852.705 611.220 ;
        RECT 0.090 603.380 852.405 606.780 ;
        RECT 0.090 598.940 852.705 603.380 ;
        RECT 0.090 593.300 852.405 598.940 ;
        RECT 0.090 587.740 852.705 593.300 ;
        RECT 0.090 584.340 852.405 587.740 ;
        RECT 0.090 577.660 852.705 584.340 ;
        RECT 0.090 576.500 852.405 577.660 ;
        RECT 0.090 575.420 852.705 576.500 ;
        RECT 0.090 574.260 852.405 575.420 ;
        RECT 0.090 572.060 852.705 574.260 ;
        RECT 0.090 567.540 852.405 572.060 ;
        RECT 0.090 563.100 852.705 567.540 ;
        RECT 0.090 560.820 852.405 563.100 ;
        RECT 0.090 557.500 852.705 560.820 ;
        RECT 0.090 556.340 852.405 557.500 ;
        RECT 0.090 555.260 852.705 556.340 ;
        RECT 0.090 554.100 852.405 555.260 ;
        RECT 0.090 547.420 852.705 554.100 ;
        RECT 0.090 546.260 852.405 547.420 ;
        RECT 0.090 535.100 852.705 546.260 ;
        RECT 0.090 533.940 852.405 535.100 ;
        RECT 0.090 525.020 852.705 533.940 ;
        RECT 0.860 523.860 852.705 525.020 ;
        RECT 0.090 522.780 852.705 523.860 ;
        RECT 0.090 518.260 852.405 522.780 ;
        RECT 0.090 493.660 852.705 518.260 ;
        RECT 0.860 491.420 852.705 493.660 ;
        RECT 0.860 491.380 852.405 491.420 ;
        RECT 0.090 490.260 852.405 491.380 ;
        RECT 0.090 489.180 852.705 490.260 ;
        RECT 0.860 488.020 852.705 489.180 ;
        RECT 0.090 485.820 852.705 488.020 ;
        RECT 0.860 484.660 852.705 485.820 ;
        RECT 0.090 472.380 852.705 484.660 ;
        RECT 0.090 470.100 852.405 472.380 ;
        RECT 0.090 469.020 852.705 470.100 ;
        RECT 0.090 467.860 852.405 469.020 ;
        RECT 0.090 458.940 852.705 467.860 ;
        RECT 0.090 455.540 852.405 458.940 ;
        RECT 0.090 449.980 852.705 455.540 ;
        RECT 0.090 448.820 852.405 449.980 ;
        RECT 0.090 446.620 852.705 448.820 ;
        RECT 0.090 445.460 852.405 446.620 ;
        RECT 0.090 427.580 852.705 445.460 ;
        RECT 0.090 425.300 852.405 427.580 ;
        RECT 0.090 409.660 852.705 425.300 ;
        RECT 0.090 408.500 852.405 409.660 ;
        RECT 0.090 405.180 852.705 408.500 ;
        RECT 0.090 404.020 852.405 405.180 ;
        RECT 0.090 401.820 852.705 404.020 ;
        RECT 0.090 396.180 852.405 401.820 ;
        RECT 0.090 389.500 852.705 396.180 ;
        RECT 0.090 388.340 852.405 389.500 ;
        RECT 0.090 378.300 852.705 388.340 ;
        RECT 0.090 377.140 852.405 378.300 ;
        RECT 0.090 374.940 852.705 377.140 ;
        RECT 0.090 371.540 852.405 374.940 ;
        RECT 0.090 369.340 852.705 371.540 ;
        RECT 0.090 368.180 852.405 369.340 ;
        RECT 0.090 363.740 852.705 368.180 ;
        RECT 0.090 361.460 852.405 363.740 ;
        RECT 0.090 360.380 852.705 361.460 ;
        RECT 0.090 359.220 852.405 360.380 ;
        RECT 0.090 337.980 852.705 359.220 ;
        RECT 0.090 335.700 852.405 337.980 ;
        RECT 0.090 334.620 852.705 335.700 ;
        RECT 0.090 333.460 852.405 334.620 ;
        RECT 0.090 331.260 852.705 333.460 ;
        RECT 0.090 325.620 852.405 331.260 ;
        RECT 0.090 185.660 852.705 325.620 ;
        RECT 0.090 184.500 852.405 185.660 ;
        RECT 0.090 154.300 852.705 184.500 ;
        RECT 0.090 153.140 852.405 154.300 ;
        RECT 0.090 139.740 852.705 153.140 ;
        RECT 0.090 138.580 852.405 139.740 ;
        RECT 0.090 126.300 852.705 138.580 ;
        RECT 0.090 125.140 852.405 126.300 ;
        RECT 0.090 118.460 852.705 125.140 ;
        RECT 0.090 116.180 852.405 118.460 ;
        RECT 0.090 106.140 852.705 116.180 ;
        RECT 0.090 103.860 852.405 106.140 ;
        RECT 0.090 96.060 852.705 103.860 ;
        RECT 0.090 91.540 852.405 96.060 ;
        RECT 0.090 80.380 852.705 91.540 ;
        RECT 0.090 76.980 852.405 80.380 ;
        RECT 0.090 75.900 852.705 76.980 ;
        RECT 0.090 72.500 852.405 75.900 ;
        RECT 0.090 70.300 852.705 72.500 ;
        RECT 0.090 69.140 852.405 70.300 ;
        RECT 0.090 64.700 852.705 69.140 ;
        RECT 0.090 63.540 852.405 64.700 ;
        RECT 0.090 61.340 852.705 63.540 ;
        RECT 0.090 60.180 852.405 61.340 ;
        RECT 0.090 56.860 852.705 60.180 ;
        RECT 0.090 53.460 852.405 56.860 ;
        RECT 0.090 50.140 852.705 53.460 ;
        RECT 0.090 48.980 852.405 50.140 ;
        RECT 0.090 29.980 852.705 48.980 ;
        RECT 0.860 28.820 852.705 29.980 ;
        RECT 0.090 21.020 852.705 28.820 ;
        RECT 0.860 19.860 852.405 21.020 ;
        RECT 0.860 17.620 852.705 19.860 ;
        RECT 0.090 6.300 852.705 17.620 ;
      LAYER Metal4 ;
        RECT 9.100 864.760 842.660 870.710 ;
        RECT 9.100 16.890 21.940 864.760 ;
        RECT 24.140 16.890 25.240 864.760 ;
        RECT 27.440 16.890 175.540 864.760 ;
        RECT 177.740 16.890 178.840 864.760 ;
        RECT 181.040 16.890 329.140 864.760 ;
        RECT 331.340 16.890 332.440 864.760 ;
        RECT 334.640 16.890 482.740 864.760 ;
        RECT 484.940 16.890 486.040 864.760 ;
        RECT 488.240 16.890 636.340 864.760 ;
        RECT 638.540 16.890 639.640 864.760 ;
        RECT 641.840 16.890 789.940 864.760 ;
        RECT 792.140 16.890 793.240 864.760 ;
        RECT 795.440 16.890 842.660 864.760 ;
      LAYER Metal5 ;
        RECT 9.020 802.930 835.460 853.870 ;
        RECT 9.020 799.630 835.460 800.130 ;
        RECT 9.020 649.750 835.460 796.830 ;
        RECT 9.020 646.450 835.460 646.950 ;
        RECT 9.020 496.570 835.460 643.650 ;
        RECT 9.020 493.270 835.460 493.770 ;
        RECT 9.020 343.390 835.460 490.470 ;
        RECT 9.020 340.090 835.460 340.590 ;
        RECT 9.020 190.210 835.460 337.290 ;
        RECT 9.020 186.910 835.460 187.410 ;
        RECT 9.020 37.130 835.460 184.110 ;
  END
END ibex_top
END LIBRARY

